VERSION 5.8 ;
BUSBITCHARS "[]" ;
DIVIDERCHAR "/" ;
UNITS
    DATABASE MICRONS 1000 ;
END UNITS

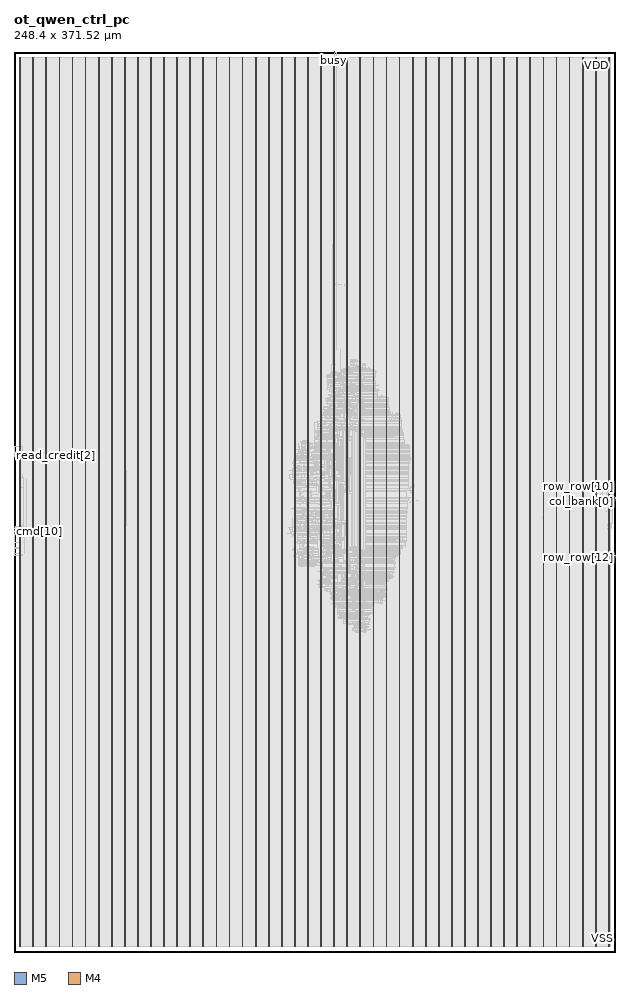
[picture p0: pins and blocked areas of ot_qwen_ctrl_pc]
MACRO ot_qwen_ctrl_pc
  FOREIGN ot_qwen_ctrl_pc 0 0 ;
  CLASS BLOCK ;
  SIZE 248.4 BY 371.52 ;
  PIN busy
    DIRECTION OUTPUT ;
    USE SIGNAL ;
    PORT
      LAYER M5 ;
        RECT  132.144 371.436 132.168 371.52 ;
    END
  END busy
  PIN clk
    DIRECTION INPUT ;
    USE SIGNAL ;
    PORT
      LAYER M5 ;
        RECT  132.24 371.436 132.264 371.52 ;
    END
  END clk
  PIN cmd[0]
    DIRECTION INPUT ;
    USE SIGNAL ;
    PORT
      LAYER M4 ;
        RECT  0 172.656 0.084 172.68 ;
    END
  END cmd[0]
  PIN cmd[10]
    DIRECTION INPUT ;
    USE SIGNAL ;
    PORT
      LAYER M4 ;
        RECT  0 173.616 0.084 173.64 ;
    END
  END cmd[10]
  PIN cmd[11]
    DIRECTION INPUT ;
    USE SIGNAL ;
    PORT
      LAYER M4 ;
        RECT  0 173.712 0.084 173.736 ;
    END
  END cmd[11]
  PIN cmd[12]
    DIRECTION INPUT ;
    USE SIGNAL ;
    PORT
      LAYER M4 ;
        RECT  0 173.808 0.084 173.832 ;
    END
  END cmd[12]
  PIN cmd[13]
    DIRECTION INPUT ;
    USE SIGNAL ;
    PORT
      LAYER M4 ;
        RECT  0 173.904 0.084 173.928 ;
    END
  END cmd[13]
  PIN cmd[14]
    DIRECTION INPUT ;
    USE SIGNAL ;
    PORT
      LAYER M4 ;
        RECT  0 174 0.084 174.024 ;
    END
  END cmd[14]
  PIN cmd[15]
    DIRECTION INPUT ;
    USE SIGNAL ;
    PORT
      LAYER M4 ;
        RECT  0 174.096 0.084 174.12 ;
    END
  END cmd[15]
  PIN cmd[16]
    DIRECTION INPUT ;
    USE SIGNAL ;
    PORT
      LAYER M4 ;
        RECT  0 174.192 0.084 174.216 ;
    END
  END cmd[16]
  PIN cmd[17]
    DIRECTION INPUT ;
    USE SIGNAL ;
    PORT
      LAYER M4 ;
        RECT  0 174.288 0.084 174.312 ;
    END
  END cmd[17]
  PIN cmd[18]
    DIRECTION INPUT ;
    USE SIGNAL ;
    PORT
      LAYER M4 ;
        RECT  0 174.384 0.084 174.408 ;
    END
  END cmd[18]
  PIN cmd[19]
    DIRECTION INPUT ;
    USE SIGNAL ;
    PORT
      LAYER M4 ;
        RECT  0 174.48 0.084 174.504 ;
    END
  END cmd[19]
  PIN cmd[1]
    DIRECTION INPUT ;
    USE SIGNAL ;
    PORT
      LAYER M4 ;
        RECT  0 172.752 0.084 172.776 ;
    END
  END cmd[1]
  PIN cmd[20]
    DIRECTION INPUT ;
    USE SIGNAL ;
    PORT
      LAYER M4 ;
        RECT  0 174.576 0.084 174.6 ;
    END
  END cmd[20]
  PIN cmd[21]
    DIRECTION INPUT ;
    USE SIGNAL ;
    PORT
      LAYER M4 ;
        RECT  0 174.672 0.084 174.696 ;
    END
  END cmd[21]
  PIN cmd[22]
    DIRECTION INPUT ;
    USE SIGNAL ;
    PORT
      LAYER M4 ;
        RECT  0 174.768 0.084 174.792 ;
    END
  END cmd[22]
  PIN cmd[23]
    DIRECTION INPUT ;
    USE SIGNAL ;
    PORT
      LAYER M4 ;
        RECT  0 174.864 0.084 174.888 ;
    END
  END cmd[23]
  PIN cmd[24]
    DIRECTION INPUT ;
    USE SIGNAL ;
    PORT
      LAYER M4 ;
        RECT  0 174.96 0.084 174.984 ;
    END
  END cmd[24]
  PIN cmd[25]
    DIRECTION INPUT ;
    USE SIGNAL ;
    PORT
      LAYER M4 ;
        RECT  0 175.056 0.084 175.08 ;
    END
  END cmd[25]
  PIN cmd[26]
    DIRECTION INPUT ;
    USE SIGNAL ;
    PORT
      LAYER M4 ;
        RECT  0 175.152 0.084 175.176 ;
    END
  END cmd[26]
  PIN cmd[27]
    DIRECTION INPUT ;
    USE SIGNAL ;
    PORT
      LAYER M4 ;
        RECT  0 175.248 0.084 175.272 ;
    END
  END cmd[27]
  PIN cmd[28]
    DIRECTION INPUT ;
    USE SIGNAL ;
    PORT
      LAYER M4 ;
        RECT  0 175.344 0.084 175.368 ;
    END
  END cmd[28]
  PIN cmd[29]
    DIRECTION INPUT ;
    USE SIGNAL ;
    PORT
      LAYER M4 ;
        RECT  0 175.44 0.084 175.464 ;
    END
  END cmd[29]
  PIN cmd[2]
    DIRECTION INPUT ;
    USE SIGNAL ;
    PORT
      LAYER M4 ;
        RECT  0 172.848 0.084 172.872 ;
    END
  END cmd[2]
  PIN cmd[30]
    DIRECTION INPUT ;
    USE SIGNAL ;
    PORT
      LAYER M4 ;
        RECT  0 175.536 0.084 175.56 ;
    END
  END cmd[30]
  PIN cmd[31]
    DIRECTION INPUT ;
    USE SIGNAL ;
    PORT
      LAYER M4 ;
        RECT  0 175.632 0.084 175.656 ;
    END
  END cmd[31]
  PIN cmd[3]
    DIRECTION INPUT ;
    USE SIGNAL ;
    PORT
      LAYER M4 ;
        RECT  0 172.944 0.084 172.968 ;
    END
  END cmd[3]
  PIN cmd[4]
    DIRECTION INPUT ;
    USE SIGNAL ;
    PORT
      LAYER M4 ;
        RECT  0 173.04 0.084 173.064 ;
    END
  END cmd[4]
  PIN cmd[5]
    DIRECTION INPUT ;
    USE SIGNAL ;
    PORT
      LAYER M4 ;
        RECT  0 173.136 0.084 173.16 ;
    END
  END cmd[5]
  PIN cmd[6]
    DIRECTION INPUT ;
    USE SIGNAL ;
    PORT
      LAYER M4 ;
        RECT  0 173.232 0.084 173.256 ;
    END
  END cmd[6]
  PIN cmd[7]
    DIRECTION INPUT ;
    USE SIGNAL ;
    PORT
      LAYER M4 ;
        RECT  0 173.328 0.084 173.352 ;
    END
  END cmd[7]
  PIN cmd[8]
    DIRECTION INPUT ;
    USE SIGNAL ;
    PORT
      LAYER M4 ;
        RECT  0 173.424 0.084 173.448 ;
    END
  END cmd[8]
  PIN cmd[9]
    DIRECTION INPUT ;
    USE SIGNAL ;
    PORT
      LAYER M4 ;
        RECT  0 173.52 0.084 173.544 ;
    END
  END cmd[9]
  PIN cmd_credit
    DIRECTION OUTPUT ;
    USE SIGNAL ;
    PORT
      LAYER M4 ;
        RECT  0 204.72 0.084 204.744 ;
    END
  END cmd_credit
  PIN cmd_v
    DIRECTION INPUT ;
    USE SIGNAL ;
    PORT
      LAYER M4 ;
        RECT  0 204.816 0.084 204.84 ;
    END
  END cmd_v
  PIN col_bank[0]
    DIRECTION OUTPUT ;
    USE SIGNAL ;
    PORT
      LAYER M4 ;
        RECT  248.316 185.808 248.4 185.832 ;
    END
  END col_bank[0]
  PIN col_bank[1]
    DIRECTION OUTPUT ;
    USE SIGNAL ;
    PORT
      LAYER M4 ;
        RECT  248.316 185.904 248.4 185.928 ;
    END
  END col_bank[1]
  PIN col_bank[2]
    DIRECTION OUTPUT ;
    USE SIGNAL ;
    PORT
      LAYER M4 ;
        RECT  248.316 186 248.4 186.024 ;
    END
  END col_bank[2]
  PIN col_bank[3]
    DIRECTION OUTPUT ;
    USE SIGNAL ;
    PORT
      LAYER M4 ;
        RECT  248.316 186.096 248.4 186.12 ;
    END
  END col_bank[3]
  PIN col_bank[4]
    DIRECTION OUTPUT ;
    USE SIGNAL ;
    PORT
      LAYER M4 ;
        RECT  248.316 186.192 248.4 186.216 ;
    END
  END col_bank[4]
  PIN col_col[0]
    DIRECTION OUTPUT ;
    USE SIGNAL ;
    PORT
      LAYER M4 ;
        RECT  248.316 186.288 248.4 186.312 ;
    END
  END col_col[0]
  PIN col_col[1]
    DIRECTION OUTPUT ;
    USE SIGNAL ;
    PORT
      LAYER M4 ;
        RECT  248.316 186.384 248.4 186.408 ;
    END
  END col_col[1]
  PIN col_col[2]
    DIRECTION OUTPUT ;
    USE SIGNAL ;
    PORT
      LAYER M4 ;
        RECT  248.316 186.48 248.4 186.504 ;
    END
  END col_col[2]
  PIN col_col[3]
    DIRECTION OUTPUT ;
    USE SIGNAL ;
    PORT
      LAYER M4 ;
        RECT  248.316 186.576 248.4 186.6 ;
    END
  END col_col[3]
  PIN col_col[4]
    DIRECTION OUTPUT ;
    USE SIGNAL ;
    PORT
      LAYER M4 ;
        RECT  248.316 186.672 248.4 186.696 ;
    END
  END col_col[4]
  PIN col_v
    DIRECTION OUTPUT ;
    USE SIGNAL ;
    PORT
      LAYER M4 ;
        RECT  248.316 186.768 248.4 186.792 ;
    END
  END col_v
  PIN col_we
    DIRECTION OUTPUT ;
    USE SIGNAL ;
    PORT
      LAYER M4 ;
        RECT  248.316 186.864 248.4 186.888 ;
    END
  END col_we
  PIN fault
    DIRECTION OUTPUT ;
    USE SIGNAL ;
    PORT
      LAYER M5 ;
        RECT  132.336 371.436 132.36 371.52 ;
    END
  END fault
  PIN read_credit[0]
    DIRECTION INPUT ;
    USE SIGNAL ;
    PORT
      LAYER M4 ;
        RECT  0 204.912 0.084 204.936 ;
    END
  END read_credit[0]
  PIN read_credit[1]
    DIRECTION INPUT ;
    USE SIGNAL ;
    PORT
      LAYER M4 ;
        RECT  0 205.008 0.084 205.032 ;
    END
  END read_credit[1]
  PIN read_credit[2]
    DIRECTION INPUT ;
    USE SIGNAL ;
    PORT
      LAYER M4 ;
        RECT  0 205.104 0.084 205.128 ;
    END
  END read_credit[2]
  PIN row_bank[0]
    DIRECTION OUTPUT ;
    USE SIGNAL ;
    PORT
      LAYER M4 ;
        RECT  248.316 186.96 248.4 186.984 ;
    END
  END row_bank[0]
  PIN row_bank[1]
    DIRECTION OUTPUT ;
    USE SIGNAL ;
    PORT
      LAYER M4 ;
        RECT  248.316 187.056 248.4 187.08 ;
    END
  END row_bank[1]
  PIN row_bank[2]
    DIRECTION OUTPUT ;
    USE SIGNAL ;
    PORT
      LAYER M4 ;
        RECT  248.316 187.152 248.4 187.176 ;
    END
  END row_bank[2]
  PIN row_bank[3]
    DIRECTION OUTPUT ;
    USE SIGNAL ;
    PORT
      LAYER M4 ;
        RECT  248.316 187.248 248.4 187.272 ;
    END
  END row_bank[3]
  PIN row_bank[4]
    DIRECTION OUTPUT ;
    USE SIGNAL ;
    PORT
      LAYER M4 ;
        RECT  248.316 187.344 248.4 187.368 ;
    END
  END row_bank[4]
  PIN row_op[0]
    DIRECTION OUTPUT ;
    USE SIGNAL ;
    PORT
      LAYER M4 ;
        RECT  248.316 187.44 248.4 187.464 ;
    END
  END row_op[0]
  PIN row_op[1]
    DIRECTION OUTPUT ;
    USE SIGNAL ;
    PORT
      LAYER M4 ;
        RECT  248.316 187.536 248.4 187.56 ;
    END
  END row_op[1]
  PIN row_op[2]
    DIRECTION OUTPUT ;
    USE SIGNAL ;
    PORT
      LAYER M4 ;
        RECT  248.316 187.632 248.4 187.656 ;
    END
  END row_op[2]
  PIN row_row[0]
    DIRECTION OUTPUT ;
    USE SIGNAL ;
    PORT
      LAYER M4 ;
        RECT  248.316 187.728 248.4 187.752 ;
    END
  END row_row[0]
  PIN row_row[10]
    DIRECTION OUTPUT ;
    USE SIGNAL ;
    PORT
      LAYER M4 ;
        RECT  248.316 188.688 248.4 188.712 ;
    END
  END row_row[10]
  PIN row_row[11]
    DIRECTION OUTPUT ;
    USE SIGNAL ;
    PORT
      LAYER M4 ;
        RECT  248.316 188.784 248.4 188.808 ;
    END
  END row_row[11]
  PIN row_row[12]
    DIRECTION OUTPUT ;
    USE SIGNAL ;
    PORT
      LAYER M4 ;
        RECT  248.316 162.768 248.4 162.792 ;
    END
  END row_row[12]
  PIN row_row[13]
    DIRECTION OUTPUT ;
    USE SIGNAL ;
    PORT
      LAYER M4 ;
        RECT  248.316 162.864 248.4 162.888 ;
    END
  END row_row[13]
  PIN row_row[14]
    DIRECTION OUTPUT ;
    USE SIGNAL ;
    PORT
      LAYER M4 ;
        RECT  248.316 162.96 248.4 162.984 ;
    END
  END row_row[14]
  PIN row_row[15]
    DIRECTION OUTPUT ;
    USE SIGNAL ;
    PORT
      LAYER M4 ;
        RECT  248.316 163.056 248.4 163.08 ;
    END
  END row_row[15]
  PIN row_row[16]
    DIRECTION OUTPUT ;
    USE SIGNAL ;
    PORT
      LAYER M4 ;
        RECT  248.316 163.152 248.4 163.176 ;
    END
  END row_row[16]
  PIN row_row[17]
    DIRECTION OUTPUT ;
    USE SIGNAL ;
    PORT
      LAYER M4 ;
        RECT  248.316 163.248 248.4 163.272 ;
    END
  END row_row[17]
  PIN row_row[18]
    DIRECTION OUTPUT ;
    USE SIGNAL ;
    PORT
      LAYER M4 ;
        RECT  248.316 163.344 248.4 163.368 ;
    END
  END row_row[18]
  PIN row_row[1]
    DIRECTION OUTPUT ;
    USE SIGNAL ;
    PORT
      LAYER M4 ;
        RECT  248.316 187.824 248.4 187.848 ;
    END
  END row_row[1]
  PIN row_row[2]
    DIRECTION OUTPUT ;
    USE SIGNAL ;
    PORT
      LAYER M4 ;
        RECT  248.316 187.92 248.4 187.944 ;
    END
  END row_row[2]
  PIN row_row[3]
    DIRECTION OUTPUT ;
    USE SIGNAL ;
    PORT
      LAYER M4 ;
        RECT  248.316 188.016 248.4 188.04 ;
    END
  END row_row[3]
  PIN row_row[4]
    DIRECTION OUTPUT ;
    USE SIGNAL ;
    PORT
      LAYER M4 ;
        RECT  248.316 188.112 248.4 188.136 ;
    END
  END row_row[4]
  PIN row_row[5]
    DIRECTION OUTPUT ;
    USE SIGNAL ;
    PORT
      LAYER M4 ;
        RECT  248.316 188.208 248.4 188.232 ;
    END
  END row_row[5]
  PIN row_row[6]
    DIRECTION OUTPUT ;
    USE SIGNAL ;
    PORT
      LAYER M4 ;
        RECT  248.316 188.304 248.4 188.328 ;
    END
  END row_row[6]
  PIN row_row[7]
    DIRECTION OUTPUT ;
    USE SIGNAL ;
    PORT
      LAYER M4 ;
        RECT  248.316 188.4 248.4 188.424 ;
    END
  END row_row[7]
  PIN row_row[8]
    DIRECTION OUTPUT ;
    USE SIGNAL ;
    PORT
      LAYER M4 ;
        RECT  248.316 188.496 248.4 188.52 ;
    END
  END row_row[8]
  PIN row_row[9]
    DIRECTION OUTPUT ;
    USE SIGNAL ;
    PORT
      LAYER M4 ;
        RECT  248.316 188.592 248.4 188.616 ;
    END
  END row_row[9]
  PIN row_v
    DIRECTION OUTPUT ;
    USE SIGNAL ;
    PORT
      LAYER M4 ;
        RECT  248.316 163.44 248.4 163.464 ;
    END
  END row_v
  PIN rst_n
    DIRECTION INPUT ;
    USE SIGNAL ;
    PORT
      LAYER M5 ;
        RECT  132.432 371.436 132.456 371.52 ;
    END
  END rst_n
  PIN VDD
    DIRECTION INOUT ;
    USE POWER ;
    PORT
      LAYER M5 ;
        RECT  245.592 2.151 245.712 369.369 ;
        RECT  240.192 2.151 240.312 369.369 ;
        RECT  234.792 2.151 234.912 369.369 ;
        RECT  229.392 2.151 229.512 369.369 ;
        RECT  223.992 2.151 224.112 369.369 ;
        RECT  218.592 2.151 218.712 369.369 ;
        RECT  213.192 2.151 213.312 369.369 ;
        RECT  207.792 2.151 207.912 369.369 ;
        RECT  202.392 2.151 202.512 369.369 ;
        RECT  196.992 2.151 197.112 369.369 ;
        RECT  191.592 2.151 191.712 369.369 ;
        RECT  186.192 2.151 186.312 369.369 ;
        RECT  180.792 2.151 180.912 369.369 ;
        RECT  175.392 2.151 175.512 369.369 ;
        RECT  169.992 2.151 170.112 369.369 ;
        RECT  164.592 2.151 164.712 369.369 ;
        RECT  159.192 2.151 159.312 369.369 ;
        RECT  153.792 2.151 153.912 369.369 ;
        RECT  148.392 2.151 148.512 369.369 ;
        RECT  142.992 2.151 143.112 369.369 ;
        RECT  137.592 2.151 137.712 369.369 ;
        RECT  132.192 2.151 132.312 369.369 ;
        RECT  126.792 2.151 126.912 369.369 ;
        RECT  121.392 2.151 121.512 369.369 ;
        RECT  115.992 2.151 116.112 369.369 ;
        RECT  110.592 2.151 110.712 369.369 ;
        RECT  105.192 2.151 105.312 369.369 ;
        RECT  99.792 2.151 99.912 369.369 ;
        RECT  94.392 2.151 94.512 369.369 ;
        RECT  88.992 2.151 89.112 369.369 ;
        RECT  83.592 2.151 83.712 369.369 ;
        RECT  78.192 2.151 78.312 369.369 ;
        RECT  72.792 2.151 72.912 369.369 ;
        RECT  67.392 2.151 67.512 369.369 ;
        RECT  61.992 2.151 62.112 369.369 ;
        RECT  56.592 2.151 56.712 369.369 ;
        RECT  51.192 2.151 51.312 369.369 ;
        RECT  45.792 2.151 45.912 369.369 ;
        RECT  40.392 2.151 40.512 369.369 ;
        RECT  34.992 2.151 35.112 369.369 ;
        RECT  29.592 2.151 29.712 369.369 ;
        RECT  24.192 2.151 24.312 369.369 ;
        RECT  18.792 2.151 18.912 369.369 ;
        RECT  13.392 2.151 13.512 369.369 ;
        RECT  7.992 2.151 8.112 369.369 ;
        RECT  2.592 2.151 2.712 369.369 ;
    END
  END VDD
  PIN VSS
    DIRECTION INOUT ;
    USE GROUND ;
    PORT
      LAYER M5 ;
        RECT  245.4 2.137 245.52 369.383 ;
        RECT  240 2.137 240.12 369.383 ;
        RECT  234.6 2.137 234.72 369.383 ;
        RECT  229.2 2.137 229.32 369.383 ;
        RECT  223.8 2.137 223.92 369.383 ;
        RECT  218.4 2.137 218.52 369.383 ;
        RECT  213 2.137 213.12 369.383 ;
        RECT  207.6 2.137 207.72 369.383 ;
        RECT  202.2 2.137 202.32 369.383 ;
        RECT  196.8 2.137 196.92 369.383 ;
        RECT  191.4 2.137 191.52 369.383 ;
        RECT  186 2.137 186.12 369.383 ;
        RECT  180.6 2.137 180.72 369.383 ;
        RECT  175.2 2.137 175.32 369.383 ;
        RECT  169.8 2.137 169.92 369.383 ;
        RECT  164.4 2.137 164.52 369.383 ;
        RECT  159 2.137 159.12 369.383 ;
        RECT  153.6 2.137 153.72 369.383 ;
        RECT  148.2 2.137 148.32 369.383 ;
        RECT  142.8 2.137 142.92 369.383 ;
        RECT  137.4 2.137 137.52 369.383 ;
        RECT  132 2.137 132.12 369.383 ;
        RECT  126.6 2.137 126.72 369.383 ;
        RECT  121.2 2.137 121.32 369.383 ;
        RECT  115.8 2.137 115.92 369.383 ;
        RECT  110.4 2.137 110.52 369.383 ;
        RECT  105 2.137 105.12 369.383 ;
        RECT  99.6 2.137 99.72 369.383 ;
        RECT  94.2 2.137 94.32 369.383 ;
        RECT  88.8 2.137 88.92 369.383 ;
        RECT  83.4 2.137 83.52 369.383 ;
        RECT  78 2.137 78.12 369.383 ;
        RECT  72.6 2.137 72.72 369.383 ;
        RECT  67.2 2.137 67.32 369.383 ;
        RECT  61.8 2.137 61.92 369.383 ;
        RECT  56.4 2.137 56.52 369.383 ;
        RECT  51 2.137 51.12 369.383 ;
        RECT  45.6 2.137 45.72 369.383 ;
        RECT  40.2 2.137 40.32 369.383 ;
        RECT  34.8 2.137 34.92 369.383 ;
        RECT  29.4 2.137 29.52 369.383 ;
        RECT  24 2.137 24.12 369.383 ;
        RECT  18.6 2.137 18.72 369.383 ;
        RECT  13.2 2.137 13.32 369.383 ;
        RECT  7.8 2.137 7.92 369.383 ;
        RECT  2.4 2.137 2.52 369.383 ;
    END
  END VSS
  OBS
    LAYER RVTN ;
     RECT  2.16 2.16 246.24 2.295 ;
     RECT  2.16 2.565 246.24 2.835 ;
     RECT  2.16 3.105 246.24 3.375 ;
     RECT  2.16 3.645 246.24 3.915 ;
     RECT  2.16 4.185 246.24 4.455 ;
     RECT  2.16 4.725 246.24 4.995 ;
     RECT  2.16 5.265 246.24 5.535 ;
     RECT  2.16 5.805 246.24 6.075 ;
     RECT  2.16 6.345 246.24 6.615 ;
     RECT  2.16 6.885 246.24 7.155 ;
     RECT  2.16 7.425 246.24 7.695 ;
     RECT  2.16 7.965 246.24 8.235 ;
     RECT  2.16 8.505 246.24 8.775 ;
     RECT  2.16 9.045 246.24 9.315 ;
     RECT  2.16 9.585 246.24 9.855 ;
     RECT  2.16 10.125 246.24 10.395 ;
     RECT  2.16 10.665 246.24 10.935 ;
     RECT  2.16 11.205 246.24 11.475 ;
     RECT  2.16 11.745 246.24 12.015 ;
     RECT  2.16 12.285 246.24 12.555 ;
     RECT  2.16 12.825 246.24 13.095 ;
     RECT  2.16 13.365 246.24 13.635 ;
     RECT  2.16 13.905 246.24 14.175 ;
     RECT  2.16 14.445 246.24 14.715 ;
     RECT  2.16 14.985 246.24 15.255 ;
     RECT  2.16 15.525 246.24 15.795 ;
     RECT  2.16 16.065 246.24 16.335 ;
     RECT  2.16 16.605 246.24 16.875 ;
     RECT  2.16 17.145 246.24 17.415 ;
     RECT  2.16 17.685 246.24 17.955 ;
     RECT  2.16 18.225 246.24 18.495 ;
     RECT  2.16 18.765 246.24 19.035 ;
     RECT  2.16 19.305 246.24 19.575 ;
     RECT  2.16 19.845 246.24 20.115 ;
     RECT  2.16 20.385 246.24 20.655 ;
     RECT  2.16 20.925 246.24 21.195 ;
     RECT  2.16 21.465 246.24 21.735 ;
     RECT  2.16 22.005 246.24 22.275 ;
     RECT  2.16 22.545 246.24 22.815 ;
     RECT  2.16 23.085 246.24 23.355 ;
     RECT  2.16 23.625 246.24 23.895 ;
     RECT  2.16 24.165 246.24 24.435 ;
     RECT  2.16 24.705 246.24 24.975 ;
     RECT  2.16 25.245 246.24 25.515 ;
     RECT  2.16 25.785 246.24 26.055 ;
     RECT  2.16 26.325 246.24 26.595 ;
     RECT  2.16 26.865 246.24 27.135 ;
     RECT  2.16 27.405 246.24 27.675 ;
     RECT  2.16 27.945 246.24 28.215 ;
     RECT  2.16 28.485 246.24 28.755 ;
     RECT  2.16 29.025 246.24 29.295 ;
     RECT  2.16 29.565 246.24 29.835 ;
     RECT  2.16 30.105 246.24 30.375 ;
     RECT  2.16 30.645 246.24 30.915 ;
     RECT  2.16 31.185 246.24 31.455 ;
     RECT  2.16 31.725 246.24 31.995 ;
     RECT  2.16 32.265 246.24 32.535 ;
     RECT  2.16 32.805 246.24 33.075 ;
     RECT  2.16 33.345 246.24 33.615 ;
     RECT  2.16 33.885 246.24 34.155 ;
     RECT  2.16 34.425 246.24 34.695 ;
     RECT  2.16 34.965 246.24 35.235 ;
     RECT  2.16 35.505 246.24 35.775 ;
     RECT  2.16 36.045 246.24 36.315 ;
     RECT  2.16 36.585 246.24 36.855 ;
     RECT  2.16 37.125 246.24 37.395 ;
     RECT  2.16 37.665 246.24 37.935 ;
     RECT  2.16 38.205 246.24 38.475 ;
     RECT  2.16 38.745 246.24 39.015 ;
     RECT  2.16 39.285 246.24 39.555 ;
     RECT  2.16 39.825 246.24 40.095 ;
     RECT  2.16 40.365 246.24 40.635 ;
     RECT  2.16 40.905 246.24 41.175 ;
     RECT  2.16 41.445 246.24 41.715 ;
     RECT  2.16 41.985 246.24 42.255 ;
     RECT  2.16 42.525 246.24 42.795 ;
     RECT  2.16 43.065 246.24 43.335 ;
     RECT  2.16 43.605 246.24 43.875 ;
     RECT  2.16 44.145 246.24 44.415 ;
     RECT  2.16 44.685 246.24 44.955 ;
     RECT  2.16 45.225 246.24 45.495 ;
     RECT  2.16 45.765 246.24 46.035 ;
     RECT  2.16 46.305 246.24 46.575 ;
     RECT  2.16 46.845 246.24 47.115 ;
     RECT  2.16 47.385 246.24 47.655 ;
     RECT  2.16 47.925 246.24 48.195 ;
     RECT  2.16 48.465 246.24 48.735 ;
     RECT  2.16 49.005 246.24 49.275 ;
     RECT  2.16 49.545 246.24 49.815 ;
     RECT  2.16 50.085 246.24 50.355 ;
     RECT  2.16 50.625 246.24 50.895 ;
     RECT  2.16 51.165 246.24 51.435 ;
     RECT  2.16 51.705 246.24 51.975 ;
     RECT  2.16 52.245 246.24 52.515 ;
     RECT  2.16 52.785 246.24 53.055 ;
     RECT  2.16 53.325 246.24 53.595 ;
     RECT  2.16 53.865 246.24 54.135 ;
     RECT  2.16 54.405 246.24 54.675 ;
     RECT  2.16 54.945 246.24 55.215 ;
     RECT  2.16 55.485 246.24 55.755 ;
     RECT  2.16 56.025 246.24 56.295 ;
     RECT  2.16 56.565 246.24 56.835 ;
     RECT  2.16 57.105 246.24 57.375 ;
     RECT  2.16 57.645 246.24 57.915 ;
     RECT  2.16 58.185 246.24 58.455 ;
     RECT  2.16 58.725 246.24 58.995 ;
     RECT  2.16 59.265 246.24 59.535 ;
     RECT  2.16 59.805 246.24 60.075 ;
     RECT  2.16 60.345 246.24 60.615 ;
     RECT  2.16 60.885 246.24 61.155 ;
     RECT  2.16 61.425 246.24 61.695 ;
     RECT  2.16 61.965 246.24 62.235 ;
     RECT  2.16 62.505 246.24 62.775 ;
     RECT  2.16 63.045 246.24 63.315 ;
     RECT  2.16 63.585 246.24 63.855 ;
     RECT  2.16 64.125 246.24 64.395 ;
     RECT  2.16 64.665 246.24 64.935 ;
     RECT  2.16 65.205 246.24 65.475 ;
     RECT  2.16 65.745 246.24 66.015 ;
     RECT  2.16 66.285 246.24 66.555 ;
     RECT  2.16 66.825 246.24 67.095 ;
     RECT  2.16 67.365 246.24 67.635 ;
     RECT  2.16 67.905 246.24 68.175 ;
     RECT  2.16 68.445 246.24 68.715 ;
     RECT  2.16 68.985 246.24 69.255 ;
     RECT  2.16 69.525 246.24 69.795 ;
     RECT  2.16 70.065 246.24 70.335 ;
     RECT  2.16 70.605 246.24 70.875 ;
     RECT  2.16 71.145 246.24 71.415 ;
     RECT  2.16 71.685 246.24 71.955 ;
     RECT  2.16 72.225 246.24 72.495 ;
     RECT  2.16 72.765 246.24 73.035 ;
     RECT  2.16 73.305 246.24 73.575 ;
     RECT  2.16 73.845 246.24 74.115 ;
     RECT  2.16 74.385 246.24 74.655 ;
     RECT  2.16 74.925 246.24 75.195 ;
     RECT  2.16 75.465 246.24 75.735 ;
     RECT  2.16 76.005 246.24 76.275 ;
     RECT  2.16 76.545 246.24 76.815 ;
     RECT  2.16 77.085 246.24 77.355 ;
     RECT  2.16 77.625 246.24 77.895 ;
     RECT  2.16 78.165 246.24 78.435 ;
     RECT  2.16 78.705 246.24 78.975 ;
     RECT  2.16 79.245 246.24 79.515 ;
     RECT  2.16 79.785 246.24 80.055 ;
     RECT  2.16 80.325 246.24 80.595 ;
     RECT  2.16 80.865 246.24 81.135 ;
     RECT  2.16 81.405 246.24 81.675 ;
     RECT  2.16 81.945 246.24 82.215 ;
     RECT  2.16 82.485 246.24 82.755 ;
     RECT  2.16 83.025 246.24 83.295 ;
     RECT  2.16 83.565 246.24 83.835 ;
     RECT  2.16 84.105 246.24 84.375 ;
     RECT  2.16 84.645 246.24 84.915 ;
     RECT  2.16 85.185 246.24 85.455 ;
     RECT  2.16 85.725 246.24 85.995 ;
     RECT  2.16 86.265 246.24 86.535 ;
     RECT  2.16 86.805 246.24 87.075 ;
     RECT  2.16 87.345 246.24 87.615 ;
     RECT  2.16 87.885 246.24 88.155 ;
     RECT  2.16 88.425 246.24 88.695 ;
     RECT  2.16 88.965 246.24 89.235 ;
     RECT  2.16 89.505 246.24 89.775 ;
     RECT  2.16 90.045 246.24 90.315 ;
     RECT  2.16 90.585 246.24 90.855 ;
     RECT  2.16 91.125 246.24 91.395 ;
     RECT  2.16 91.665 246.24 91.935 ;
     RECT  2.16 92.205 246.24 92.475 ;
     RECT  2.16 92.745 246.24 93.015 ;
     RECT  2.16 93.285 246.24 93.555 ;
     RECT  2.16 93.825 246.24 94.095 ;
     RECT  2.16 94.365 246.24 94.635 ;
     RECT  2.16 94.905 246.24 95.175 ;
     RECT  2.16 95.445 246.24 95.715 ;
     RECT  2.16 95.985 246.24 96.255 ;
     RECT  2.16 96.525 246.24 96.795 ;
     RECT  2.16 97.065 246.24 97.335 ;
     RECT  2.16 97.605 246.24 97.875 ;
     RECT  2.16 98.145 246.24 98.415 ;
     RECT  2.16 98.685 246.24 98.955 ;
     RECT  2.16 99.225 246.24 99.495 ;
     RECT  2.16 99.765 246.24 100.035 ;
     RECT  2.16 100.305 246.24 100.575 ;
     RECT  2.16 100.845 246.24 101.115 ;
     RECT  2.16 101.385 246.24 101.655 ;
     RECT  2.16 101.925 246.24 102.195 ;
     RECT  2.16 102.465 246.24 102.735 ;
     RECT  2.16 103.005 246.24 103.275 ;
     RECT  2.16 103.545 246.24 103.815 ;
     RECT  2.16 104.085 246.24 104.355 ;
     RECT  2.16 104.625 246.24 104.895 ;
     RECT  2.16 105.165 246.24 105.435 ;
     RECT  2.16 105.705 246.24 105.975 ;
     RECT  2.16 106.245 246.24 106.515 ;
     RECT  2.16 106.785 246.24 107.055 ;
     RECT  2.16 107.325 246.24 107.595 ;
     RECT  2.16 107.865 246.24 108.135 ;
     RECT  2.16 108.405 246.24 108.675 ;
     RECT  2.16 108.945 246.24 109.215 ;
     RECT  2.16 109.485 246.24 109.755 ;
     RECT  2.16 110.025 246.24 110.295 ;
     RECT  2.16 110.565 246.24 110.835 ;
     RECT  2.16 111.105 246.24 111.375 ;
     RECT  2.16 111.645 246.24 111.915 ;
     RECT  2.16 112.185 246.24 112.455 ;
     RECT  2.16 112.725 246.24 112.995 ;
     RECT  2.16 113.265 246.24 113.535 ;
     RECT  2.16 113.805 246.24 114.075 ;
     RECT  2.16 114.345 246.24 114.615 ;
     RECT  2.16 114.885 246.24 115.155 ;
     RECT  2.16 115.425 246.24 115.695 ;
     RECT  2.16 115.965 246.24 116.235 ;
     RECT  2.16 116.505 246.24 116.775 ;
     RECT  2.16 117.045 246.24 117.315 ;
     RECT  2.16 117.585 246.24 117.855 ;
     RECT  2.16 118.125 246.24 118.395 ;
     RECT  2.16 118.665 246.24 118.935 ;
     RECT  2.16 119.205 246.24 119.475 ;
     RECT  2.16 119.745 246.24 120.015 ;
     RECT  2.16 120.285 246.24 120.555 ;
     RECT  2.16 120.825 246.24 121.095 ;
     RECT  2.16 121.365 246.24 121.635 ;
     RECT  2.16 121.905 246.24 122.175 ;
     RECT  2.16 122.445 246.24 122.715 ;
     RECT  2.16 122.985 246.24 123.255 ;
     RECT  2.16 123.525 246.24 123.795 ;
     RECT  2.16 124.065 246.24 124.335 ;
     RECT  2.16 124.605 246.24 124.875 ;
     RECT  2.16 125.145 246.24 125.415 ;
     RECT  2.16 125.685 246.24 125.955 ;
     RECT  2.16 126.225 246.24 126.495 ;
     RECT  2.16 126.765 246.24 127.035 ;
     RECT  2.16 127.305 246.24 127.575 ;
     RECT  2.16 127.845 246.24 128.115 ;
     RECT  2.16 128.385 246.24 128.655 ;
     RECT  2.16 128.925 246.24 129.195 ;
     RECT  2.16 129.465 246.24 129.735 ;
     RECT  2.16 130.005 246.24 130.275 ;
     RECT  2.16 130.545 246.24 130.815 ;
     RECT  2.16 131.085 246.24 131.355 ;
     RECT  2.16 131.625 246.24 131.895 ;
     RECT  2.16 132.165 246.24 132.435 ;
     RECT  2.16 132.705 246.24 132.975 ;
     RECT  2.16 133.245 246.24 133.515 ;
     RECT  2.16 133.785 246.24 134.055 ;
     RECT  2.16 134.325 246.24 134.595 ;
     RECT  2.16 134.865 246.24 135.135 ;
     RECT  2.16 135.405 246.24 135.675 ;
     RECT  2.16 135.945 246.24 136.215 ;
     RECT  2.16 136.485 246.24 136.755 ;
     RECT  2.16 137.025 246.24 137.295 ;
     RECT  2.16 137.565 246.24 137.835 ;
     RECT  2.16 138.105 246.24 138.375 ;
     RECT  2.16 138.645 246.24 138.915 ;
     RECT  2.16 139.185 246.24 139.455 ;
     RECT  2.16 139.725 246.24 139.995 ;
     RECT  2.16 140.265 246.24 140.535 ;
     RECT  2.16 140.805 246.24 141.075 ;
     RECT  2.16 141.345 246.24 141.615 ;
     RECT  2.16 141.885 246.24 142.155 ;
     RECT  2.16 142.425 246.24 142.695 ;
     RECT  2.16 142.965 246.24 143.235 ;
     RECT  2.16 143.505 246.24 143.775 ;
     RECT  2.16 144.045 246.24 144.315 ;
     RECT  2.16 144.585 246.24 144.855 ;
     RECT  2.16 145.125 246.24 145.395 ;
     RECT  2.16 145.665 246.24 145.935 ;
     RECT  2.16 146.205 246.24 146.475 ;
     RECT  2.16 146.745 246.24 147.015 ;
     RECT  2.16 147.285 246.24 147.555 ;
     RECT  2.16 147.825 246.24 148.095 ;
     RECT  2.16 148.365 246.24 148.635 ;
     RECT  2.16 148.905 246.24 149.175 ;
     RECT  2.16 149.445 246.24 149.715 ;
     RECT  2.16 149.985 246.24 150.255 ;
     RECT  2.16 150.525 246.24 150.795 ;
     RECT  2.16 151.065 246.24 151.335 ;
     RECT  2.16 151.605 246.24 151.875 ;
     RECT  2.16 152.145 246.24 152.415 ;
     RECT  2.16 152.685 246.24 152.955 ;
     RECT  2.16 153.225 246.24 153.495 ;
     RECT  2.16 153.765 246.24 154.035 ;
     RECT  2.16 154.305 246.24 154.575 ;
     RECT  2.16 154.845 246.24 155.115 ;
     RECT  2.16 155.385 246.24 155.655 ;
     RECT  2.16 155.925 246.24 156.195 ;
     RECT  2.16 156.465 246.24 156.735 ;
     RECT  2.16 157.005 246.24 157.275 ;
     RECT  2.16 157.545 246.24 157.815 ;
     RECT  2.16 158.085 246.24 158.355 ;
     RECT  2.16 158.625 246.24 158.895 ;
     RECT  2.16 159.165 246.24 159.435 ;
     RECT  2.16 159.705 246.24 159.975 ;
     RECT  2.16 160.245 246.24 160.515 ;
     RECT  2.16 160.785 246.24 161.055 ;
     RECT  2.16 161.325 246.24 161.595 ;
     RECT  2.16 161.865 246.24 162.135 ;
     RECT  2.16 162.405 246.24 162.675 ;
     RECT  2.16 162.945 246.24 163.215 ;
     RECT  2.16 163.485 246.24 163.755 ;
     RECT  2.16 164.025 246.24 164.295 ;
     RECT  2.16 164.565 246.24 164.835 ;
     RECT  2.16 165.105 246.24 165.375 ;
     RECT  2.16 165.645 246.24 165.915 ;
     RECT  2.16 166.185 246.24 166.455 ;
     RECT  2.16 166.725 246.24 166.995 ;
     RECT  2.16 167.265 246.24 167.535 ;
     RECT  2.16 167.805 246.24 168.075 ;
     RECT  2.16 168.345 246.24 168.615 ;
     RECT  2.16 168.885 246.24 169.155 ;
     RECT  2.16 169.425 246.24 169.695 ;
     RECT  2.16 169.965 246.24 170.235 ;
     RECT  2.16 170.505 246.24 170.775 ;
     RECT  2.16 171.045 246.24 171.315 ;
     RECT  2.16 171.585 246.24 171.855 ;
     RECT  2.16 172.125 246.24 172.395 ;
     RECT  2.16 172.665 246.24 172.935 ;
     RECT  2.16 173.205 246.24 173.475 ;
     RECT  2.16 173.745 246.24 174.015 ;
     RECT  2.16 174.285 246.24 174.555 ;
     RECT  2.16 174.825 246.24 175.095 ;
     RECT  2.16 175.365 246.24 175.635 ;
     RECT  2.16 175.905 246.24 176.175 ;
     RECT  2.16 176.445 246.24 176.715 ;
     RECT  2.16 176.985 246.24 177.255 ;
     RECT  2.16 177.525 246.24 177.795 ;
     RECT  2.16 178.065 246.24 178.335 ;
     RECT  2.16 178.605 246.24 178.875 ;
     RECT  2.16 179.145 246.24 179.415 ;
     RECT  2.16 179.685 246.24 179.955 ;
     RECT  2.16 180.225 246.24 180.495 ;
     RECT  2.16 180.765 246.24 181.035 ;
     RECT  2.16 181.305 246.24 181.575 ;
     RECT  2.16 181.845 246.24 182.115 ;
     RECT  2.16 182.385 246.24 182.655 ;
     RECT  2.16 182.925 246.24 183.195 ;
     RECT  2.16 183.465 246.24 183.735 ;
     RECT  2.16 184.005 246.24 184.275 ;
     RECT  2.16 184.545 246.24 184.815 ;
     RECT  2.16 185.085 246.24 185.355 ;
     RECT  2.16 185.625 246.24 185.895 ;
     RECT  2.16 186.165 246.24 186.435 ;
     RECT  2.16 186.705 246.24 186.975 ;
     RECT  2.16 187.245 246.24 187.515 ;
     RECT  2.16 187.785 246.24 188.055 ;
     RECT  2.16 188.325 246.24 188.595 ;
     RECT  2.16 188.865 246.24 189.135 ;
     RECT  2.16 189.405 246.24 189.675 ;
     RECT  2.16 189.945 246.24 190.215 ;
     RECT  2.16 190.485 246.24 190.755 ;
     RECT  2.16 191.025 246.24 191.295 ;
     RECT  2.16 191.565 246.24 191.835 ;
     RECT  2.16 192.105 246.24 192.375 ;
     RECT  2.16 192.645 246.24 192.915 ;
     RECT  2.16 193.185 246.24 193.455 ;
     RECT  2.16 193.725 246.24 193.995 ;
     RECT  2.16 194.265 246.24 194.535 ;
     RECT  2.16 194.805 246.24 195.075 ;
     RECT  2.16 195.345 246.24 195.615 ;
     RECT  2.16 195.885 246.24 196.155 ;
     RECT  2.16 196.425 246.24 196.695 ;
     RECT  2.16 196.965 246.24 197.235 ;
     RECT  2.16 197.505 246.24 197.775 ;
     RECT  2.16 198.045 246.24 198.315 ;
     RECT  2.16 198.585 246.24 198.855 ;
     RECT  2.16 199.125 246.24 199.395 ;
     RECT  2.16 199.665 246.24 199.935 ;
     RECT  2.16 200.205 246.24 200.475 ;
     RECT  2.16 200.745 246.24 201.015 ;
     RECT  2.16 201.285 246.24 201.555 ;
     RECT  2.16 201.825 246.24 202.095 ;
     RECT  2.16 202.365 246.24 202.635 ;
     RECT  2.16 202.905 246.24 203.175 ;
     RECT  2.16 203.445 246.24 203.715 ;
     RECT  2.16 203.985 246.24 204.255 ;
     RECT  2.16 204.525 246.24 204.795 ;
     RECT  2.16 205.065 246.24 205.335 ;
     RECT  2.16 205.605 246.24 205.875 ;
     RECT  2.16 206.145 246.24 206.415 ;
     RECT  2.16 206.685 246.24 206.955 ;
     RECT  2.16 207.225 246.24 207.495 ;
     RECT  2.16 207.765 246.24 208.035 ;
     RECT  2.16 208.305 246.24 208.575 ;
     RECT  2.16 208.845 246.24 209.115 ;
     RECT  2.16 209.385 246.24 209.655 ;
     RECT  2.16 209.925 246.24 210.195 ;
     RECT  2.16 210.465 246.24 210.735 ;
     RECT  2.16 211.005 246.24 211.275 ;
     RECT  2.16 211.545 246.24 211.815 ;
     RECT  2.16 212.085 246.24 212.355 ;
     RECT  2.16 212.625 246.24 212.895 ;
     RECT  2.16 213.165 246.24 213.435 ;
     RECT  2.16 213.705 246.24 213.975 ;
     RECT  2.16 214.245 246.24 214.515 ;
     RECT  2.16 214.785 246.24 215.055 ;
     RECT  2.16 215.325 246.24 215.595 ;
     RECT  2.16 215.865 246.24 216.135 ;
     RECT  2.16 216.405 246.24 216.675 ;
     RECT  2.16 216.945 246.24 217.215 ;
     RECT  2.16 217.485 246.24 217.755 ;
     RECT  2.16 218.025 246.24 218.295 ;
     RECT  2.16 218.565 246.24 218.835 ;
     RECT  2.16 219.105 246.24 219.375 ;
     RECT  2.16 219.645 246.24 219.915 ;
     RECT  2.16 220.185 246.24 220.455 ;
     RECT  2.16 220.725 246.24 220.995 ;
     RECT  2.16 221.265 246.24 221.535 ;
     RECT  2.16 221.805 246.24 222.075 ;
     RECT  2.16 222.345 246.24 222.615 ;
     RECT  2.16 222.885 246.24 223.155 ;
     RECT  2.16 223.425 246.24 223.695 ;
     RECT  2.16 223.965 246.24 224.235 ;
     RECT  2.16 224.505 246.24 224.775 ;
     RECT  2.16 225.045 246.24 225.315 ;
     RECT  2.16 225.585 246.24 225.855 ;
     RECT  2.16 226.125 246.24 226.395 ;
     RECT  2.16 226.665 246.24 226.935 ;
     RECT  2.16 227.205 246.24 227.475 ;
     RECT  2.16 227.745 246.24 228.015 ;
     RECT  2.16 228.285 246.24 228.555 ;
     RECT  2.16 228.825 246.24 229.095 ;
     RECT  2.16 229.365 246.24 229.635 ;
     RECT  2.16 229.905 246.24 230.175 ;
     RECT  2.16 230.445 246.24 230.715 ;
     RECT  2.16 230.985 246.24 231.255 ;
     RECT  2.16 231.525 246.24 231.795 ;
     RECT  2.16 232.065 246.24 232.335 ;
     RECT  2.16 232.605 246.24 232.875 ;
     RECT  2.16 233.145 246.24 233.415 ;
     RECT  2.16 233.685 246.24 233.955 ;
     RECT  2.16 234.225 246.24 234.495 ;
     RECT  2.16 234.765 246.24 235.035 ;
     RECT  2.16 235.305 246.24 235.575 ;
     RECT  2.16 235.845 246.24 236.115 ;
     RECT  2.16 236.385 246.24 236.655 ;
     RECT  2.16 236.925 246.24 237.195 ;
     RECT  2.16 237.465 246.24 237.735 ;
     RECT  2.16 238.005 246.24 238.275 ;
     RECT  2.16 238.545 246.24 238.815 ;
     RECT  2.16 239.085 246.24 239.355 ;
     RECT  2.16 239.625 246.24 239.895 ;
     RECT  2.16 240.165 246.24 240.435 ;
     RECT  2.16 240.705 246.24 240.975 ;
     RECT  2.16 241.245 246.24 241.515 ;
     RECT  2.16 241.785 246.24 242.055 ;
     RECT  2.16 242.325 246.24 242.595 ;
     RECT  2.16 242.865 246.24 243.135 ;
     RECT  2.16 243.405 246.24 243.675 ;
     RECT  2.16 243.945 246.24 244.215 ;
     RECT  2.16 244.485 246.24 244.755 ;
     RECT  2.16 245.025 246.24 245.295 ;
     RECT  2.16 245.565 246.24 245.835 ;
     RECT  2.16 246.105 246.24 246.375 ;
     RECT  2.16 246.645 246.24 246.915 ;
     RECT  2.16 247.185 246.24 247.455 ;
     RECT  2.16 247.725 246.24 247.995 ;
     RECT  2.16 248.265 246.24 248.535 ;
     RECT  2.16 248.805 246.24 249.075 ;
     RECT  2.16 249.345 246.24 249.615 ;
     RECT  2.16 249.885 246.24 250.155 ;
     RECT  2.16 250.425 246.24 250.695 ;
     RECT  2.16 250.965 246.24 251.235 ;
     RECT  2.16 251.505 246.24 251.775 ;
     RECT  2.16 252.045 246.24 252.315 ;
     RECT  2.16 252.585 246.24 252.855 ;
     RECT  2.16 253.125 246.24 253.395 ;
     RECT  2.16 253.665 246.24 253.935 ;
     RECT  2.16 254.205 246.24 254.475 ;
     RECT  2.16 254.745 246.24 255.015 ;
     RECT  2.16 255.285 246.24 255.555 ;
     RECT  2.16 255.825 246.24 256.095 ;
     RECT  2.16 256.365 246.24 256.635 ;
     RECT  2.16 256.905 246.24 257.175 ;
     RECT  2.16 257.445 246.24 257.715 ;
     RECT  2.16 257.985 246.24 258.255 ;
     RECT  2.16 258.525 246.24 258.795 ;
     RECT  2.16 259.065 246.24 259.335 ;
     RECT  2.16 259.605 246.24 259.875 ;
     RECT  2.16 260.145 246.24 260.415 ;
     RECT  2.16 260.685 246.24 260.955 ;
     RECT  2.16 261.225 246.24 261.495 ;
     RECT  2.16 261.765 246.24 262.035 ;
     RECT  2.16 262.305 246.24 262.575 ;
     RECT  2.16 262.845 246.24 263.115 ;
     RECT  2.16 263.385 246.24 263.655 ;
     RECT  2.16 263.925 246.24 264.195 ;
     RECT  2.16 264.465 246.24 264.735 ;
     RECT  2.16 265.005 246.24 265.275 ;
     RECT  2.16 265.545 246.24 265.815 ;
     RECT  2.16 266.085 246.24 266.355 ;
     RECT  2.16 266.625 246.24 266.895 ;
     RECT  2.16 267.165 246.24 267.435 ;
     RECT  2.16 267.705 246.24 267.975 ;
     RECT  2.16 268.245 246.24 268.515 ;
     RECT  2.16 268.785 246.24 269.055 ;
     RECT  2.16 269.325 246.24 269.595 ;
     RECT  2.16 269.865 246.24 270.135 ;
     RECT  2.16 270.405 246.24 270.675 ;
     RECT  2.16 270.945 246.24 271.215 ;
     RECT  2.16 271.485 246.24 271.755 ;
     RECT  2.16 272.025 246.24 272.295 ;
     RECT  2.16 272.565 246.24 272.835 ;
     RECT  2.16 273.105 246.24 273.375 ;
     RECT  2.16 273.645 246.24 273.915 ;
     RECT  2.16 274.185 246.24 274.455 ;
     RECT  2.16 274.725 246.24 274.995 ;
     RECT  2.16 275.265 246.24 275.535 ;
     RECT  2.16 275.805 246.24 276.075 ;
     RECT  2.16 276.345 246.24 276.615 ;
     RECT  2.16 276.885 246.24 277.155 ;
     RECT  2.16 277.425 246.24 277.695 ;
     RECT  2.16 277.965 246.24 278.235 ;
     RECT  2.16 278.505 246.24 278.775 ;
     RECT  2.16 279.045 246.24 279.315 ;
     RECT  2.16 279.585 246.24 279.855 ;
     RECT  2.16 280.125 246.24 280.395 ;
     RECT  2.16 280.665 246.24 280.935 ;
     RECT  2.16 281.205 246.24 281.475 ;
     RECT  2.16 281.745 246.24 282.015 ;
     RECT  2.16 282.285 246.24 282.555 ;
     RECT  2.16 282.825 246.24 283.095 ;
     RECT  2.16 283.365 246.24 283.635 ;
     RECT  2.16 283.905 246.24 284.175 ;
     RECT  2.16 284.445 246.24 284.715 ;
     RECT  2.16 284.985 246.24 285.255 ;
     RECT  2.16 285.525 246.24 285.795 ;
     RECT  2.16 286.065 246.24 286.335 ;
     RECT  2.16 286.605 246.24 286.875 ;
     RECT  2.16 287.145 246.24 287.415 ;
     RECT  2.16 287.685 246.24 287.955 ;
     RECT  2.16 288.225 246.24 288.495 ;
     RECT  2.16 288.765 246.24 289.035 ;
     RECT  2.16 289.305 246.24 289.575 ;
     RECT  2.16 289.845 246.24 290.115 ;
     RECT  2.16 290.385 246.24 290.655 ;
     RECT  2.16 290.925 246.24 291.195 ;
     RECT  2.16 291.465 246.24 291.735 ;
     RECT  2.16 292.005 246.24 292.275 ;
     RECT  2.16 292.545 246.24 292.815 ;
     RECT  2.16 293.085 246.24 293.355 ;
     RECT  2.16 293.625 246.24 293.895 ;
     RECT  2.16 294.165 246.24 294.435 ;
     RECT  2.16 294.705 246.24 294.975 ;
     RECT  2.16 295.245 246.24 295.515 ;
     RECT  2.16 295.785 246.24 296.055 ;
     RECT  2.16 296.325 246.24 296.595 ;
     RECT  2.16 296.865 246.24 297.135 ;
     RECT  2.16 297.405 246.24 297.675 ;
     RECT  2.16 297.945 246.24 298.215 ;
     RECT  2.16 298.485 246.24 298.755 ;
     RECT  2.16 299.025 246.24 299.295 ;
     RECT  2.16 299.565 246.24 299.835 ;
     RECT  2.16 300.105 246.24 300.375 ;
     RECT  2.16 300.645 246.24 300.915 ;
     RECT  2.16 301.185 246.24 301.455 ;
     RECT  2.16 301.725 246.24 301.995 ;
     RECT  2.16 302.265 246.24 302.535 ;
     RECT  2.16 302.805 246.24 303.075 ;
     RECT  2.16 303.345 246.24 303.615 ;
     RECT  2.16 303.885 246.24 304.155 ;
     RECT  2.16 304.425 246.24 304.695 ;
     RECT  2.16 304.965 246.24 305.235 ;
     RECT  2.16 305.505 246.24 305.775 ;
     RECT  2.16 306.045 246.24 306.315 ;
     RECT  2.16 306.585 246.24 306.855 ;
     RECT  2.16 307.125 246.24 307.395 ;
     RECT  2.16 307.665 246.24 307.935 ;
     RECT  2.16 308.205 246.24 308.475 ;
     RECT  2.16 308.745 246.24 309.015 ;
     RECT  2.16 309.285 246.24 309.555 ;
     RECT  2.16 309.825 246.24 310.095 ;
     RECT  2.16 310.365 246.24 310.635 ;
     RECT  2.16 310.905 246.24 311.175 ;
     RECT  2.16 311.445 246.24 311.715 ;
     RECT  2.16 311.985 246.24 312.255 ;
     RECT  2.16 312.525 246.24 312.795 ;
     RECT  2.16 313.065 246.24 313.335 ;
     RECT  2.16 313.605 246.24 313.875 ;
     RECT  2.16 314.145 246.24 314.415 ;
     RECT  2.16 314.685 246.24 314.955 ;
     RECT  2.16 315.225 246.24 315.495 ;
     RECT  2.16 315.765 246.24 316.035 ;
     RECT  2.16 316.305 246.24 316.575 ;
     RECT  2.16 316.845 246.24 317.115 ;
     RECT  2.16 317.385 246.24 317.655 ;
     RECT  2.16 317.925 246.24 318.195 ;
     RECT  2.16 318.465 246.24 318.735 ;
     RECT  2.16 319.005 246.24 319.275 ;
     RECT  2.16 319.545 246.24 319.815 ;
     RECT  2.16 320.085 246.24 320.355 ;
     RECT  2.16 320.625 246.24 320.895 ;
     RECT  2.16 321.165 246.24 321.435 ;
     RECT  2.16 321.705 246.24 321.975 ;
     RECT  2.16 322.245 246.24 322.515 ;
     RECT  2.16 322.785 246.24 323.055 ;
     RECT  2.16 323.325 246.24 323.595 ;
     RECT  2.16 323.865 246.24 324.135 ;
     RECT  2.16 324.405 246.24 324.675 ;
     RECT  2.16 324.945 246.24 325.215 ;
     RECT  2.16 325.485 246.24 325.755 ;
     RECT  2.16 326.025 246.24 326.295 ;
     RECT  2.16 326.565 246.24 326.835 ;
     RECT  2.16 327.105 246.24 327.375 ;
     RECT  2.16 327.645 246.24 327.915 ;
     RECT  2.16 328.185 246.24 328.455 ;
     RECT  2.16 328.725 246.24 328.995 ;
     RECT  2.16 329.265 246.24 329.535 ;
     RECT  2.16 329.805 246.24 330.075 ;
     RECT  2.16 330.345 246.24 330.615 ;
     RECT  2.16 330.885 246.24 331.155 ;
     RECT  2.16 331.425 246.24 331.695 ;
     RECT  2.16 331.965 246.24 332.235 ;
     RECT  2.16 332.505 246.24 332.775 ;
     RECT  2.16 333.045 246.24 333.315 ;
     RECT  2.16 333.585 246.24 333.855 ;
     RECT  2.16 334.125 246.24 334.395 ;
     RECT  2.16 334.665 246.24 334.935 ;
     RECT  2.16 335.205 246.24 335.475 ;
     RECT  2.16 335.745 246.24 336.015 ;
     RECT  2.16 336.285 246.24 336.555 ;
     RECT  2.16 336.825 246.24 337.095 ;
     RECT  2.16 337.365 246.24 337.635 ;
     RECT  2.16 337.905 246.24 338.175 ;
     RECT  2.16 338.445 246.24 338.715 ;
     RECT  2.16 338.985 246.24 339.255 ;
     RECT  2.16 339.525 246.24 339.795 ;
     RECT  2.16 340.065 246.24 340.335 ;
     RECT  2.16 340.605 246.24 340.875 ;
     RECT  2.16 341.145 246.24 341.415 ;
     RECT  2.16 341.685 246.24 341.955 ;
     RECT  2.16 342.225 246.24 342.495 ;
     RECT  2.16 342.765 246.24 343.035 ;
     RECT  2.16 343.305 246.24 343.575 ;
     RECT  2.16 343.845 246.24 344.115 ;
     RECT  2.16 344.385 246.24 344.655 ;
     RECT  2.16 344.925 246.24 345.195 ;
     RECT  2.16 345.465 246.24 345.735 ;
     RECT  2.16 346.005 246.24 346.275 ;
     RECT  2.16 346.545 246.24 346.815 ;
     RECT  2.16 347.085 246.24 347.355 ;
     RECT  2.16 347.625 246.24 347.895 ;
     RECT  2.16 348.165 246.24 348.435 ;
     RECT  2.16 348.705 246.24 348.975 ;
     RECT  2.16 349.245 246.24 349.515 ;
     RECT  2.16 349.785 246.24 350.055 ;
     RECT  2.16 350.325 246.24 350.595 ;
     RECT  2.16 350.865 246.24 351.135 ;
     RECT  2.16 351.405 246.24 351.675 ;
     RECT  2.16 351.945 246.24 352.215 ;
     RECT  2.16 352.485 246.24 352.755 ;
     RECT  2.16 353.025 246.24 353.295 ;
     RECT  2.16 353.565 246.24 353.835 ;
     RECT  2.16 354.105 246.24 354.375 ;
     RECT  2.16 354.645 246.24 354.915 ;
     RECT  2.16 355.185 246.24 355.455 ;
     RECT  2.16 355.725 246.24 355.995 ;
     RECT  2.16 356.265 246.24 356.535 ;
     RECT  2.16 356.805 246.24 357.075 ;
     RECT  2.16 357.345 246.24 357.615 ;
     RECT  2.16 357.885 246.24 358.155 ;
     RECT  2.16 358.425 246.24 358.695 ;
     RECT  2.16 358.965 246.24 359.235 ;
     RECT  2.16 359.505 246.24 359.775 ;
     RECT  2.16 360.045 246.24 360.315 ;
     RECT  2.16 360.585 246.24 360.855 ;
     RECT  2.16 361.125 246.24 361.395 ;
     RECT  2.16 361.665 246.24 361.935 ;
     RECT  2.16 362.205 246.24 362.475 ;
     RECT  2.16 362.745 246.24 363.015 ;
     RECT  2.16 363.285 246.24 363.555 ;
     RECT  2.16 363.825 246.24 364.095 ;
     RECT  2.16 364.365 246.24 364.635 ;
     RECT  2.16 364.905 246.24 365.175 ;
     RECT  2.16 365.445 246.24 365.715 ;
     RECT  2.16 365.985 246.24 366.255 ;
     RECT  2.16 366.525 246.24 366.795 ;
     RECT  2.16 367.065 246.24 367.335 ;
     RECT  2.16 367.605 246.24 367.875 ;
     RECT  2.16 368.145 246.24 368.415 ;
     RECT  2.16 368.685 246.24 368.955 ;
     RECT  2.16 369.225 246.24 369.36 ;
    LAYER RVTP ;
     RECT  2.16 2.295 246.24 2.565 ;
     RECT  2.16 2.835 246.24 3.105 ;
     RECT  2.16 3.375 246.24 3.645 ;
     RECT  2.16 3.915 246.24 4.185 ;
     RECT  2.16 4.455 246.24 4.725 ;
     RECT  2.16 4.995 246.24 5.265 ;
     RECT  2.16 5.535 246.24 5.805 ;
     RECT  2.16 6.075 246.24 6.345 ;
     RECT  2.16 6.615 246.24 6.885 ;
     RECT  2.16 7.155 246.24 7.425 ;
     RECT  2.16 7.695 246.24 7.965 ;
     RECT  2.16 8.235 246.24 8.505 ;
     RECT  2.16 8.775 246.24 9.045 ;
     RECT  2.16 9.315 246.24 9.585 ;
     RECT  2.16 9.855 246.24 10.125 ;
     RECT  2.16 10.395 246.24 10.665 ;
     RECT  2.16 10.935 246.24 11.205 ;
     RECT  2.16 11.475 246.24 11.745 ;
     RECT  2.16 12.015 246.24 12.285 ;
     RECT  2.16 12.555 246.24 12.825 ;
     RECT  2.16 13.095 246.24 13.365 ;
     RECT  2.16 13.635 246.24 13.905 ;
     RECT  2.16 14.175 246.24 14.445 ;
     RECT  2.16 14.715 246.24 14.985 ;
     RECT  2.16 15.255 246.24 15.525 ;
     RECT  2.16 15.795 246.24 16.065 ;
     RECT  2.16 16.335 246.24 16.605 ;
     RECT  2.16 16.875 246.24 17.145 ;
     RECT  2.16 17.415 246.24 17.685 ;
     RECT  2.16 17.955 246.24 18.225 ;
     RECT  2.16 18.495 246.24 18.765 ;
     RECT  2.16 19.035 246.24 19.305 ;
     RECT  2.16 19.575 246.24 19.845 ;
     RECT  2.16 20.115 246.24 20.385 ;
     RECT  2.16 20.655 246.24 20.925 ;
     RECT  2.16 21.195 246.24 21.465 ;
     RECT  2.16 21.735 246.24 22.005 ;
     RECT  2.16 22.275 246.24 22.545 ;
     RECT  2.16 22.815 246.24 23.085 ;
     RECT  2.16 23.355 246.24 23.625 ;
     RECT  2.16 23.895 246.24 24.165 ;
     RECT  2.16 24.435 246.24 24.705 ;
     RECT  2.16 24.975 246.24 25.245 ;
     RECT  2.16 25.515 246.24 25.785 ;
     RECT  2.16 26.055 246.24 26.325 ;
     RECT  2.16 26.595 246.24 26.865 ;
     RECT  2.16 27.135 246.24 27.405 ;
     RECT  2.16 27.675 246.24 27.945 ;
     RECT  2.16 28.215 246.24 28.485 ;
     RECT  2.16 28.755 246.24 29.025 ;
     RECT  2.16 29.295 246.24 29.565 ;
     RECT  2.16 29.835 246.24 30.105 ;
     RECT  2.16 30.375 246.24 30.645 ;
     RECT  2.16 30.915 246.24 31.185 ;
     RECT  2.16 31.455 246.24 31.725 ;
     RECT  2.16 31.995 246.24 32.265 ;
     RECT  2.16 32.535 246.24 32.805 ;
     RECT  2.16 33.075 246.24 33.345 ;
     RECT  2.16 33.615 246.24 33.885 ;
     RECT  2.16 34.155 246.24 34.425 ;
     RECT  2.16 34.695 246.24 34.965 ;
     RECT  2.16 35.235 246.24 35.505 ;
     RECT  2.16 35.775 246.24 36.045 ;
     RECT  2.16 36.315 246.24 36.585 ;
     RECT  2.16 36.855 246.24 37.125 ;
     RECT  2.16 37.395 246.24 37.665 ;
     RECT  2.16 37.935 246.24 38.205 ;
     RECT  2.16 38.475 246.24 38.745 ;
     RECT  2.16 39.015 246.24 39.285 ;
     RECT  2.16 39.555 246.24 39.825 ;
     RECT  2.16 40.095 246.24 40.365 ;
     RECT  2.16 40.635 246.24 40.905 ;
     RECT  2.16 41.175 246.24 41.445 ;
     RECT  2.16 41.715 246.24 41.985 ;
     RECT  2.16 42.255 246.24 42.525 ;
     RECT  2.16 42.795 246.24 43.065 ;
     RECT  2.16 43.335 246.24 43.605 ;
     RECT  2.16 43.875 246.24 44.145 ;
     RECT  2.16 44.415 246.24 44.685 ;
     RECT  2.16 44.955 246.24 45.225 ;
     RECT  2.16 45.495 246.24 45.765 ;
     RECT  2.16 46.035 246.24 46.305 ;
     RECT  2.16 46.575 246.24 46.845 ;
     RECT  2.16 47.115 246.24 47.385 ;
     RECT  2.16 47.655 246.24 47.925 ;
     RECT  2.16 48.195 246.24 48.465 ;
     RECT  2.16 48.735 246.24 49.005 ;
     RECT  2.16 49.275 246.24 49.545 ;
     RECT  2.16 49.815 246.24 50.085 ;
     RECT  2.16 50.355 246.24 50.625 ;
     RECT  2.16 50.895 246.24 51.165 ;
     RECT  2.16 51.435 246.24 51.705 ;
     RECT  2.16 51.975 246.24 52.245 ;
     RECT  2.16 52.515 246.24 52.785 ;
     RECT  2.16 53.055 246.24 53.325 ;
     RECT  2.16 53.595 246.24 53.865 ;
     RECT  2.16 54.135 246.24 54.405 ;
     RECT  2.16 54.675 246.24 54.945 ;
     RECT  2.16 55.215 246.24 55.485 ;
     RECT  2.16 55.755 246.24 56.025 ;
     RECT  2.16 56.295 246.24 56.565 ;
     RECT  2.16 56.835 246.24 57.105 ;
     RECT  2.16 57.375 246.24 57.645 ;
     RECT  2.16 57.915 246.24 58.185 ;
     RECT  2.16 58.455 246.24 58.725 ;
     RECT  2.16 58.995 246.24 59.265 ;
     RECT  2.16 59.535 246.24 59.805 ;
     RECT  2.16 60.075 246.24 60.345 ;
     RECT  2.16 60.615 246.24 60.885 ;
     RECT  2.16 61.155 246.24 61.425 ;
     RECT  2.16 61.695 246.24 61.965 ;
     RECT  2.16 62.235 246.24 62.505 ;
     RECT  2.16 62.775 246.24 63.045 ;
     RECT  2.16 63.315 246.24 63.585 ;
     RECT  2.16 63.855 246.24 64.125 ;
     RECT  2.16 64.395 246.24 64.665 ;
     RECT  2.16 64.935 246.24 65.205 ;
     RECT  2.16 65.475 246.24 65.745 ;
     RECT  2.16 66.015 246.24 66.285 ;
     RECT  2.16 66.555 246.24 66.825 ;
     RECT  2.16 67.095 246.24 67.365 ;
     RECT  2.16 67.635 246.24 67.905 ;
     RECT  2.16 68.175 246.24 68.445 ;
     RECT  2.16 68.715 246.24 68.985 ;
     RECT  2.16 69.255 246.24 69.525 ;
     RECT  2.16 69.795 246.24 70.065 ;
     RECT  2.16 70.335 246.24 70.605 ;
     RECT  2.16 70.875 246.24 71.145 ;
     RECT  2.16 71.415 246.24 71.685 ;
     RECT  2.16 71.955 246.24 72.225 ;
     RECT  2.16 72.495 246.24 72.765 ;
     RECT  2.16 73.035 246.24 73.305 ;
     RECT  2.16 73.575 246.24 73.845 ;
     RECT  2.16 74.115 246.24 74.385 ;
     RECT  2.16 74.655 246.24 74.925 ;
     RECT  2.16 75.195 246.24 75.465 ;
     RECT  2.16 75.735 246.24 76.005 ;
     RECT  2.16 76.275 246.24 76.545 ;
     RECT  2.16 76.815 246.24 77.085 ;
     RECT  2.16 77.355 246.24 77.625 ;
     RECT  2.16 77.895 246.24 78.165 ;
     RECT  2.16 78.435 246.24 78.705 ;
     RECT  2.16 78.975 246.24 79.245 ;
     RECT  2.16 79.515 246.24 79.785 ;
     RECT  2.16 80.055 246.24 80.325 ;
     RECT  2.16 80.595 246.24 80.865 ;
     RECT  2.16 81.135 246.24 81.405 ;
     RECT  2.16 81.675 246.24 81.945 ;
     RECT  2.16 82.215 246.24 82.485 ;
     RECT  2.16 82.755 246.24 83.025 ;
     RECT  2.16 83.295 246.24 83.565 ;
     RECT  2.16 83.835 246.24 84.105 ;
     RECT  2.16 84.375 246.24 84.645 ;
     RECT  2.16 84.915 246.24 85.185 ;
     RECT  2.16 85.455 246.24 85.725 ;
     RECT  2.16 85.995 246.24 86.265 ;
     RECT  2.16 86.535 246.24 86.805 ;
     RECT  2.16 87.075 246.24 87.345 ;
     RECT  2.16 87.615 246.24 87.885 ;
     RECT  2.16 88.155 246.24 88.425 ;
     RECT  2.16 88.695 246.24 88.965 ;
     RECT  2.16 89.235 246.24 89.505 ;
     RECT  2.16 89.775 246.24 90.045 ;
     RECT  2.16 90.315 246.24 90.585 ;
     RECT  2.16 90.855 246.24 91.125 ;
     RECT  2.16 91.395 246.24 91.665 ;
     RECT  2.16 91.935 246.24 92.205 ;
     RECT  2.16 92.475 246.24 92.745 ;
     RECT  2.16 93.015 246.24 93.285 ;
     RECT  2.16 93.555 246.24 93.825 ;
     RECT  2.16 94.095 246.24 94.365 ;
     RECT  2.16 94.635 246.24 94.905 ;
     RECT  2.16 95.175 246.24 95.445 ;
     RECT  2.16 95.715 246.24 95.985 ;
     RECT  2.16 96.255 246.24 96.525 ;
     RECT  2.16 96.795 246.24 97.065 ;
     RECT  2.16 97.335 246.24 97.605 ;
     RECT  2.16 97.875 246.24 98.145 ;
     RECT  2.16 98.415 246.24 98.685 ;
     RECT  2.16 98.955 246.24 99.225 ;
     RECT  2.16 99.495 246.24 99.765 ;
     RECT  2.16 100.035 246.24 100.305 ;
     RECT  2.16 100.575 246.24 100.845 ;
     RECT  2.16 101.115 246.24 101.385 ;
     RECT  2.16 101.655 246.24 101.925 ;
     RECT  2.16 102.195 246.24 102.465 ;
     RECT  2.16 102.735 246.24 103.005 ;
     RECT  2.16 103.275 246.24 103.545 ;
     RECT  2.16 103.815 246.24 104.085 ;
     RECT  2.16 104.355 246.24 104.625 ;
     RECT  2.16 104.895 246.24 105.165 ;
     RECT  2.16 105.435 246.24 105.705 ;
     RECT  2.16 105.975 246.24 106.245 ;
     RECT  2.16 106.515 246.24 106.785 ;
     RECT  2.16 107.055 246.24 107.325 ;
     RECT  2.16 107.595 246.24 107.865 ;
     RECT  2.16 108.135 246.24 108.405 ;
     RECT  2.16 108.675 246.24 108.945 ;
     RECT  2.16 109.215 246.24 109.485 ;
     RECT  2.16 109.755 246.24 110.025 ;
     RECT  2.16 110.295 246.24 110.565 ;
     RECT  2.16 110.835 246.24 111.105 ;
     RECT  2.16 111.375 246.24 111.645 ;
     RECT  2.16 111.915 246.24 112.185 ;
     RECT  2.16 112.455 246.24 112.725 ;
     RECT  2.16 112.995 246.24 113.265 ;
     RECT  2.16 113.535 246.24 113.805 ;
     RECT  2.16 114.075 246.24 114.345 ;
     RECT  2.16 114.615 246.24 114.885 ;
     RECT  2.16 115.155 246.24 115.425 ;
     RECT  2.16 115.695 246.24 115.965 ;
     RECT  2.16 116.235 246.24 116.505 ;
     RECT  2.16 116.775 246.24 117.045 ;
     RECT  2.16 117.315 246.24 117.585 ;
     RECT  2.16 117.855 246.24 118.125 ;
     RECT  2.16 118.395 246.24 118.665 ;
     RECT  2.16 118.935 246.24 119.205 ;
     RECT  2.16 119.475 246.24 119.745 ;
     RECT  2.16 120.015 246.24 120.285 ;
     RECT  2.16 120.555 246.24 120.825 ;
     RECT  2.16 121.095 246.24 121.365 ;
     RECT  2.16 121.635 246.24 121.905 ;
     RECT  2.16 122.175 246.24 122.445 ;
     RECT  2.16 122.715 246.24 122.985 ;
     RECT  2.16 123.255 246.24 123.525 ;
     RECT  2.16 123.795 246.24 124.065 ;
     RECT  2.16 124.335 246.24 124.605 ;
     RECT  2.16 124.875 246.24 125.145 ;
     RECT  2.16 125.415 246.24 125.685 ;
     RECT  2.16 125.955 246.24 126.225 ;
     RECT  2.16 126.495 246.24 126.765 ;
     RECT  2.16 127.035 246.24 127.305 ;
     RECT  2.16 127.575 246.24 127.845 ;
     RECT  2.16 128.115 246.24 128.385 ;
     RECT  2.16 128.655 246.24 128.925 ;
     RECT  2.16 129.195 246.24 129.465 ;
     RECT  2.16 129.735 246.24 130.005 ;
     RECT  2.16 130.275 246.24 130.545 ;
     RECT  2.16 130.815 246.24 131.085 ;
     RECT  2.16 131.355 246.24 131.625 ;
     RECT  2.16 131.895 246.24 132.165 ;
     RECT  2.16 132.435 246.24 132.705 ;
     RECT  2.16 132.975 246.24 133.245 ;
     RECT  2.16 133.515 246.24 133.785 ;
     RECT  2.16 134.055 246.24 134.325 ;
     RECT  2.16 134.595 246.24 134.865 ;
     RECT  2.16 135.135 246.24 135.405 ;
     RECT  2.16 135.675 246.24 135.945 ;
     RECT  2.16 136.215 246.24 136.485 ;
     RECT  2.16 136.755 246.24 137.025 ;
     RECT  2.16 137.295 246.24 137.565 ;
     RECT  2.16 137.835 246.24 138.105 ;
     RECT  2.16 138.375 246.24 138.645 ;
     RECT  2.16 138.915 246.24 139.185 ;
     RECT  2.16 139.455 246.24 139.725 ;
     RECT  2.16 139.995 246.24 140.265 ;
     RECT  2.16 140.535 246.24 140.805 ;
     RECT  2.16 141.075 246.24 141.345 ;
     RECT  2.16 141.615 246.24 141.885 ;
     RECT  2.16 142.155 246.24 142.425 ;
     RECT  2.16 142.695 246.24 142.965 ;
     RECT  2.16 143.235 246.24 143.505 ;
     RECT  2.16 143.775 246.24 144.045 ;
     RECT  2.16 144.315 246.24 144.585 ;
     RECT  2.16 144.855 246.24 145.125 ;
     RECT  2.16 145.395 246.24 145.665 ;
     RECT  2.16 145.935 246.24 146.205 ;
     RECT  2.16 146.475 246.24 146.745 ;
     RECT  2.16 147.015 246.24 147.285 ;
     RECT  2.16 147.555 246.24 147.825 ;
     RECT  2.16 148.095 246.24 148.365 ;
     RECT  2.16 148.635 246.24 148.905 ;
     RECT  2.16 149.175 246.24 149.445 ;
     RECT  2.16 149.715 246.24 149.985 ;
     RECT  2.16 150.255 246.24 150.525 ;
     RECT  2.16 150.795 246.24 151.065 ;
     RECT  2.16 151.335 246.24 151.605 ;
     RECT  2.16 151.875 246.24 152.145 ;
     RECT  2.16 152.415 246.24 152.685 ;
     RECT  2.16 152.955 246.24 153.225 ;
     RECT  2.16 153.495 246.24 153.765 ;
     RECT  2.16 154.035 246.24 154.305 ;
     RECT  2.16 154.575 246.24 154.845 ;
     RECT  2.16 155.115 246.24 155.385 ;
     RECT  2.16 155.655 246.24 155.925 ;
     RECT  2.16 156.195 246.24 156.465 ;
     RECT  2.16 156.735 246.24 157.005 ;
     RECT  2.16 157.275 246.24 157.545 ;
     RECT  2.16 157.815 246.24 158.085 ;
     RECT  2.16 158.355 246.24 158.625 ;
     RECT  2.16 158.895 246.24 159.165 ;
     RECT  2.16 159.435 246.24 159.705 ;
     RECT  2.16 159.975 246.24 160.245 ;
     RECT  2.16 160.515 246.24 160.785 ;
     RECT  2.16 161.055 246.24 161.325 ;
     RECT  2.16 161.595 246.24 161.865 ;
     RECT  2.16 162.135 246.24 162.405 ;
     RECT  2.16 162.675 246.24 162.945 ;
     RECT  2.16 163.215 246.24 163.485 ;
     RECT  2.16 163.755 246.24 164.025 ;
     RECT  2.16 164.295 246.24 164.565 ;
     RECT  2.16 164.835 246.24 165.105 ;
     RECT  2.16 165.375 246.24 165.645 ;
     RECT  2.16 165.915 246.24 166.185 ;
     RECT  2.16 166.455 246.24 166.725 ;
     RECT  2.16 166.995 246.24 167.265 ;
     RECT  2.16 167.535 246.24 167.805 ;
     RECT  2.16 168.075 246.24 168.345 ;
     RECT  2.16 168.615 246.24 168.885 ;
     RECT  2.16 169.155 246.24 169.425 ;
     RECT  2.16 169.695 246.24 169.965 ;
     RECT  2.16 170.235 246.24 170.505 ;
     RECT  2.16 170.775 246.24 171.045 ;
     RECT  2.16 171.315 246.24 171.585 ;
     RECT  2.16 171.855 246.24 172.125 ;
     RECT  2.16 172.395 246.24 172.665 ;
     RECT  2.16 172.935 246.24 173.205 ;
     RECT  2.16 173.475 246.24 173.745 ;
     RECT  2.16 174.015 246.24 174.285 ;
     RECT  2.16 174.555 246.24 174.825 ;
     RECT  2.16 175.095 246.24 175.365 ;
     RECT  2.16 175.635 246.24 175.905 ;
     RECT  2.16 176.175 246.24 176.445 ;
     RECT  2.16 176.715 246.24 176.985 ;
     RECT  2.16 177.255 246.24 177.525 ;
     RECT  2.16 177.795 246.24 178.065 ;
     RECT  2.16 178.335 246.24 178.605 ;
     RECT  2.16 178.875 246.24 179.145 ;
     RECT  2.16 179.415 246.24 179.685 ;
     RECT  2.16 179.955 246.24 180.225 ;
     RECT  2.16 180.495 246.24 180.765 ;
     RECT  2.16 181.035 246.24 181.305 ;
     RECT  2.16 181.575 246.24 181.845 ;
     RECT  2.16 182.115 246.24 182.385 ;
     RECT  2.16 182.655 246.24 182.925 ;
     RECT  2.16 183.195 246.24 183.465 ;
     RECT  2.16 183.735 246.24 184.005 ;
     RECT  2.16 184.275 246.24 184.545 ;
     RECT  2.16 184.815 246.24 185.085 ;
     RECT  2.16 185.355 246.24 185.625 ;
     RECT  2.16 185.895 246.24 186.165 ;
     RECT  2.16 186.435 246.24 186.705 ;
     RECT  2.16 186.975 246.24 187.245 ;
     RECT  2.16 187.515 246.24 187.785 ;
     RECT  2.16 188.055 246.24 188.325 ;
     RECT  2.16 188.595 246.24 188.865 ;
     RECT  2.16 189.135 246.24 189.405 ;
     RECT  2.16 189.675 246.24 189.945 ;
     RECT  2.16 190.215 246.24 190.485 ;
     RECT  2.16 190.755 246.24 191.025 ;
     RECT  2.16 191.295 246.24 191.565 ;
     RECT  2.16 191.835 246.24 192.105 ;
     RECT  2.16 192.375 246.24 192.645 ;
     RECT  2.16 192.915 246.24 193.185 ;
     RECT  2.16 193.455 246.24 193.725 ;
     RECT  2.16 193.995 246.24 194.265 ;
     RECT  2.16 194.535 246.24 194.805 ;
     RECT  2.16 195.075 246.24 195.345 ;
     RECT  2.16 195.615 246.24 195.885 ;
     RECT  2.16 196.155 246.24 196.425 ;
     RECT  2.16 196.695 246.24 196.965 ;
     RECT  2.16 197.235 246.24 197.505 ;
     RECT  2.16 197.775 246.24 198.045 ;
     RECT  2.16 198.315 246.24 198.585 ;
     RECT  2.16 198.855 246.24 199.125 ;
     RECT  2.16 199.395 246.24 199.665 ;
     RECT  2.16 199.935 246.24 200.205 ;
     RECT  2.16 200.475 246.24 200.745 ;
     RECT  2.16 201.015 246.24 201.285 ;
     RECT  2.16 201.555 246.24 201.825 ;
     RECT  2.16 202.095 246.24 202.365 ;
     RECT  2.16 202.635 246.24 202.905 ;
     RECT  2.16 203.175 246.24 203.445 ;
     RECT  2.16 203.715 246.24 203.985 ;
     RECT  2.16 204.255 246.24 204.525 ;
     RECT  2.16 204.795 246.24 205.065 ;
     RECT  2.16 205.335 246.24 205.605 ;
     RECT  2.16 205.875 246.24 206.145 ;
     RECT  2.16 206.415 246.24 206.685 ;
     RECT  2.16 206.955 246.24 207.225 ;
     RECT  2.16 207.495 246.24 207.765 ;
     RECT  2.16 208.035 246.24 208.305 ;
     RECT  2.16 208.575 246.24 208.845 ;
     RECT  2.16 209.115 246.24 209.385 ;
     RECT  2.16 209.655 246.24 209.925 ;
     RECT  2.16 210.195 246.24 210.465 ;
     RECT  2.16 210.735 246.24 211.005 ;
     RECT  2.16 211.275 246.24 211.545 ;
     RECT  2.16 211.815 246.24 212.085 ;
     RECT  2.16 212.355 246.24 212.625 ;
     RECT  2.16 212.895 246.24 213.165 ;
     RECT  2.16 213.435 246.24 213.705 ;
     RECT  2.16 213.975 246.24 214.245 ;
     RECT  2.16 214.515 246.24 214.785 ;
     RECT  2.16 215.055 246.24 215.325 ;
     RECT  2.16 215.595 246.24 215.865 ;
     RECT  2.16 216.135 246.24 216.405 ;
     RECT  2.16 216.675 246.24 216.945 ;
     RECT  2.16 217.215 246.24 217.485 ;
     RECT  2.16 217.755 246.24 218.025 ;
     RECT  2.16 218.295 246.24 218.565 ;
     RECT  2.16 218.835 246.24 219.105 ;
     RECT  2.16 219.375 246.24 219.645 ;
     RECT  2.16 219.915 246.24 220.185 ;
     RECT  2.16 220.455 246.24 220.725 ;
     RECT  2.16 220.995 246.24 221.265 ;
     RECT  2.16 221.535 246.24 221.805 ;
     RECT  2.16 222.075 246.24 222.345 ;
     RECT  2.16 222.615 246.24 222.885 ;
     RECT  2.16 223.155 246.24 223.425 ;
     RECT  2.16 223.695 246.24 223.965 ;
     RECT  2.16 224.235 246.24 224.505 ;
     RECT  2.16 224.775 246.24 225.045 ;
     RECT  2.16 225.315 246.24 225.585 ;
     RECT  2.16 225.855 246.24 226.125 ;
     RECT  2.16 226.395 246.24 226.665 ;
     RECT  2.16 226.935 246.24 227.205 ;
     RECT  2.16 227.475 246.24 227.745 ;
     RECT  2.16 228.015 246.24 228.285 ;
     RECT  2.16 228.555 246.24 228.825 ;
     RECT  2.16 229.095 246.24 229.365 ;
     RECT  2.16 229.635 246.24 229.905 ;
     RECT  2.16 230.175 246.24 230.445 ;
     RECT  2.16 230.715 246.24 230.985 ;
     RECT  2.16 231.255 246.24 231.525 ;
     RECT  2.16 231.795 246.24 232.065 ;
     RECT  2.16 232.335 246.24 232.605 ;
     RECT  2.16 232.875 246.24 233.145 ;
     RECT  2.16 233.415 246.24 233.685 ;
     RECT  2.16 233.955 246.24 234.225 ;
     RECT  2.16 234.495 246.24 234.765 ;
     RECT  2.16 235.035 246.24 235.305 ;
     RECT  2.16 235.575 246.24 235.845 ;
     RECT  2.16 236.115 246.24 236.385 ;
     RECT  2.16 236.655 246.24 236.925 ;
     RECT  2.16 237.195 246.24 237.465 ;
     RECT  2.16 237.735 246.24 238.005 ;
     RECT  2.16 238.275 246.24 238.545 ;
     RECT  2.16 238.815 246.24 239.085 ;
     RECT  2.16 239.355 246.24 239.625 ;
     RECT  2.16 239.895 246.24 240.165 ;
     RECT  2.16 240.435 246.24 240.705 ;
     RECT  2.16 240.975 246.24 241.245 ;
     RECT  2.16 241.515 246.24 241.785 ;
     RECT  2.16 242.055 246.24 242.325 ;
     RECT  2.16 242.595 246.24 242.865 ;
     RECT  2.16 243.135 246.24 243.405 ;
     RECT  2.16 243.675 246.24 243.945 ;
     RECT  2.16 244.215 246.24 244.485 ;
     RECT  2.16 244.755 246.24 245.025 ;
     RECT  2.16 245.295 246.24 245.565 ;
     RECT  2.16 245.835 246.24 246.105 ;
     RECT  2.16 246.375 246.24 246.645 ;
     RECT  2.16 246.915 246.24 247.185 ;
     RECT  2.16 247.455 246.24 247.725 ;
     RECT  2.16 247.995 246.24 248.265 ;
     RECT  2.16 248.535 246.24 248.805 ;
     RECT  2.16 249.075 246.24 249.345 ;
     RECT  2.16 249.615 246.24 249.885 ;
     RECT  2.16 250.155 246.24 250.425 ;
     RECT  2.16 250.695 246.24 250.965 ;
     RECT  2.16 251.235 246.24 251.505 ;
     RECT  2.16 251.775 246.24 252.045 ;
     RECT  2.16 252.315 246.24 252.585 ;
     RECT  2.16 252.855 246.24 253.125 ;
     RECT  2.16 253.395 246.24 253.665 ;
     RECT  2.16 253.935 246.24 254.205 ;
     RECT  2.16 254.475 246.24 254.745 ;
     RECT  2.16 255.015 246.24 255.285 ;
     RECT  2.16 255.555 246.24 255.825 ;
     RECT  2.16 256.095 246.24 256.365 ;
     RECT  2.16 256.635 246.24 256.905 ;
     RECT  2.16 257.175 246.24 257.445 ;
     RECT  2.16 257.715 246.24 257.985 ;
     RECT  2.16 258.255 246.24 258.525 ;
     RECT  2.16 258.795 246.24 259.065 ;
     RECT  2.16 259.335 246.24 259.605 ;
     RECT  2.16 259.875 246.24 260.145 ;
     RECT  2.16 260.415 246.24 260.685 ;
     RECT  2.16 260.955 246.24 261.225 ;
     RECT  2.16 261.495 246.24 261.765 ;
     RECT  2.16 262.035 246.24 262.305 ;
     RECT  2.16 262.575 246.24 262.845 ;
     RECT  2.16 263.115 246.24 263.385 ;
     RECT  2.16 263.655 246.24 263.925 ;
     RECT  2.16 264.195 246.24 264.465 ;
     RECT  2.16 264.735 246.24 265.005 ;
     RECT  2.16 265.275 246.24 265.545 ;
     RECT  2.16 265.815 246.24 266.085 ;
     RECT  2.16 266.355 246.24 266.625 ;
     RECT  2.16 266.895 246.24 267.165 ;
     RECT  2.16 267.435 246.24 267.705 ;
     RECT  2.16 267.975 246.24 268.245 ;
     RECT  2.16 268.515 246.24 268.785 ;
     RECT  2.16 269.055 246.24 269.325 ;
     RECT  2.16 269.595 246.24 269.865 ;
     RECT  2.16 270.135 246.24 270.405 ;
     RECT  2.16 270.675 246.24 270.945 ;
     RECT  2.16 271.215 246.24 271.485 ;
     RECT  2.16 271.755 246.24 272.025 ;
     RECT  2.16 272.295 246.24 272.565 ;
     RECT  2.16 272.835 246.24 273.105 ;
     RECT  2.16 273.375 246.24 273.645 ;
     RECT  2.16 273.915 246.24 274.185 ;
     RECT  2.16 274.455 246.24 274.725 ;
     RECT  2.16 274.995 246.24 275.265 ;
     RECT  2.16 275.535 246.24 275.805 ;
     RECT  2.16 276.075 246.24 276.345 ;
     RECT  2.16 276.615 246.24 276.885 ;
     RECT  2.16 277.155 246.24 277.425 ;
     RECT  2.16 277.695 246.24 277.965 ;
     RECT  2.16 278.235 246.24 278.505 ;
     RECT  2.16 278.775 246.24 279.045 ;
     RECT  2.16 279.315 246.24 279.585 ;
     RECT  2.16 279.855 246.24 280.125 ;
     RECT  2.16 280.395 246.24 280.665 ;
     RECT  2.16 280.935 246.24 281.205 ;
     RECT  2.16 281.475 246.24 281.745 ;
     RECT  2.16 282.015 246.24 282.285 ;
     RECT  2.16 282.555 246.24 282.825 ;
     RECT  2.16 283.095 246.24 283.365 ;
     RECT  2.16 283.635 246.24 283.905 ;
     RECT  2.16 284.175 246.24 284.445 ;
     RECT  2.16 284.715 246.24 284.985 ;
     RECT  2.16 285.255 246.24 285.525 ;
     RECT  2.16 285.795 246.24 286.065 ;
     RECT  2.16 286.335 246.24 286.605 ;
     RECT  2.16 286.875 246.24 287.145 ;
     RECT  2.16 287.415 246.24 287.685 ;
     RECT  2.16 287.955 246.24 288.225 ;
     RECT  2.16 288.495 246.24 288.765 ;
     RECT  2.16 289.035 246.24 289.305 ;
     RECT  2.16 289.575 246.24 289.845 ;
     RECT  2.16 290.115 246.24 290.385 ;
     RECT  2.16 290.655 246.24 290.925 ;
     RECT  2.16 291.195 246.24 291.465 ;
     RECT  2.16 291.735 246.24 292.005 ;
     RECT  2.16 292.275 246.24 292.545 ;
     RECT  2.16 292.815 246.24 293.085 ;
     RECT  2.16 293.355 246.24 293.625 ;
     RECT  2.16 293.895 246.24 294.165 ;
     RECT  2.16 294.435 246.24 294.705 ;
     RECT  2.16 294.975 246.24 295.245 ;
     RECT  2.16 295.515 246.24 295.785 ;
     RECT  2.16 296.055 246.24 296.325 ;
     RECT  2.16 296.595 246.24 296.865 ;
     RECT  2.16 297.135 246.24 297.405 ;
     RECT  2.16 297.675 246.24 297.945 ;
     RECT  2.16 298.215 246.24 298.485 ;
     RECT  2.16 298.755 246.24 299.025 ;
     RECT  2.16 299.295 246.24 299.565 ;
     RECT  2.16 299.835 246.24 300.105 ;
     RECT  2.16 300.375 246.24 300.645 ;
     RECT  2.16 300.915 246.24 301.185 ;
     RECT  2.16 301.455 246.24 301.725 ;
     RECT  2.16 301.995 246.24 302.265 ;
     RECT  2.16 302.535 246.24 302.805 ;
     RECT  2.16 303.075 246.24 303.345 ;
     RECT  2.16 303.615 246.24 303.885 ;
     RECT  2.16 304.155 246.24 304.425 ;
     RECT  2.16 304.695 246.24 304.965 ;
     RECT  2.16 305.235 246.24 305.505 ;
     RECT  2.16 305.775 246.24 306.045 ;
     RECT  2.16 306.315 246.24 306.585 ;
     RECT  2.16 306.855 246.24 307.125 ;
     RECT  2.16 307.395 246.24 307.665 ;
     RECT  2.16 307.935 246.24 308.205 ;
     RECT  2.16 308.475 246.24 308.745 ;
     RECT  2.16 309.015 246.24 309.285 ;
     RECT  2.16 309.555 246.24 309.825 ;
     RECT  2.16 310.095 246.24 310.365 ;
     RECT  2.16 310.635 246.24 310.905 ;
     RECT  2.16 311.175 246.24 311.445 ;
     RECT  2.16 311.715 246.24 311.985 ;
     RECT  2.16 312.255 246.24 312.525 ;
     RECT  2.16 312.795 246.24 313.065 ;
     RECT  2.16 313.335 246.24 313.605 ;
     RECT  2.16 313.875 246.24 314.145 ;
     RECT  2.16 314.415 246.24 314.685 ;
     RECT  2.16 314.955 246.24 315.225 ;
     RECT  2.16 315.495 246.24 315.765 ;
     RECT  2.16 316.035 246.24 316.305 ;
     RECT  2.16 316.575 246.24 316.845 ;
     RECT  2.16 317.115 246.24 317.385 ;
     RECT  2.16 317.655 246.24 317.925 ;
     RECT  2.16 318.195 246.24 318.465 ;
     RECT  2.16 318.735 246.24 319.005 ;
     RECT  2.16 319.275 246.24 319.545 ;
     RECT  2.16 319.815 246.24 320.085 ;
     RECT  2.16 320.355 246.24 320.625 ;
     RECT  2.16 320.895 246.24 321.165 ;
     RECT  2.16 321.435 246.24 321.705 ;
     RECT  2.16 321.975 246.24 322.245 ;
     RECT  2.16 322.515 246.24 322.785 ;
     RECT  2.16 323.055 246.24 323.325 ;
     RECT  2.16 323.595 246.24 323.865 ;
     RECT  2.16 324.135 246.24 324.405 ;
     RECT  2.16 324.675 246.24 324.945 ;
     RECT  2.16 325.215 246.24 325.485 ;
     RECT  2.16 325.755 246.24 326.025 ;
     RECT  2.16 326.295 246.24 326.565 ;
     RECT  2.16 326.835 246.24 327.105 ;
     RECT  2.16 327.375 246.24 327.645 ;
     RECT  2.16 327.915 246.24 328.185 ;
     RECT  2.16 328.455 246.24 328.725 ;
     RECT  2.16 328.995 246.24 329.265 ;
     RECT  2.16 329.535 246.24 329.805 ;
     RECT  2.16 330.075 246.24 330.345 ;
     RECT  2.16 330.615 246.24 330.885 ;
     RECT  2.16 331.155 246.24 331.425 ;
     RECT  2.16 331.695 246.24 331.965 ;
     RECT  2.16 332.235 246.24 332.505 ;
     RECT  2.16 332.775 246.24 333.045 ;
     RECT  2.16 333.315 246.24 333.585 ;
     RECT  2.16 333.855 246.24 334.125 ;
     RECT  2.16 334.395 246.24 334.665 ;
     RECT  2.16 334.935 246.24 335.205 ;
     RECT  2.16 335.475 246.24 335.745 ;
     RECT  2.16 336.015 246.24 336.285 ;
     RECT  2.16 336.555 246.24 336.825 ;
     RECT  2.16 337.095 246.24 337.365 ;
     RECT  2.16 337.635 246.24 337.905 ;
     RECT  2.16 338.175 246.24 338.445 ;
     RECT  2.16 338.715 246.24 338.985 ;
     RECT  2.16 339.255 246.24 339.525 ;
     RECT  2.16 339.795 246.24 340.065 ;
     RECT  2.16 340.335 246.24 340.605 ;
     RECT  2.16 340.875 246.24 341.145 ;
     RECT  2.16 341.415 246.24 341.685 ;
     RECT  2.16 341.955 246.24 342.225 ;
     RECT  2.16 342.495 246.24 342.765 ;
     RECT  2.16 343.035 246.24 343.305 ;
     RECT  2.16 343.575 246.24 343.845 ;
     RECT  2.16 344.115 246.24 344.385 ;
     RECT  2.16 344.655 246.24 344.925 ;
     RECT  2.16 345.195 246.24 345.465 ;
     RECT  2.16 345.735 246.24 346.005 ;
     RECT  2.16 346.275 246.24 346.545 ;
     RECT  2.16 346.815 246.24 347.085 ;
     RECT  2.16 347.355 246.24 347.625 ;
     RECT  2.16 347.895 246.24 348.165 ;
     RECT  2.16 348.435 246.24 348.705 ;
     RECT  2.16 348.975 246.24 349.245 ;
     RECT  2.16 349.515 246.24 349.785 ;
     RECT  2.16 350.055 246.24 350.325 ;
     RECT  2.16 350.595 246.24 350.865 ;
     RECT  2.16 351.135 246.24 351.405 ;
     RECT  2.16 351.675 246.24 351.945 ;
     RECT  2.16 352.215 246.24 352.485 ;
     RECT  2.16 352.755 246.24 353.025 ;
     RECT  2.16 353.295 246.24 353.565 ;
     RECT  2.16 353.835 246.24 354.105 ;
     RECT  2.16 354.375 246.24 354.645 ;
     RECT  2.16 354.915 246.24 355.185 ;
     RECT  2.16 355.455 246.24 355.725 ;
     RECT  2.16 355.995 246.24 356.265 ;
     RECT  2.16 356.535 246.24 356.805 ;
     RECT  2.16 357.075 246.24 357.345 ;
     RECT  2.16 357.615 246.24 357.885 ;
     RECT  2.16 358.155 246.24 358.425 ;
     RECT  2.16 358.695 246.24 358.965 ;
     RECT  2.16 359.235 246.24 359.505 ;
     RECT  2.16 359.775 246.24 360.045 ;
     RECT  2.16 360.315 246.24 360.585 ;
     RECT  2.16 360.855 246.24 361.125 ;
     RECT  2.16 361.395 246.24 361.665 ;
     RECT  2.16 361.935 246.24 362.205 ;
     RECT  2.16 362.475 246.24 362.745 ;
     RECT  2.16 363.015 246.24 363.285 ;
     RECT  2.16 363.555 246.24 363.825 ;
     RECT  2.16 364.095 246.24 364.365 ;
     RECT  2.16 364.635 246.24 364.905 ;
     RECT  2.16 365.175 246.24 365.445 ;
     RECT  2.16 365.715 246.24 365.985 ;
     RECT  2.16 366.255 246.24 366.525 ;
     RECT  2.16 366.795 246.24 367.065 ;
     RECT  2.16 367.335 246.24 367.605 ;
     RECT  2.16 367.875 246.24 368.145 ;
     RECT  2.16 368.415 246.24 368.685 ;
     RECT  2.16 368.955 246.24 369.225 ;
    LAYER M1 ;
     RECT  2.16 2.151 246.24 369.369 ;
    LAYER M2 ;
     RECT  0.031 173.988 0.067 174.006 ;
     RECT  0.067 173.79 0.103 174.006 ;
     RECT  0.103 173.601 0.131 174.006 ;
     RECT  0.131 173.601 0.167 173.808 ;
     RECT  0.167 173.601 0.175 173.7 ;
     RECT  0.139 172.602 0.535 172.62 ;
     RECT  0.175 173.52 0.535 173.7 ;
     RECT  0.031 163.53 2.16 163.548 ;
     RECT  0.103 164.34 2.16 164.358 ;
     RECT  0.175 166.77 2.16 166.788 ;
     RECT  0.067 168.93 2.16 168.948 ;
     RECT  0.535 172.602 2.16 173.7 ;
     RECT  0.103 208.782 2.16 208.8 ;
     RECT  2.16 2.151 246.24 369.369 ;
     RECT  246.24 174.906 246.515 174.924 ;
     RECT  246.24 192.276 246.551 192.294 ;
     RECT  246.24 180.666 246.587 180.684 ;
     RECT  246.24 190.926 246.623 191.484 ;
     RECT  246.24 162.036 246.839 163.674 ;
     RECT  246.24 185.796 246.875 188.784 ;
     RECT  246.839 162.45 246.911 163.674 ;
     RECT  246.24 176.688 247.091 176.706 ;
     RECT  246.623 191.466 247.127 191.484 ;
     RECT  246.24 182.196 247.163 182.214 ;
     RECT  246.911 162.648 247.379 163.674 ;
     RECT  246.875 185.796 247.379 187.974 ;
     RECT  246.875 188.766 247.379 188.784 ;
     RECT  247.379 162.648 247.415 162.666 ;
     RECT  247.379 185.796 247.415 185.814 ;
     RECT  247.379 186.714 247.415 187.974 ;
     RECT  247.379 163.656 248.315 163.674 ;
    LAYER M3 ;
     RECT  2.415 2.143 2.505 2.413 ;
     RECT  7.815 2.143 7.905 2.413 ;
     RECT  13.215 2.143 13.305 2.413 ;
     RECT  18.615 2.143 18.705 2.413 ;
     RECT  24.015 2.143 24.105 2.413 ;
     RECT  29.415 2.143 29.505 2.413 ;
     RECT  34.815 2.143 34.905 2.413 ;
     RECT  40.215 2.143 40.305 2.413 ;
     RECT  45.615 2.143 45.705 2.413 ;
     RECT  51.015 2.143 51.105 2.413 ;
     RECT  56.415 2.143 56.505 2.413 ;
     RECT  61.815 2.143 61.905 2.413 ;
     RECT  67.215 2.143 67.305 2.413 ;
     RECT  72.615 2.143 72.705 2.413 ;
     RECT  78.015 2.143 78.105 2.413 ;
     RECT  83.415 2.143 83.505 2.413 ;
     RECT  88.815 2.143 88.905 2.413 ;
     RECT  94.215 2.143 94.305 2.413 ;
     RECT  99.615 2.143 99.705 2.413 ;
     RECT  105.015 2.143 105.105 2.413 ;
     RECT  110.415 2.143 110.505 2.413 ;
     RECT  115.815 2.143 115.905 2.413 ;
     RECT  121.215 2.143 121.305 2.413 ;
     RECT  126.615 2.143 126.705 2.413 ;
     RECT  132.015 2.143 132.105 2.413 ;
     RECT  137.415 2.143 137.505 2.413 ;
     RECT  142.815 2.143 142.905 2.413 ;
     RECT  148.215 2.143 148.305 2.413 ;
     RECT  153.615 2.143 153.705 2.413 ;
     RECT  159.015 2.143 159.105 2.413 ;
     RECT  164.415 2.143 164.505 2.413 ;
     RECT  169.815 2.143 169.905 2.413 ;
     RECT  175.215 2.143 175.305 2.413 ;
     RECT  180.615 2.143 180.705 2.413 ;
     RECT  186.015 2.143 186.105 2.413 ;
     RECT  191.415 2.143 191.505 2.413 ;
     RECT  196.815 2.143 196.905 2.413 ;
     RECT  202.215 2.143 202.305 2.413 ;
     RECT  207.615 2.143 207.705 2.413 ;
     RECT  213.015 2.143 213.105 2.413 ;
     RECT  218.415 2.143 218.505 2.413 ;
     RECT  223.815 2.143 223.905 2.413 ;
     RECT  229.215 2.143 229.305 2.413 ;
     RECT  234.615 2.143 234.705 2.413 ;
     RECT  240.015 2.143 240.105 2.413 ;
     RECT  245.415 2.143 245.505 2.413 ;
     RECT  142.815 2.413 143.097 131.791 ;
     RECT  142.596 131.791 143.097 131.863 ;
     RECT  142.488 131.863 143.097 131.899 ;
     RECT  141.768 131.899 143.097 131.935 ;
     RECT  144.936 131.935 144.954 131.971 ;
     RECT  141.192 131.935 143.097 132.061 ;
     RECT  144.216 131.971 145.062 132.187 ;
     RECT  141.156 132.061 143.097 132.205 ;
     RECT  143.928 132.187 145.062 132.205 ;
     RECT  141.156 132.205 145.602 132.235 ;
     RECT  140.76 132.235 145.602 132.629 ;
     RECT  140.76 132.629 143.097 132.637 ;
     RECT  143.928 132.629 145.602 132.665 ;
     RECT  139.896 132.637 139.914 132.701 ;
     RECT  140.688 132.637 143.097 132.781 ;
     RECT  140.148 132.781 143.097 132.809 ;
     RECT  144.216 132.665 145.602 132.943 ;
     RECT  146.412 132.907 146.43 132.943 ;
     RECT  144.216 132.943 146.43 133.051 ;
     RECT  144.216 133.051 146.97 133.169 ;
     RECT  144.216 133.169 146.43 133.205 ;
     RECT  144.216 133.205 146.25 133.241 ;
     RECT  144.216 133.241 145.71 133.349 ;
     RECT  140.148 132.809 141.174 133.555 ;
     RECT  139.932 133.555 141.174 133.591 ;
     RECT  141.912 132.809 143.097 133.591 ;
     RECT  139.932 133.591 143.097 133.613 ;
     RECT  140.148 133.613 143.097 133.681 ;
     RECT  143.892 133.591 144.198 133.681 ;
     RECT  144.936 133.349 145.71 134.095 ;
     RECT  140.148 133.681 144.198 134.131 ;
     RECT  144.936 134.095 145.926 134.131 ;
     RECT  140.148 134.131 146.358 134.159 ;
     RECT  140.364 134.159 146.358 134.393 ;
     RECT  140.364 134.393 145.71 134.941 ;
     RECT  139.068 135.103 139.086 135.139 ;
     RECT  140.04 134.941 145.71 135.139 ;
     RECT  140.04 135.139 146.646 135.163 ;
     RECT  138.924 135.139 139.086 135.211 ;
     RECT  139.896 135.163 146.646 135.329 ;
     RECT  137.415 2.413 137.697 135.337 ;
     RECT  138.924 135.211 139.122 135.337 ;
     RECT  139.896 135.329 146.538 135.337 ;
     RECT  136.152 135.571 136.17 135.643 ;
     RECT  136.008 135.643 136.17 135.679 ;
     RECT  137.415 135.337 146.538 135.679 ;
     RECT  136.008 135.679 146.538 136.561 ;
     RECT  136.008 136.561 146.574 137.101 ;
     RECT  136.008 137.101 147.186 137.219 ;
     RECT  136.008 137.219 146.754 137.489 ;
     RECT  136.008 137.489 146.07 137.641 ;
     RECT  135.504 137.641 146.07 137.731 ;
     RECT  134.532 137.641 134.55 137.839 ;
     RECT  135.468 137.731 146.07 137.839 ;
     RECT  134.532 137.839 146.07 137.875 ;
     RECT  133.884 137.875 146.07 137.903 ;
     RECT  142.668 137.903 146.07 138.029 ;
     RECT  133.884 137.903 141.93 138.173 ;
     RECT  134.064 138.173 141.93 138.479 ;
     RECT  134.352 138.479 141.93 138.649 ;
     RECT  142.668 138.029 143.946 138.649 ;
     RECT  134.352 138.649 143.946 138.883 ;
     RECT  134.352 138.883 143.982 139.081 ;
     RECT  144.828 138.029 146.07 139.081 ;
     RECT  134.352 139.081 146.07 139.099 ;
     RECT  134.352 139.099 146.142 139.225 ;
     RECT  133.74 139.225 146.142 139.379 ;
     RECT  134.352 139.379 146.142 139.423 ;
     RECT  133.56 139.387 133.578 139.451 ;
     RECT  134.352 139.423 146.862 139.459 ;
     RECT  134.352 139.459 147.33 139.649 ;
     RECT  134.424 139.649 147.33 139.801 ;
     RECT  148.215 2.413 148.497 139.801 ;
     RECT  134.424 139.801 148.497 140.093 ;
     RECT  134.568 140.093 148.497 140.189 ;
     RECT  135.9 140.189 148.497 140.237 ;
     RECT  133.632 140.731 133.65 140.773 ;
     RECT  134.568 140.189 134.91 141.043 ;
     RECT  134.532 141.043 135.09 141.115 ;
     RECT  135.936 140.237 148.497 141.115 ;
     RECT  133.632 140.773 133.794 141.151 ;
     RECT  134.532 141.115 148.497 141.151 ;
     RECT  133.416 141.151 148.497 141.881 ;
     RECT  132.015 2.413 132.297 142.231 ;
     RECT  133.416 141.881 147.402 142.231 ;
     RECT  132.015 142.231 147.402 142.349 ;
     RECT  133.452 142.349 147.402 142.771 ;
     RECT  148.215 141.881 148.497 142.771 ;
     RECT  132.015 142.349 132.714 143.179 ;
     RECT  131.94 143.179 132.714 143.239 ;
     RECT  133.452 142.771 148.497 143.239 ;
     RECT  131.94 143.239 148.497 143.501 ;
     RECT  131.94 143.501 146.862 143.779 ;
     RECT  151.74 143.671 152.154 143.779 ;
     RECT  151.596 143.779 152.154 143.845 ;
     RECT  131.904 143.779 146.862 143.851 ;
     RECT  131.58 143.851 146.862 143.899 ;
     RECT  147.672 143.501 148.497 143.941 ;
     RECT  131.436 143.899 146.862 143.969 ;
     RECT  151.2 143.845 152.154 143.977 ;
     RECT  147.672 143.941 148.842 144.085 ;
     RECT  149.976 144.049 149.994 144.085 ;
     RECT  147.672 144.085 149.994 144.121 ;
     RECT  150.732 143.977 152.154 144.121 ;
     RECT  131.904 143.969 146.862 144.319 ;
     RECT  147.672 144.121 152.154 144.319 ;
     RECT  131.904 144.319 152.154 144.347 ;
     RECT  153.615 2.413 153.897 144.661 ;
     RECT  153.324 144.661 153.897 144.779 ;
     RECT  151.344 144.347 152.154 144.895 ;
     RECT  151.344 144.895 152.838 145.049 ;
     RECT  131.904 144.347 150.606 145.165 ;
     RECT  151.344 145.049 152.118 145.319 ;
     RECT  131.364 145.165 150.606 145.339 ;
     RECT  131.184 145.339 150.606 145.471 ;
     RECT  151.344 145.319 151.938 145.471 ;
     RECT  131.184 145.471 151.938 145.915 ;
     RECT  130.824 145.915 151.938 146.165 ;
     RECT  131.112 146.165 151.938 146.371 ;
     RECT  131.112 146.371 152.154 146.479 ;
     RECT  131.112 146.479 152.55 146.515 ;
     RECT  131.112 146.515 152.802 146.551 ;
     RECT  153.615 144.779 153.897 146.551 ;
     RECT  131.112 146.551 153.897 146.975 ;
     RECT  131.112 146.975 152.154 147.623 ;
     RECT  131.112 147.623 133.974 147.691 ;
     RECT  134.784 147.623 152.154 147.757 ;
     RECT  153.252 146.975 153.897 147.757 ;
     RECT  134.784 147.757 153.897 147.785 ;
     RECT  134.784 147.785 152.838 147.857 ;
     RECT  130.68 147.691 133.974 148.163 ;
     RECT  135.108 147.857 152.838 148.433 ;
     RECT  133.344 148.163 133.974 148.441 ;
     RECT  130.68 148.163 132.606 148.559 ;
     RECT  133.344 148.441 134.082 148.603 ;
     RECT  135.108 148.433 150.03 148.603 ;
     RECT  130.68 148.559 130.698 148.829 ;
     RECT  129.348 148.795 129.366 148.981 ;
     RECT  131.508 148.559 132.606 148.981 ;
     RECT  133.344 148.603 150.03 148.981 ;
     RECT  150.912 148.433 152.838 148.981 ;
     RECT  129.024 148.981 129.366 149.071 ;
     RECT  128.52 149.071 129.366 149.215 ;
     RECT  128.232 149.215 129.366 149.251 ;
     RECT  150.912 148.981 152.874 149.251 ;
     RECT  153.615 147.785 153.897 149.251 ;
     RECT  131.508 148.981 150.03 149.323 ;
     RECT  150.912 149.251 153.897 149.323 ;
     RECT  128.232 149.251 129.474 149.521 ;
     RECT  130.536 149.377 130.554 149.521 ;
     RECT  131.508 149.323 153.897 149.521 ;
     RECT  131.292 149.521 153.99 149.639 ;
     RECT  128.232 149.521 130.554 149.899 ;
     RECT  128.016 149.899 130.554 150.061 ;
     RECT  131.292 149.639 153.897 150.061 ;
     RECT  126.615 2.413 126.897 150.427 ;
     RECT  125.856 150.427 127.098 150.485 ;
     RECT  125.964 150.485 127.098 150.601 ;
     RECT  125.964 150.601 127.206 150.691 ;
     RECT  128.016 150.061 153.897 150.691 ;
     RECT  125.964 150.691 153.897 150.755 ;
     RECT  125.964 150.755 152.838 150.989 ;
     RECT  128.376 150.989 152.838 151.061 ;
     RECT  125.964 150.989 127.422 151.411 ;
     RECT  125.64 151.411 127.422 151.573 ;
     RECT  128.412 151.061 152.838 151.601 ;
     RECT  125.46 151.573 127.422 151.613 ;
     RECT  129.132 151.601 152.838 151.915 ;
     RECT  153.615 150.755 153.897 151.915 ;
     RECT  125.964 151.613 127.422 152.041 ;
     RECT  129.132 151.915 153.897 152.069 ;
     RECT  125.964 152.041 128.25 152.491 ;
     RECT  129.132 152.069 152.874 152.491 ;
     RECT  125.964 152.491 152.874 152.609 ;
     RECT  129.636 152.609 152.874 152.681 ;
     RECT  129.708 152.681 152.874 152.753 ;
     RECT  129.816 152.753 152.874 152.789 ;
     RECT  153.615 152.069 153.897 152.887 ;
     RECT  125.964 152.609 128.826 153.031 ;
     RECT  153.615 152.887 153.954 153.031 ;
     RECT  130.608 152.789 152.874 153.115 ;
     RECT  153.615 153.031 154.422 153.115 ;
     RECT  130.608 153.115 154.422 153.149 ;
     RECT  125.568 153.031 128.826 153.157 ;
     RECT  125.424 153.157 128.826 153.197 ;
     RECT  125.964 153.197 128.826 153.725 ;
     RECT  130.608 153.149 154.098 153.733 ;
     RECT  126.504 153.725 128.826 153.761 ;
     RECT  129.816 152.789 129.834 153.805 ;
     RECT  130.572 153.733 154.098 153.805 ;
     RECT  126.615 153.761 128.826 153.931 ;
     RECT  129.744 153.805 154.098 153.931 ;
     RECT  126.615 153.931 154.098 154.027 ;
     RECT  155.088 153.967 155.106 154.027 ;
     RECT  126.615 154.027 155.106 154.229 ;
     RECT  129.888 154.229 155.106 154.273 ;
     RECT  155.88 154.237 156.006 154.273 ;
     RECT  129.888 154.273 156.006 154.345 ;
     RECT  129.888 154.345 156.114 154.381 ;
     RECT  129.888 154.381 156.186 154.409 ;
     RECT  130.104 154.409 156.186 154.885 ;
     RECT  130.104 154.885 156.726 154.921 ;
     RECT  130.104 154.921 157.266 155.039 ;
     RECT  130.104 155.039 156.726 155.183 ;
     RECT  126.615 154.229 128.934 155.275 ;
     RECT  130.104 155.183 156.294 155.275 ;
     RECT  126.615 155.275 156.294 155.651 ;
     RECT  126.615 155.651 153.897 156.397 ;
     RECT  154.944 155.651 156.294 156.505 ;
     RECT  126.615 156.397 154.17 156.541 ;
     RECT  154.944 156.505 156.726 156.541 ;
     RECT  126.615 156.541 157.23 156.659 ;
     RECT  126.615 156.659 156.726 156.803 ;
     RECT  126.615 156.803 156.618 156.811 ;
     RECT  126.54 156.811 156.618 156.907 ;
     RECT  126.396 156.907 156.618 156.965 ;
     RECT  126.615 156.965 156.618 157.199 ;
     RECT  127.62 157.199 156.618 157.855 ;
     RECT  127.62 157.855 156.834 157.891 ;
     RECT  126.615 157.199 126.897 158.161 ;
     RECT  127.62 157.891 157.266 158.161 ;
     RECT  126.615 158.161 157.266 158.701 ;
     RECT  126.615 158.701 157.338 158.819 ;
     RECT  121.215 2.413 121.497 158.971 ;
     RECT  119.124 158.971 119.718 159.019 ;
     RECT  121.215 158.971 122.13 159.061 ;
     RECT  119.124 159.019 119.79 159.169 ;
     RECT  119.124 159.169 119.862 159.205 ;
     RECT  121.215 159.061 122.814 159.205 ;
     RECT  121.176 159.205 123.39 159.331 ;
     RECT  124.164 159.097 124.182 159.331 ;
     RECT  118.98 159.205 119.862 159.367 ;
     RECT  120.708 159.331 124.182 159.367 ;
     RECT  117.972 159.019 117.99 159.511 ;
     RECT  118.98 159.367 124.182 159.511 ;
     RECT  117.972 159.511 124.254 159.595 ;
     RECT  117.972 159.595 124.542 159.745 ;
     RECT  117.612 159.745 124.542 159.781 ;
     RECT  117.612 159.781 124.686 160.249 ;
     RECT  126.615 158.819 156.942 160.411 ;
     RECT  126.18 160.411 156.942 160.483 ;
     RECT  126.18 160.483 157.23 160.555 ;
     RECT  117.612 160.249 124.758 160.591 ;
     RECT  126.18 160.555 157.41 160.591 ;
     RECT  126.036 160.591 157.41 160.699 ;
     RECT  125.748 160.699 157.41 160.709 ;
     RECT  125.748 160.709 157.338 160.745 ;
     RECT  125.748 160.745 157.158 160.817 ;
     RECT  117.612 160.591 124.83 160.861 ;
     RECT  125.748 160.817 157.05 160.861 ;
     RECT  117.612 160.861 157.05 161.321 ;
     RECT  117.612 161.321 128.538 161.323 ;
     RECT  117.288 161.323 128.538 161.519 ;
     RECT  244.368 161.401 244.386 161.519 ;
     RECT  245.415 2.413 245.697 161.671 ;
     RECT  129.528 161.321 157.05 161.699 ;
     RECT  117.432 161.519 128.538 161.789 ;
     RECT  129.528 161.699 156.942 161.789 ;
     RECT  242.244 161.671 242.262 161.789 ;
     RECT  117.432 161.789 128.43 161.825 ;
     RECT  129.528 161.789 156.15 161.825 ;
     RECT  244.8 161.671 245.697 162.095 ;
     RECT  244.008 161.941 244.026 162.211 ;
     RECT  245.415 162.095 245.697 162.211 ;
     RECT  243.36 162.211 244.026 162.301 ;
     RECT  243.36 162.301 244.638 162.329 ;
     RECT  129.528 161.825 156.042 162.365 ;
     RECT  129.528 162.365 154.998 162.401 ;
     RECT  246.816 162.031 246.834 162.445 ;
     RECT  155.772 162.365 156.042 162.607 ;
     RECT  156.924 161.789 156.942 162.607 ;
     RECT  246.816 162.445 246.906 162.643 ;
     RECT  117.468 161.825 128.43 162.751 ;
     RECT  155.772 162.607 156.942 162.751 ;
     RECT  245.415 162.211 245.79 162.751 ;
     RECT  246.816 162.643 247.41 162.751 ;
     RECT  244.548 162.329 244.638 162.841 ;
     RECT  245.415 162.751 247.41 162.841 ;
     RECT  244.548 162.841 247.41 162.869 ;
     RECT  117.468 162.751 128.538 162.877 ;
     RECT  117.468 162.877 128.61 162.905 ;
     RECT  126.288 162.905 128.61 162.941 ;
     RECT  117.468 162.905 125.514 162.985 ;
     RECT  115.815 2.413 116.097 163.021 ;
     RECT  117.036 162.985 125.514 163.037 ;
     RECT  244.764 162.869 247.41 163.085 ;
     RECT  155.772 162.751 157.518 163.111 ;
     RECT  115.815 163.021 116.226 163.139 ;
     RECT  126.615 162.941 128.61 163.147 ;
     RECT  129.528 162.401 154.962 163.147 ;
     RECT  155.772 163.111 157.986 163.147 ;
     RECT  117.468 163.037 125.514 163.175 ;
     RECT  126.615 163.147 154.962 163.175 ;
     RECT  243.432 162.329 243.45 163.175 ;
     RECT  115.815 163.139 116.154 163.255 ;
     RECT  127.62 163.175 154.962 163.255 ;
     RECT  155.736 163.147 157.986 163.255 ;
     RECT  247.356 163.085 247.41 163.277 ;
     RECT  127.62 163.255 157.986 163.381 ;
     RECT  243.72 163.291 243.738 163.409 ;
     RECT  247.356 163.277 247.374 163.409 ;
     RECT  244.764 163.085 246.258 163.469 ;
     RECT  115.272 163.255 116.154 163.565 ;
     RECT  244.764 163.469 245.697 163.589 ;
     RECT  2.415 2.413 2.697 163.651 ;
     RECT  248.292 163.147 248.31 163.679 ;
     RECT  126.615 163.175 126.897 163.831 ;
     RECT  127.62 163.381 158.13 163.859 ;
     RECT  128.412 163.859 158.13 163.921 ;
     RECT  159.015 2.413 159.297 163.921 ;
     RECT  126.504 163.831 126.897 163.949 ;
     RECT  117.54 163.175 125.514 164.029 ;
     RECT  128.412 163.921 159.297 164.101 ;
     RECT  117.504 164.029 125.514 164.129 ;
     RECT  2.415 163.651 3.33 164.219 ;
     RECT  244.404 163.795 244.422 164.219 ;
     RECT  0.036 163.525 0.054 164.335 ;
     RECT  117.504 164.129 121.554 164.371 ;
     RECT  117.432 164.371 121.554 164.533 ;
     RECT  128.412 164.101 159.462 164.569 ;
     RECT  115.815 163.565 116.154 164.605 ;
     RECT  117.396 164.533 121.554 164.605 ;
     RECT  115.815 164.605 121.554 164.669 ;
     RECT  128.412 164.569 159.498 164.669 ;
     RECT  244.332 164.371 244.35 164.669 ;
     RECT  116.856 164.669 121.554 164.911 ;
     RECT  122.292 164.129 125.514 164.911 ;
     RECT  127.62 163.859 127.638 164.911 ;
     RECT  128.412 164.669 159.462 164.911 ;
     RECT  126.615 163.949 126.897 165.109 ;
     RECT  127.62 164.911 159.462 165.109 ;
     RECT  116.856 164.911 125.514 165.299 ;
     RECT  126.615 165.109 159.462 165.443 ;
     RECT  126.615 165.443 127.89 165.479 ;
     RECT  127.62 165.479 127.89 165.485 ;
     RECT  128.628 165.443 159.462 165.875 ;
     RECT  116.928 165.299 125.514 166.019 ;
     RECT  116.928 166.019 116.946 166.109 ;
     RECT  115.056 165.883 115.074 166.145 ;
     RECT  115.815 164.669 116.097 166.261 ;
     RECT  128.808 165.875 159.462 166.261 ;
     RECT  117.756 166.019 125.514 166.445 ;
     RECT  115.2 166.261 116.097 166.649 ;
     RECT  118.044 166.445 125.514 166.649 ;
     RECT  127.62 165.485 127.638 166.651 ;
     RECT  128.808 166.261 159.606 166.651 ;
     RECT  0.036 164.335 0.126 166.765 ;
     RECT  127.62 166.651 159.606 166.765 ;
     RECT  127.62 166.765 160.29 166.891 ;
     RECT  126.615 165.479 126.897 167.563 ;
     RECT  127.62 166.891 160.578 167.563 ;
     RECT  126.615 167.563 160.578 167.603 ;
     RECT  127.62 167.603 160.578 167.881 ;
     RECT  127.62 167.881 160.614 167.971 ;
     RECT  161.604 167.341 161.622 167.971 ;
     RECT  2.415 164.219 2.697 168.511 ;
     RECT  118.044 166.649 125.442 168.583 ;
     RECT  118.008 168.583 125.442 168.667 ;
     RECT  117.108 168.655 117.126 168.701 ;
     RECT  4.5 164.461 4.518 168.889 ;
     RECT  117.972 168.667 125.442 168.889 ;
     RECT  115.815 166.649 116.097 168.961 ;
     RECT  3.996 168.889 4.518 168.989 ;
     RECT  126.615 167.603 126.897 169.147 ;
     RECT  127.62 167.971 161.622 169.147 ;
     RECT  115.815 168.961 116.334 169.277 ;
     RECT  117.9 168.889 125.442 169.321 ;
     RECT  126.615 169.147 161.622 169.501 ;
     RECT  126.615 169.501 161.838 169.529 ;
     RECT  117.396 169.321 125.442 169.663 ;
     RECT  159.015 169.529 161.838 169.889 ;
     RECT  115.815 169.277 116.097 170.005 ;
     RECT  117.252 169.663 125.442 170.005 ;
     RECT  126.615 169.529 157.302 170.041 ;
     RECT  126.252 170.041 157.302 170.195 ;
     RECT  126.252 170.195 132.462 170.303 ;
     RECT  115.815 170.005 125.442 170.311 ;
     RECT  126.252 170.303 126.897 170.311 ;
     RECT  159.015 169.889 159.714 170.401 ;
     RECT  158.652 170.401 159.714 170.437 ;
     RECT  115.815 170.311 126.897 170.465 ;
     RECT  133.272 170.195 157.302 170.473 ;
     RECT  158.292 170.437 159.714 170.473 ;
     RECT  126.18 170.465 126.897 170.699 ;
     RECT  133.272 170.473 159.714 170.851 ;
     RECT  127.62 170.303 132.462 170.941 ;
     RECT  133.272 170.851 159.75 170.941 ;
     RECT  127.62 170.941 159.75 170.977 ;
     RECT  160.56 169.889 161.838 170.977 ;
     RECT  115.815 170.465 125.442 171.239 ;
     RECT  4.5 168.989 4.518 171.247 ;
     RECT  126.252 170.699 126.897 171.391 ;
     RECT  127.62 170.977 161.838 171.391 ;
     RECT  126.252 171.391 161.838 171.509 ;
     RECT  2.415 168.511 2.862 171.787 ;
     RECT  2.415 171.787 3.006 172.021 ;
     RECT  3.852 171.247 4.518 172.021 ;
     RECT  115.056 171.391 115.074 172.021 ;
     RECT  115.815 171.239 116.097 172.093 ;
     RECT  116.82 171.239 125.442 172.093 ;
     RECT  114.984 172.021 115.074 172.327 ;
     RECT  114.588 172.327 115.074 172.391 ;
     RECT  127.62 171.509 161.838 172.391 ;
     RECT  2.415 172.021 4.518 172.435 ;
     RECT  115.815 172.093 125.442 172.471 ;
     RECT  114.588 172.391 114.75 172.561 ;
     RECT  114.012 172.561 114.75 172.589 ;
     RECT  115.524 172.471 125.514 172.589 ;
     RECT  0.036 166.765 0.198 172.633 ;
     RECT  2.34 172.435 4.518 172.651 ;
     RECT  113.04 172.597 113.058 172.651 ;
     RECT  113.04 172.651 113.166 172.697 ;
     RECT  127.62 172.391 127.962 172.733 ;
     RECT  113.04 172.697 113.058 172.769 ;
     RECT  128.988 172.391 161.838 172.877 ;
     RECT  6.768 172.867 6.786 173.003 ;
     RECT  0.036 172.633 0.558 173.357 ;
     RECT  114.012 172.589 114.606 173.399 ;
     RECT  114.012 173.399 114.03 173.435 ;
     RECT  126.252 171.509 126.897 173.479 ;
     RECT  127.944 172.733 127.962 173.479 ;
     RECT  115.776 172.589 125.514 173.509 ;
     RECT  2.304 172.651 4.518 173.669 ;
     RECT  2.304 173.669 4.302 173.741 ;
     RECT  115.056 173.509 125.514 173.939 ;
     RECT  0.036 173.357 0.27 174.011 ;
     RECT  117.396 173.939 125.514 174.091 ;
     RECT  126.252 173.479 127.962 174.091 ;
     RECT  0.108 174.011 0.27 174.125 ;
     RECT  113.976 174.091 113.994 174.209 ;
     RECT  115.056 173.939 116.514 174.209 ;
     RECT  117.396 174.091 127.962 174.209 ;
     RECT  4.212 173.741 4.302 174.317 ;
     RECT  114.876 174.325 114.894 174.361 ;
     RECT  245.415 163.589 245.697 174.361 ;
     RECT  113.832 174.331 113.85 174.389 ;
     RECT  129.096 172.877 161.838 174.487 ;
     RECT  128.808 174.487 161.838 174.559 ;
     RECT  2.304 173.741 3.366 174.631 ;
     RECT  123.3 174.209 127.962 174.631 ;
     RECT  128.772 174.559 161.838 174.631 ;
     RECT  0.144 174.125 0.27 174.667 ;
     RECT  2.304 174.631 3.69 174.749 ;
     RECT  245.124 174.361 245.697 174.785 ;
     RECT  0.144 174.667 0.342 174.797 ;
     RECT  114.768 174.361 114.894 174.901 ;
     RECT  114.588 174.901 114.894 174.929 ;
     RECT  115.776 174.209 116.514 175.027 ;
     RECT  117.396 174.209 122.562 175.027 ;
     RECT  114.588 174.929 114.822 175.091 ;
     RECT  115.776 175.027 122.562 175.135 ;
     RECT  115.668 175.135 122.562 175.171 ;
     RECT  123.3 174.631 161.838 175.171 ;
     RECT  113.436 175.135 113.454 175.181 ;
     RECT  114.588 175.091 114.786 175.181 ;
     RECT  114.624 175.181 114.786 175.289 ;
     RECT  0.216 174.797 0.342 175.373 ;
     RECT  114.66 175.289 114.786 175.397 ;
     RECT  0.216 175.373 0.234 175.565 ;
     RECT  4.824 174.859 4.842 175.595 ;
     RECT  115.668 175.171 161.838 175.595 ;
     RECT  2.304 174.749 3.51 175.711 ;
     RECT  2.304 175.711 4.05 175.865 ;
     RECT  45.615 2.413 45.897 175.873 ;
     RECT  2.415 175.865 4.05 175.981 ;
     RECT  245.415 174.785 245.697 176.071 ;
     RECT  246.492 174.901 246.51 176.071 ;
     RECT  244.116 175.981 244.134 176.099 ;
     RECT  125.424 175.595 161.838 176.207 ;
     RECT  245.415 176.071 246.51 176.215 ;
     RECT  245.088 176.215 246.51 176.369 ;
     RECT  245.415 176.369 246.51 176.683 ;
     RECT  115.776 175.595 124.65 177.025 ;
     RECT  125.568 176.207 161.838 177.025 ;
     RECT  115.776 177.025 161.838 177.359 ;
     RECT  129.6 177.359 161.838 177.449 ;
     RECT  115.776 177.359 128.826 177.485 ;
     RECT  131.4 177.449 161.838 177.485 ;
     RECT  115.776 177.485 124.614 177.899 ;
     RECT  129.6 177.449 130.446 178.303 ;
     RECT  129.6 178.303 130.698 178.375 ;
     RECT  131.58 177.485 161.838 178.375 ;
     RECT  125.424 177.485 128.826 178.411 ;
     RECT  129.6 178.375 161.838 178.411 ;
     RECT  115.776 177.899 124.434 178.645 ;
     RECT  125.208 178.411 161.838 178.645 ;
     RECT  115.776 178.645 161.838 178.771 ;
     RECT  114.768 175.397 114.786 178.799 ;
     RECT  115.74 178.771 161.838 178.871 ;
     RECT  164.415 2.413 164.697 179.311 ;
     RECT  175.215 2.413 175.497 179.311 ;
     RECT  186.015 2.413 186.297 179.311 ;
     RECT  196.815 2.413 197.097 179.311 ;
     RECT  207.615 2.413 207.897 179.311 ;
     RECT  218.415 2.413 218.697 179.311 ;
     RECT  229.215 2.413 229.497 179.311 ;
     RECT  240.015 2.413 240.297 179.311 ;
     RECT  164.304 179.311 164.697 179.357 ;
     RECT  175.104 179.311 175.497 179.357 ;
     RECT  185.904 179.311 186.297 179.357 ;
     RECT  196.704 179.311 197.097 179.357 ;
     RECT  207.504 179.311 207.897 179.357 ;
     RECT  218.304 179.311 218.697 179.357 ;
     RECT  229.104 179.311 229.497 179.357 ;
     RECT  239.904 179.311 240.297 179.357 ;
     RECT  242.244 179.323 242.262 179.453 ;
     RECT  115.776 178.871 161.838 179.689 ;
     RECT  115.776 179.689 161.982 179.915 ;
     RECT  115.776 179.915 123.642 180.149 ;
     RECT  124.416 179.915 161.982 180.149 ;
     RECT  115.815 180.149 123.642 181.099 ;
     RECT  124.416 180.149 161.946 181.111 ;
     RECT  115.815 181.099 123.678 181.139 ;
     RECT  115.815 181.139 123.606 181.229 ;
     RECT  124.416 181.111 161.982 181.579 ;
     RECT  124.416 181.579 162.27 181.679 ;
     RECT  115.815 181.229 123.462 181.867 ;
     RECT  124.416 181.679 162.126 181.885 ;
     RECT  115.668 181.867 123.462 182.039 ;
     RECT  124.272 181.885 162.126 182.039 ;
     RECT  244.548 181.651 244.566 182.075 ;
     RECT  245.415 176.683 247.086 182.191 ;
     RECT  124.272 182.039 162.09 182.219 ;
     RECT  115.704 182.039 123.462 182.353 ;
     RECT  124.272 182.219 161.982 182.353 ;
     RECT  115.704 182.353 161.982 183.127 ;
     RECT  114.336 183.115 114.354 183.155 ;
     RECT  115.704 183.127 162.054 183.199 ;
     RECT  115.704 183.199 162.126 183.271 ;
     RECT  115.308 183.271 162.306 183.497 ;
     RECT  115.815 183.497 162.306 185.117 ;
     RECT  163.332 185.395 163.35 185.431 ;
     RECT  163.332 185.431 163.494 185.621 ;
     RECT  245.415 182.191 247.158 185.791 ;
     RECT  163.332 185.621 163.35 185.837 ;
     RECT  245.415 185.791 247.41 185.971 ;
     RECT  115.815 185.117 162.234 186.061 ;
     RECT  163.152 185.971 163.17 186.089 ;
     RECT  244.8 185.971 247.41 186.205 ;
     RECT  166.248 186.187 166.266 186.241 ;
     RECT  166.248 186.241 166.95 186.269 ;
     RECT  166.932 186.269 166.95 186.365 ;
     RECT  115.815 186.061 162.378 186.367 ;
     RECT  243.504 186.331 243.522 186.475 ;
     RECT  244.548 186.205 247.41 186.511 ;
     RECT  244.332 186.511 247.41 186.629 ;
     RECT  242.856 186.475 243.522 186.673 ;
     RECT  238.284 186.781 238.302 186.899 ;
     RECT  244.728 186.629 247.41 186.899 ;
     RECT  242.856 186.673 243.918 187.015 ;
     RECT  242.604 187.015 243.918 187.169 ;
     RECT  115.815 186.367 162.738 187.291 ;
     RECT  115.815 187.291 163.35 187.435 ;
     RECT  164.415 179.357 164.697 187.435 ;
     RECT  115.815 187.435 164.697 187.439 ;
     RECT  242.856 187.169 243.918 187.439 ;
     RECT  243.9 187.439 243.918 187.469 ;
     RECT  164.016 187.439 164.697 187.475 ;
     RECT  248.22 187.339 248.238 187.517 ;
     RECT  115.815 187.439 162.522 187.745 ;
     RECT  244.872 186.899 247.41 187.771 ;
     RECT  243.936 187.771 247.41 188.237 ;
     RECT  243.936 188.237 247.374 188.249 ;
     RECT  244.476 188.249 247.374 188.519 ;
     RECT  244.548 188.519 247.374 188.525 ;
     RECT  242.856 187.439 242.874 188.563 ;
     RECT  244.548 188.525 245.79 188.663 ;
     RECT  246.528 188.525 247.374 188.789 ;
     RECT  242.244 188.563 242.874 189.239 ;
     RECT  244.692 188.663 245.79 189.599 ;
     RECT  163.656 189.715 163.674 189.751 ;
     RECT  164.415 187.475 164.697 189.751 ;
     RECT  114.084 189.715 114.102 189.821 ;
     RECT  163.656 189.751 164.697 189.821 ;
     RECT  115.815 187.745 162.198 190.247 ;
     RECT  163.8 189.821 164.697 190.409 ;
     RECT  244.872 189.599 245.79 190.525 ;
     RECT  125.64 190.247 162.198 190.561 ;
     RECT  125.64 190.561 162.594 190.651 ;
     RECT  244.8 190.525 245.79 190.679 ;
     RECT  244.872 190.679 245.79 191.065 ;
     RECT  246.528 188.789 247.122 191.065 ;
     RECT  125.64 190.651 163.314 191.219 ;
     RECT  244.872 191.065 247.122 191.489 ;
     RECT  125.64 191.219 162.774 191.501 ;
     RECT  125.748 191.501 162.774 191.525 ;
     RECT  163.62 191.515 163.638 191.605 ;
     RECT  164.415 190.409 164.697 191.605 ;
     RECT  242.856 189.239 242.874 191.605 ;
     RECT  2.415 175.981 4.086 191.759 ;
     RECT  242.496 191.605 242.874 191.759 ;
     RECT  244.872 191.489 246.546 191.759 ;
     RECT  115.815 190.247 124.722 191.911 ;
     RECT  114.084 191.875 114.102 191.933 ;
     RECT  163.62 191.605 164.697 192.029 ;
     RECT  241.416 191.641 241.434 192.029 ;
     RECT  242.64 191.759 242.658 192.029 ;
     RECT  246.528 191.759 246.546 192.299 ;
     RECT  164.415 192.029 164.697 192.307 ;
     RECT  115.632 191.911 124.722 192.667 ;
     RECT  125.82 191.525 162.774 192.667 ;
     RECT  115.632 192.667 162.774 192.839 ;
     RECT  164.415 192.307 165.294 192.989 ;
     RECT  126.216 192.839 162.774 193.081 ;
     RECT  126.216 193.081 162.846 193.189 ;
     RECT  115.632 192.839 125.442 193.289 ;
     RECT  244.872 191.759 245.697 193.289 ;
     RECT  115.632 193.289 124.722 193.387 ;
     RECT  126.216 193.189 162.882 194.161 ;
     RECT  115.416 193.387 124.722 194.189 ;
     RECT  126.036 194.161 162.882 194.611 ;
     RECT  115.488 194.189 124.722 194.737 ;
     RECT  125.676 194.611 162.882 194.737 ;
     RECT  115.488 194.737 162.882 194.957 ;
     RECT  5.04 175.711 5.058 195.035 ;
     RECT  114.264 194.923 114.282 195.151 ;
     RECT  114.012 195.151 114.282 195.179 ;
     RECT  114.012 195.179 114.03 195.511 ;
     RECT  113.652 195.511 114.03 195.539 ;
     RECT  2.415 191.759 4.05 195.809 ;
     RECT  115.815 194.957 162.882 196.051 ;
     RECT  3.6 195.809 4.05 196.079 ;
     RECT  115.164 196.051 162.882 197.041 ;
     RECT  3.6 196.079 3.618 197.159 ;
     RECT  113.652 195.539 113.67 197.195 ;
     RECT  114.624 197.041 162.882 197.231 ;
     RECT  114.948 197.231 162.882 197.549 ;
     RECT  114.948 197.549 124.83 197.699 ;
     RECT  125.964 197.549 162.882 198.121 ;
     RECT  125.964 198.121 162.954 198.275 ;
     RECT  131.58 198.275 162.954 198.311 ;
     RECT  131.688 198.311 162.954 198.509 ;
     RECT  114.948 197.699 124.722 198.517 ;
     RECT  114.948 198.517 124.974 198.661 ;
     RECT  125.964 198.275 130.518 198.661 ;
     RECT  114.948 198.661 130.518 198.763 ;
     RECT  45.615 175.873 46.458 198.779 ;
     RECT  113.76 198.751 113.85 198.797 ;
     RECT  113.76 198.797 113.778 198.851 ;
     RECT  131.688 198.509 162.774 199.051 ;
     RECT  114.84 198.763 130.518 199.057 ;
     RECT  114.84 199.057 130.698 199.291 ;
     RECT  131.616 199.051 162.774 199.291 ;
     RECT  114.84 199.291 162.774 199.469 ;
     RECT  115.38 199.469 162.774 199.471 ;
     RECT  115.38 199.471 162.846 199.831 ;
     RECT  115.38 199.831 163.026 199.867 ;
     RECT  115.38 199.867 163.098 200.201 ;
     RECT  115.38 200.201 162.99 200.507 ;
     RECT  115.38 200.507 162.846 201.631 ;
     RECT  115.164 201.631 163.062 201.739 ;
     RECT  115.128 201.739 163.062 202.019 ;
     RECT  115.56 202.019 163.062 202.099 ;
     RECT  115.56 202.099 163.098 202.939 ;
     RECT  115.344 202.939 163.098 202.981 ;
     RECT  115.272 202.981 163.098 203.135 ;
     RECT  115.344 203.135 163.098 203.251 ;
     RECT  115.344 203.251 163.602 203.477 ;
     RECT  115.704 203.477 163.602 203.639 ;
     RECT  115.704 203.639 122.166 203.675 ;
     RECT  123.228 203.639 163.602 203.989 ;
     RECT  123.228 203.989 163.638 204.179 ;
     RECT  123.228 204.179 163.602 204.251 ;
     RECT  115.704 203.675 122.058 204.323 ;
     RECT  115.704 204.323 121.95 204.593 ;
     RECT  123.228 204.251 163.422 204.715 ;
     RECT  115.776 204.593 121.95 204.719 ;
     RECT  115.776 204.719 121.914 204.749 ;
     RECT  2.415 195.809 2.697 204.811 ;
     RECT  2.304 204.811 2.697 204.835 ;
     RECT  115.776 204.749 121.806 204.899 ;
     RECT  115.815 204.899 121.806 204.989 ;
     RECT  2.304 204.835 3.258 205.025 ;
     RECT  122.76 204.715 163.422 205.025 ;
     RECT  117.036 204.989 121.806 205.061 ;
     RECT  2.34 205.025 3.258 205.141 ;
     RECT  122.76 205.025 163.386 205.141 ;
     RECT  122.724 205.141 163.386 205.259 ;
     RECT  6.804 205.231 6.822 205.439 ;
     RECT  114.588 205.411 114.606 205.529 ;
     RECT  2.34 205.141 3.33 205.681 ;
     RECT  117.072 205.061 121.806 205.757 ;
     RECT  117.36 205.757 121.806 205.951 ;
     RECT  2.34 205.681 3.69 205.979 ;
     RECT  122.724 205.259 122.886 206.069 ;
     RECT  123.732 205.259 163.386 206.069 ;
     RECT  117.36 205.951 121.95 206.077 ;
     RECT  123.732 206.069 163.314 206.105 ;
     RECT  123.732 206.105 163.242 206.113 ;
     RECT  117.36 206.077 122.418 206.213 ;
     RECT  120.24 206.213 122.418 206.375 ;
     RECT  120.24 206.375 121.95 206.381 ;
     RECT  123.264 206.113 163.242 206.483 ;
     RECT  117.36 206.213 119.322 206.609 ;
     RECT  118.152 206.609 119.322 206.645 ;
     RECT  117.36 206.609 117.378 206.765 ;
     RECT  123.876 206.483 163.242 206.879 ;
     RECT  2.34 205.979 2.697 206.915 ;
     RECT  115.815 204.989 116.097 207.031 ;
     RECT  118.332 206.645 119.322 207.031 ;
     RECT  120.24 206.381 121.914 207.031 ;
     RECT  115.815 207.031 116.37 207.149 ;
     RECT  117.144 207.031 117.162 207.149 ;
     RECT  118.332 207.031 121.914 207.293 ;
     RECT  115.815 207.149 116.226 207.329 ;
     RECT  118.728 207.293 121.914 207.499 ;
     RECT  118.728 207.499 122.49 207.571 ;
     RECT  118.728 207.571 122.562 207.697 ;
     RECT  123.876 206.879 163.206 207.697 ;
     RECT  117.684 208.075 117.702 208.111 ;
     RECT  118.728 207.697 163.206 208.111 ;
     RECT  3.672 205.979 3.69 208.139 ;
     RECT  117.684 208.111 117.882 208.229 ;
     RECT  117.684 208.229 117.702 208.345 ;
     RECT  117.504 208.345 117.702 208.373 ;
     RECT  118.656 208.111 163.206 208.499 ;
     RECT  118.656 208.499 163.17 208.643 ;
     RECT  2.415 206.915 2.697 208.651 ;
     RECT  2.415 208.651 3.33 208.769 ;
     RECT  117.504 208.373 117.666 208.769 ;
     RECT  124.092 208.643 163.17 208.769 ;
     RECT  0.108 205.003 0.126 208.805 ;
     RECT  124.092 208.769 163.062 209.039 ;
     RECT  118.656 208.643 123.318 209.309 ;
     RECT  124.092 209.039 162.954 209.309 ;
     RECT  124.092 209.309 162.45 209.357 ;
     RECT  124.092 209.357 162.378 209.489 ;
     RECT  162.324 209.489 162.378 209.579 ;
     RECT  118.656 209.309 122.814 209.615 ;
     RECT  162.324 209.579 162.342 209.615 ;
     RECT  118.656 209.615 122.562 209.821 ;
     RECT  124.092 209.489 161.226 209.849 ;
     RECT  117.504 208.769 117.522 209.885 ;
     RECT  118.584 209.821 122.562 210.119 ;
     RECT  124.092 209.849 161.154 210.119 ;
     RECT  118.584 210.119 122.238 210.227 ;
     RECT  118.584 210.227 122.13 210.389 ;
     RECT  118.584 210.389 121.497 210.433 ;
     RECT  118.296 210.433 121.497 210.533 ;
     RECT  118.98 210.533 121.497 210.965 ;
     RECT  118.98 210.965 120.33 211.037 ;
     RECT  118.98 211.037 120.114 211.109 ;
     RECT  118.98 211.109 120.006 211.199 ;
     RECT  118.98 211.199 119.178 211.235 ;
     RECT  119.124 211.235 119.178 211.307 ;
     RECT  119.988 211.199 120.006 211.307 ;
     RECT  119.124 211.307 119.142 211.343 ;
     RECT  124.092 210.119 161.118 211.379 ;
     RECT  124.092 211.379 129.402 211.483 ;
     RECT  130.212 211.379 161.118 211.505 ;
     RECT  124.056 211.483 129.402 211.811 ;
     RECT  130.212 211.505 160.938 212.189 ;
     RECT  124.092 211.811 129.402 212.359 ;
     RECT  130.212 212.189 156.834 212.359 ;
     RECT  124.092 212.359 156.834 212.819 ;
     RECT  124.092 212.819 124.182 212.891 ;
     RECT  124.992 212.819 156.834 213.005 ;
     RECT  124.992 213.005 125.118 213.161 ;
     RECT  125.892 213.005 156.834 213.241 ;
     RECT  157.644 212.189 160.938 213.241 ;
     RECT  125.1 213.161 125.118 213.781 ;
     RECT  125.892 213.241 160.938 213.781 ;
     RECT  125.1 213.781 160.938 214.051 ;
     RECT  124.092 212.891 124.11 214.315 ;
     RECT  125.064 214.051 160.938 214.315 ;
     RECT  124.092 214.315 160.938 214.439 ;
     RECT  124.092 214.439 160.398 214.507 ;
     RECT  124.02 214.507 160.398 214.619 ;
     RECT  124.092 214.619 160.398 214.979 ;
     RECT  124.092 214.979 160.29 215.321 ;
     RECT  124.092 215.321 129.294 215.453 ;
     RECT  130.212 215.321 160.29 215.789 ;
     RECT  125.1 215.453 129.294 215.969 ;
     RECT  125.892 215.969 129.294 216.067 ;
     RECT  130.212 215.789 160.074 216.067 ;
     RECT  125.892 216.067 160.074 216.095 ;
     RECT  126.54 216.095 160.074 216.329 ;
     RECT  126.54 216.329 159.786 216.841 ;
     RECT  125.1 215.969 125.118 216.949 ;
     RECT  125.892 216.841 159.786 216.949 ;
     RECT  125.1 216.949 159.786 218.093 ;
     RECT  125.928 218.093 159.786 218.219 ;
     RECT  126.108 218.219 159.786 218.255 ;
     RECT  124.092 215.453 124.11 218.299 ;
     RECT  124.092 218.299 124.182 218.327 ;
     RECT  124.164 218.327 124.182 218.443 ;
     RECT  124.164 218.443 124.218 218.489 ;
     RECT  125.1 218.093 125.118 218.497 ;
     RECT  124.992 218.497 125.118 218.561 ;
     RECT  124.164 218.489 124.182 218.669 ;
     RECT  124.992 218.561 125.01 218.795 ;
     RECT  126.468 218.255 159.786 219.019 ;
     RECT  126.396 219.019 159.786 219.065 ;
     RECT  126.504 219.065 159.786 219.101 ;
     RECT  126.615 219.101 159.786 219.443 ;
     RECT  126.615 219.443 156.726 219.569 ;
     RECT  157.464 219.443 159.786 220.379 ;
     RECT  155.628 219.569 156.726 220.495 ;
     RECT  157.464 220.379 159.354 220.495 ;
     RECT  155.628 220.495 159.354 220.523 ;
     RECT  126.615 219.569 154.89 220.531 ;
     RECT  155.628 220.523 156.222 220.531 ;
     RECT  126.615 220.531 156.222 220.559 ;
     RECT  157.356 220.523 159.354 221.269 ;
     RECT  157.284 221.269 159.354 221.305 ;
     RECT  126.615 220.559 156.186 221.341 ;
     RECT  157.104 221.305 159.354 221.341 ;
     RECT  126.615 221.341 159.354 221.603 ;
     RECT  126.615 221.603 155.214 221.729 ;
     RECT  156.024 221.603 159.354 221.729 ;
     RECT  126.615 221.729 127.17 221.789 ;
     RECT  156.024 221.729 156.222 221.999 ;
     RECT  157.356 221.729 159.354 221.999 ;
     RECT  157.356 221.999 159.297 222.269 ;
     RECT  127.908 221.729 155.214 222.421 ;
     RECT  156.204 221.999 156.222 222.539 ;
     RECT  157.86 222.269 157.878 222.539 ;
     RECT  127.908 222.421 155.394 222.575 ;
     RECT  126.615 221.789 126.897 222.691 ;
     RECT  127.908 222.575 155.322 222.691 ;
     RECT  126.615 222.691 155.322 222.845 ;
     RECT  128.376 222.845 155.322 223.223 ;
     RECT  128.376 223.223 154.854 223.591 ;
     RECT  128.052 223.591 154.854 223.619 ;
     RECT  128.052 223.619 154.818 224.011 ;
     RECT  127.836 224.011 154.818 224.699 ;
     RECT  127.836 224.699 154.746 225.005 ;
     RECT  128.124 225.005 129.438 225.041 ;
     RECT  128.124 225.041 128.142 225.053 ;
     RECT  128.88 225.041 128.898 225.275 ;
     RECT  130.284 225.005 154.746 225.779 ;
     RECT  130.284 225.779 154.53 225.931 ;
     RECT  130.176 225.931 154.53 226.121 ;
     RECT  130.176 226.121 154.494 226.205 ;
     RECT  129.348 226.165 129.366 226.291 ;
     RECT  130.176 226.205 154.422 226.291 ;
     RECT  129.168 226.291 154.422 226.315 ;
     RECT  128.592 226.315 154.422 226.391 ;
     RECT  129.168 226.391 154.422 226.589 ;
     RECT  129.312 226.589 154.422 227.407 ;
     RECT  129.204 227.407 154.422 227.551 ;
     RECT  128.844 227.551 154.422 227.611 ;
     RECT  128.52 227.611 154.422 227.669 ;
     RECT  128.844 227.669 154.422 227.849 ;
     RECT  129.276 227.849 154.422 228.083 ;
     RECT  129.276 228.083 150.138 228.749 ;
     RECT  151.056 228.083 154.422 228.749 ;
     RECT  129.96 228.749 150.138 228.785 ;
     RECT  130.392 228.785 150.138 228.821 ;
     RECT  151.056 228.749 153.897 228.929 ;
     RECT  130.644 228.821 150.138 229.027 ;
     RECT  151.056 228.929 152.838 229.027 ;
     RECT  130.644 229.027 152.838 229.289 ;
     RECT  130.644 229.289 150.462 229.325 ;
     RECT  151.2 229.289 152.478 229.361 ;
     RECT  151.632 229.361 152.154 229.559 ;
     RECT  151.632 229.559 151.65 229.631 ;
     RECT  130.644 229.325 150.21 229.973 ;
     RECT  129.744 229.801 129.762 230.099 ;
     RECT  130.644 229.973 149.922 230.207 ;
     RECT  130.86 230.207 149.922 230.405 ;
     RECT  130.86 230.405 149.85 231.457 ;
     RECT  130.284 231.457 149.85 231.521 ;
     RECT  133.992 231.521 149.85 231.871 ;
     RECT  150.768 231.601 150.786 231.871 ;
     RECT  133.992 231.871 150.786 231.989 ;
     RECT  133.992 231.989 150.318 232.025 ;
     RECT  130.284 231.521 133.218 232.061 ;
     RECT  133.992 232.025 150.066 232.169 ;
     RECT  130.392 232.061 133.218 232.501 ;
     RECT  133.992 232.169 149.346 232.501 ;
     RECT  130.392 232.501 149.346 232.673 ;
     RECT  130.392 232.673 149.202 232.799 ;
     RECT  130.392 232.799 134.838 232.843 ;
     RECT  130.248 232.843 134.838 232.915 ;
     RECT  135.612 232.799 149.202 232.943 ;
     RECT  129.312 232.915 129.33 232.951 ;
     RECT  130.14 232.915 134.838 232.951 ;
     RECT  129.312 232.951 134.838 232.973 ;
     RECT  135.972 232.943 149.202 233.491 ;
     RECT  135.972 233.491 149.382 233.653 ;
     RECT  135.972 233.653 149.886 233.689 ;
     RECT  129.42 232.973 134.73 233.717 ;
     RECT  130.536 233.717 134.73 233.761 ;
     RECT  135.972 233.689 150.354 233.879 ;
     RECT  130.536 233.761 134.802 233.887 ;
     RECT  135.972 233.879 149.886 233.887 ;
     RECT  130.536 233.887 149.886 233.987 ;
     RECT  149.868 233.987 149.886 234.023 ;
     RECT  130.536 233.987 149.094 234.029 ;
     RECT  129.42 233.717 129.798 234.031 ;
     RECT  129.384 234.031 129.798 234.563 ;
     RECT  129.42 234.563 129.798 234.571 ;
     RECT  130.536 234.029 149.058 234.571 ;
     RECT  129.42 234.571 149.058 234.805 ;
     RECT  129.42 234.805 149.13 235.309 ;
     RECT  129.42 235.309 149.418 235.499 ;
     RECT  129.42 235.499 149.31 235.921 ;
     RECT  129.384 235.921 149.31 235.949 ;
     RECT  129.384 235.949 148.842 236.333 ;
     RECT  129.42 236.333 148.842 236.965 ;
     RECT  129.42 236.965 149.202 237.091 ;
     RECT  129.42 237.091 149.31 237.541 ;
     RECT  129.42 237.541 149.382 237.631 ;
     RECT  129.348 237.631 149.382 237.659 ;
     RECT  129.348 237.659 135.054 237.695 ;
     RECT  129.348 237.695 134.658 237.739 ;
     RECT  129.204 237.739 134.658 237.803 ;
     RECT  129.312 237.803 134.658 238.199 ;
     RECT  129.312 238.199 129.366 238.343 ;
     RECT  136.008 237.659 141.894 238.441 ;
     RECT  142.632 237.659 149.346 238.441 ;
     RECT  130.104 238.199 134.658 238.469 ;
     RECT  130.428 238.469 134.658 238.505 ;
     RECT  136.008 238.441 149.346 238.505 ;
     RECT  129.348 238.343 129.366 238.541 ;
     RECT  130.5 238.505 134.658 238.541 ;
     RECT  136.008 238.505 149.31 238.549 ;
     RECT  130.716 238.541 134.658 238.783 ;
     RECT  135.396 238.549 149.31 238.783 ;
     RECT  130.716 238.783 149.31 238.811 ;
     RECT  130.716 238.811 139.158 239.069 ;
     RECT  130.932 239.069 139.158 239.081 ;
     RECT  130.932 239.081 133.578 239.279 ;
     RECT  130.932 239.279 133.002 239.549 ;
     RECT  134.64 239.081 139.158 239.629 ;
     RECT  139.896 238.811 149.31 239.629 ;
     RECT  134.64 239.629 149.31 239.701 ;
     RECT  134.64 239.701 149.706 239.819 ;
     RECT  134.64 239.819 149.274 239.963 ;
     RECT  134.64 239.963 149.238 240.089 ;
     RECT  134.64 240.089 148.662 240.125 ;
     RECT  134.64 240.125 148.497 240.269 ;
     RECT  135.936 240.269 148.497 240.395 ;
     RECT  136.116 240.395 148.497 240.467 ;
     RECT  147.78 240.467 148.497 240.503 ;
     RECT  134.64 240.269 135.198 240.557 ;
     RECT  136.116 240.467 146.97 240.665 ;
     RECT  136.152 240.665 146.97 240.809 ;
     RECT  136.8 240.809 146.97 240.899 ;
     RECT  136.8 240.899 146.538 240.971 ;
     RECT  137.088 240.971 146.538 241.007 ;
     RECT  146.52 241.007 146.538 241.169 ;
     RECT  137.415 241.007 145.17 241.241 ;
     RECT  137.415 241.241 143.097 241.325 ;
     RECT  140.004 241.325 143.097 241.349 ;
     RECT  137.415 241.325 139.014 241.439 ;
     RECT  137.415 241.439 138.546 241.547 ;
     RECT  137.415 241.547 137.754 241.583 ;
     RECT  138.528 241.547 138.546 241.709 ;
     RECT  140.148 241.349 143.097 242.131 ;
     RECT  143.892 241.241 145.17 242.131 ;
     RECT  139.824 242.131 143.097 242.249 ;
     RECT  139.824 242.249 140.49 242.257 ;
     RECT  138.852 242.299 138.87 242.491 ;
     RECT  139.68 242.257 140.49 242.491 ;
     RECT  138.852 242.491 140.49 242.555 ;
     RECT  138.852 242.555 140.31 242.591 ;
     RECT  130.932 239.549 132.297 242.627 ;
     RECT  131.652 242.627 132.297 242.629 ;
     RECT  131.652 242.629 132.39 242.669 ;
     RECT  143.892 242.131 145.278 242.671 ;
     RECT  143.856 242.671 145.278 242.789 ;
     RECT  143.856 242.789 143.874 242.825 ;
     RECT  144.72 242.789 144.918 242.861 ;
     RECT  144.9 242.861 144.918 243.095 ;
     RECT  139.032 242.591 140.31 243.481 ;
     RECT  138.708 243.481 140.598 243.643 ;
     RECT  141.336 242.249 143.097 243.643 ;
     RECT  138.708 243.643 143.097 243.869 ;
     RECT  138.78 243.869 142.038 243.941 ;
     RECT  138.78 243.941 141.642 244.139 ;
     RECT  139.644 244.139 141.498 244.409 ;
     RECT  138.78 244.139 138.798 244.445 ;
     RECT  140.004 244.409 140.958 244.445 ;
     RECT  140.004 244.445 140.022 244.451 ;
     RECT  140.796 244.445 140.958 244.481 ;
     RECT  140.796 244.481 140.814 244.715 ;
     RECT  134.64 240.557 134.658 248.729 ;
     RECT  136.26 275.323 136.278 275.459 ;
     RECT  135.324 275.539 135.342 275.645 ;
     RECT  131.652 242.669 132.297 291.929 ;
     RECT  132.015 291.929 132.297 292.081 ;
     RECT  2.415 208.769 2.697 369.107 ;
     RECT  7.815 2.413 8.097 369.107 ;
     RECT  13.215 2.413 13.497 369.107 ;
     RECT  18.615 2.413 18.897 369.107 ;
     RECT  24.015 2.413 24.297 369.107 ;
     RECT  29.415 2.413 29.697 369.107 ;
     RECT  34.815 2.413 35.097 369.107 ;
     RECT  40.215 2.413 40.497 369.107 ;
     RECT  45.615 198.779 45.897 369.107 ;
     RECT  51.015 2.413 51.297 369.107 ;
     RECT  56.415 2.413 56.697 369.107 ;
     RECT  61.815 2.413 62.097 369.107 ;
     RECT  67.215 2.413 67.497 369.107 ;
     RECT  72.615 2.413 72.897 369.107 ;
     RECT  78.015 2.413 78.297 369.107 ;
     RECT  83.415 2.413 83.697 369.107 ;
     RECT  88.815 2.413 89.097 369.107 ;
     RECT  94.215 2.413 94.497 369.107 ;
     RECT  99.615 2.413 99.897 369.107 ;
     RECT  105.015 2.413 105.297 369.107 ;
     RECT  110.415 2.413 110.697 369.107 ;
     RECT  115.815 207.329 116.097 369.107 ;
     RECT  121.215 210.965 121.497 369.107 ;
     RECT  126.615 222.845 126.897 369.107 ;
     RECT  137.415 241.583 137.697 369.107 ;
     RECT  142.815 243.869 143.097 369.107 ;
     RECT  148.215 240.503 148.497 369.107 ;
     RECT  153.615 228.929 153.897 369.107 ;
     RECT  159.015 222.269 159.297 369.107 ;
     RECT  164.415 192.989 164.697 369.107 ;
     RECT  169.815 2.413 170.097 369.107 ;
     RECT  175.215 179.357 175.497 369.107 ;
     RECT  180.615 2.413 180.897 369.107 ;
     RECT  186.015 179.357 186.297 369.107 ;
     RECT  191.415 2.413 191.697 369.107 ;
     RECT  196.815 179.357 197.097 369.107 ;
     RECT  202.215 2.413 202.497 369.107 ;
     RECT  207.615 179.357 207.897 369.107 ;
     RECT  213.015 2.413 213.297 369.107 ;
     RECT  218.415 179.357 218.697 369.107 ;
     RECT  223.815 2.413 224.097 369.107 ;
     RECT  229.215 179.357 229.497 369.107 ;
     RECT  234.615 2.413 234.897 369.107 ;
     RECT  240.015 179.357 240.297 369.107 ;
     RECT  245.415 193.289 245.697 369.107 ;
     RECT  2.415 369.107 2.505 369.377 ;
     RECT  7.815 369.107 7.905 369.377 ;
     RECT  13.215 369.107 13.305 369.377 ;
     RECT  18.615 369.107 18.705 369.377 ;
     RECT  24.015 369.107 24.105 369.377 ;
     RECT  29.415 369.107 29.505 369.377 ;
     RECT  34.815 369.107 34.905 369.377 ;
     RECT  40.215 369.107 40.305 369.377 ;
     RECT  45.615 369.107 45.705 369.377 ;
     RECT  51.015 369.107 51.105 369.377 ;
     RECT  56.415 369.107 56.505 369.377 ;
     RECT  61.815 369.107 61.905 369.377 ;
     RECT  67.215 369.107 67.305 369.377 ;
     RECT  72.615 369.107 72.705 369.377 ;
     RECT  78.015 369.107 78.105 369.377 ;
     RECT  83.415 369.107 83.505 369.377 ;
     RECT  88.815 369.107 88.905 369.377 ;
     RECT  94.215 369.107 94.305 369.377 ;
     RECT  99.615 369.107 99.705 369.377 ;
     RECT  105.015 369.107 105.105 369.377 ;
     RECT  110.415 369.107 110.505 369.377 ;
     RECT  115.815 369.107 115.905 369.377 ;
     RECT  121.215 369.107 121.305 369.377 ;
     RECT  126.615 369.107 126.705 369.377 ;
     RECT  132.015 292.081 132.39 369.377 ;
     RECT  137.415 369.107 137.505 369.377 ;
     RECT  142.815 369.107 142.905 369.377 ;
     RECT  148.215 369.107 148.305 369.377 ;
     RECT  153.615 369.107 153.705 369.377 ;
     RECT  159.015 369.107 159.105 369.377 ;
     RECT  164.415 369.107 164.505 369.377 ;
     RECT  169.815 369.107 169.905 369.377 ;
     RECT  175.215 369.107 175.305 369.377 ;
     RECT  180.615 369.107 180.705 369.377 ;
     RECT  186.015 369.107 186.105 369.377 ;
     RECT  191.415 369.107 191.505 369.377 ;
     RECT  196.815 369.107 196.905 369.377 ;
     RECT  202.215 369.107 202.305 369.377 ;
     RECT  207.615 369.107 207.705 369.377 ;
     RECT  213.015 369.107 213.105 369.377 ;
     RECT  218.415 369.107 218.505 369.377 ;
     RECT  223.815 369.107 223.905 369.377 ;
     RECT  229.215 369.107 229.305 369.377 ;
     RECT  234.615 369.107 234.705 369.377 ;
     RECT  240.015 369.107 240.105 369.377 ;
     RECT  245.415 369.107 245.505 369.377 ;
     RECT  132.372 369.377 132.39 371.213 ;
     RECT  133.128 248.881 133.146 371.405 ;
    LAYER M4 ;
     RECT  0.06 172.656 2.408 175.656 ;
     RECT  0.06 204.72 2.408 205.128 ;
     RECT  2.408 2.148 2.512 369.372 ;
     RECT  2.512 2.418 2.704 369.102 ;
     RECT  2.704 172.944 2.801 175.416 ;
     RECT  2.801 173.136 2.837 175.416 ;
     RECT  2.837 173.52 2.873 175.416 ;
     RECT  2.873 173.52 2.909 175.368 ;
     RECT  2.909 173.712 3.413 175.368 ;
     RECT  3.413 173.712 4.061 174.888 ;
     RECT  4.061 174.288 4.313 174.888 ;
     RECT  4.313 174.864 4.853 174.888 ;
     RECT  7.808 2.148 7.912 369.372 ;
     RECT  7.912 2.418 8.104 369.102 ;
     RECT  13.208 2.148 13.312 369.372 ;
     RECT  13.312 2.418 13.504 369.102 ;
     RECT  18.608 2.148 18.712 369.372 ;
     RECT  18.712 2.418 18.904 369.102 ;
     RECT  24.008 2.148 24.112 369.372 ;
     RECT  24.112 2.418 24.304 369.102 ;
     RECT  29.408 2.148 29.512 369.372 ;
     RECT  29.512 2.418 29.704 369.102 ;
     RECT  34.808 2.148 34.912 369.372 ;
     RECT  34.912 2.418 35.104 369.102 ;
     RECT  40.208 2.148 40.312 369.372 ;
     RECT  40.312 2.418 40.504 369.102 ;
     RECT  45.608 2.148 45.712 369.372 ;
     RECT  45.712 2.418 45.904 369.102 ;
     RECT  51.008 2.148 51.112 369.372 ;
     RECT  51.112 2.418 51.304 369.102 ;
     RECT  56.408 2.148 56.512 369.372 ;
     RECT  56.512 2.418 56.704 369.102 ;
     RECT  61.808 2.148 61.912 369.372 ;
     RECT  61.912 2.418 62.104 369.102 ;
     RECT  67.208 2.148 67.312 369.372 ;
     RECT  67.312 2.418 67.504 369.102 ;
     RECT  72.608 2.148 72.712 369.372 ;
     RECT  72.712 2.418 72.904 369.102 ;
     RECT  78.008 2.148 78.112 369.372 ;
     RECT  78.112 2.418 78.304 369.102 ;
     RECT  83.408 2.148 83.512 369.372 ;
     RECT  83.512 2.418 83.704 369.102 ;
     RECT  88.808 2.148 88.912 369.372 ;
     RECT  88.912 2.418 89.104 369.102 ;
     RECT  94.208 2.148 94.312 369.372 ;
     RECT  94.312 2.418 94.504 369.102 ;
     RECT  99.608 2.148 99.712 369.372 ;
     RECT  99.712 2.418 99.904 369.102 ;
     RECT  105.008 2.148 105.112 369.372 ;
     RECT  105.112 2.418 105.304 369.102 ;
     RECT  110.408 2.148 110.512 369.372 ;
     RECT  110.512 2.418 110.704 369.102 ;
     RECT  113.425 175.152 113.821 175.176 ;
     RECT  113.137 172.656 114.041 172.68 ;
     RECT  114.044 191.904 114.131 191.928 ;
     RECT  114.073 189.792 114.157 189.816 ;
     RECT  113.641 197.088 114.653 197.112 ;
     RECT  113.821 198.768 114.829 198.792 ;
     RECT  113.821 174.336 115.153 175.176 ;
     RECT  114.829 198.768 115.429 199.464 ;
     RECT  115.429 198.768 115.477 200.328 ;
     RECT  115.477 198.288 115.585 200.328 ;
     RECT  115.657 181.872 115.693 181.896 ;
     RECT  114.325 183.12 115.693 183.144 ;
     RECT  115.261 163.536 115.808 163.56 ;
     RECT  115.045 165.888 115.808 165.912 ;
     RECT  115.045 171.888 115.808 171.912 ;
     RECT  115.153 173.52 115.808 175.176 ;
     RECT  115.693 181.872 115.808 183.144 ;
     RECT  114.085 194.928 115.808 194.952 ;
     RECT  115.189 196.656 115.808 196.68 ;
     RECT  115.585 198.048 115.808 200.328 ;
     RECT  115.117 201.744 115.808 201.768 ;
     RECT  115.333 202.944 115.808 202.968 ;
     RECT  115.808 2.148 115.912 369.372 ;
     RECT  115.912 2.418 116.104 369.102 ;
     RECT  116.104 181.248 116.243 183.528 ;
     RECT  116.104 184.656 116.243 184.68 ;
     RECT  116.104 187.536 116.243 187.56 ;
     RECT  116.243 181.248 116.245 182.04 ;
     RECT  116.104 165.888 116.291 165.912 ;
     RECT  116.104 163.008 116.332 164.664 ;
     RECT  116.104 169.248 116.345 173.592 ;
     RECT  116.104 177.072 116.381 180.168 ;
     RECT  116.381 177.072 116.669 179.592 ;
     RECT  116.245 182.016 116.741 182.04 ;
     RECT  116.104 193.488 116.749 194.424 ;
     RECT  116.345 169.248 116.867 172.584 ;
     RECT  116.749 193.488 116.885 193.608 ;
     RECT  116.867 170.16 116.913 172.584 ;
     RECT  116.104 175.824 116.915 175.992 ;
     RECT  116.669 177.072 116.915 179.304 ;
     RECT  116.913 170.16 116.921 171 ;
     RECT  116.915 177.072 116.957 177.096 ;
     RECT  116.243 183.12 117.029 183.528 ;
     RECT  116.921 170.976 117.065 171 ;
     RECT  116.915 178.368 117.065 178.392 ;
     RECT  116.104 198.912 117.205 199.704 ;
     RECT  116.104 207.264 117.308 207.288 ;
     RECT  116.332 163.008 117.313 163.992 ;
     RECT  117.205 198.912 117.313 200.664 ;
     RECT  116.104 205.728 117.349 205.752 ;
     RECT  117.308 206.736 117.349 207.288 ;
     RECT  116.104 196.656 117.385 196.68 ;
     RECT  116.104 191.184 117.452 191.208 ;
     RECT  116.104 190.032 117.493 190.056 ;
     RECT  117.452 191.184 117.493 191.4 ;
     RECT  117.349 205.728 117.497 207.288 ;
     RECT  117.385 196.656 117.539 196.968 ;
     RECT  117.313 163.008 117.565 164.904 ;
     RECT  116.104 186.336 117.565 186.36 ;
     RECT  117.205 187.44 117.565 187.464 ;
     RECT  117.277 161.328 117.637 161.352 ;
     RECT  117.565 162.768 117.641 164.904 ;
     RECT  117.497 207.264 117.673 207.288 ;
     RECT  117.313 198.912 117.677 200.712 ;
     RECT  117.493 190.032 117.745 191.496 ;
     RECT  117.677 199.68 117.785 200.712 ;
     RECT  117.785 199.68 117.857 200.664 ;
     RECT  117.641 162.768 117.889 163.8 ;
     RECT  117.889 162.48 117.925 163.8 ;
     RECT  116.104 201.792 117.925 202.968 ;
     RECT  117.097 168.672 117.935 168.696 ;
     RECT  117.637 160.704 117.971 161.352 ;
     RECT  117.745 188.64 117.971 191.496 ;
     RECT  117.853 204.624 117.971 204.648 ;
     RECT  117.673 207.264 117.971 208.104 ;
     RECT  117.935 168.672 117.973 169.56 ;
     RECT  116.915 175.824 117.973 175.848 ;
     RECT  117.973 168.672 118.001 170.472 ;
     RECT  117.565 186.336 118.019 187.464 ;
     RECT  117.973 174.96 118.021 175.848 ;
     RECT  117.925 201.792 118.033 203.208 ;
     RECT  118.033 201.792 118.073 203.4 ;
     RECT  118.021 174.96 118.105 176.616 ;
     RECT  118.105 174.816 118.108 176.616 ;
     RECT  117.853 179.568 118.109 179.592 ;
     RECT  117.973 184.656 118.109 184.68 ;
     RECT  117.971 188.64 118.145 189.48 ;
     RECT  117.029 183.12 118.177 183.144 ;
     RECT  117.497 205.728 118.177 205.752 ;
     RECT  118.001 169.536 118.217 170.472 ;
     RECT  118.177 205.2 118.217 205.752 ;
     RECT  117.971 207.264 118.361 207.288 ;
     RECT  118.019 186.912 118.393 187.464 ;
     RECT  117.971 190.752 118.397 191.496 ;
     RECT  118.108 174.816 118.403 175.848 ;
     RECT  117.493 194.736 118.429 194.76 ;
     RECT  118.073 201.792 118.469 202.152 ;
     RECT  117.971 160.704 118.577 160.824 ;
     RECT  116.913 172.464 118.609 172.584 ;
     RECT  118.429 194.736 118.681 195.096 ;
     RECT  117.539 196.944 118.681 196.968 ;
     RECT  117.925 162.336 118.685 163.8 ;
     RECT  118.393 186.912 118.685 188.04 ;
     RECT  118.249 185.04 118.721 185.064 ;
     RECT  118.681 194.736 118.721 196.968 ;
     RECT  118.685 187.44 118.757 188.04 ;
     RECT  118.403 174.816 118.789 175.704 ;
     RECT  116.885 193.584 118.789 193.608 ;
     RECT  118.721 194.736 118.789 195 ;
     RECT  117.781 198.336 118.825 198.36 ;
     RECT  117.857 199.68 118.825 200.616 ;
     RECT  118.397 191.472 118.829 191.496 ;
     RECT  118.789 193.584 118.835 195 ;
     RECT  118.577 160.704 118.865 160.728 ;
     RECT  117.641 164.88 118.865 164.904 ;
     RECT  118.145 189.456 118.865 189.48 ;
     RECT  118.609 167.568 119.005 167.592 ;
     RECT  118.033 181.488 119.041 181.512 ;
     RECT  118.685 163.776 119.077 163.8 ;
     RECT  119.041 180.768 119.125 181.512 ;
     RECT  118.177 182.928 119.125 183.144 ;
     RECT  118.835 194.544 119.153 195 ;
     RECT  118.073 203.184 119.189 203.4 ;
     RECT  118.217 205.2 119.189 205.272 ;
     RECT  116.345 173.568 119.225 173.592 ;
     RECT  118.469 202.128 119.225 202.152 ;
     RECT  118.609 172.032 119.257 172.584 ;
     RECT  118.217 169.536 119.297 170.424 ;
     RECT  118.573 177.168 119.329 177.192 ;
     RECT  117.745 166.416 119.365 166.44 ;
     RECT  119.005 167.568 119.365 168.552 ;
     RECT  118.789 174.576 119.365 175.704 ;
     RECT  119.041 185.28 119.369 185.832 ;
     RECT  119.077 163.776 119.405 164.616 ;
     RECT  118.501 179.328 119.405 179.352 ;
     RECT  119.125 180.432 119.405 183.144 ;
     RECT  118.825 198.336 119.405 200.616 ;
     RECT  118.685 162.336 119.411 162.792 ;
     RECT  119.329 177.168 119.473 177.768 ;
     RECT  118.757 187.728 119.473 188.04 ;
     RECT  119.405 198.336 119.507 199.608 ;
     RECT  119.189 205.2 119.513 205.224 ;
     RECT  119.516 189.792 119.557 189.816 ;
     RECT  119.405 200.592 119.581 200.616 ;
     RECT  119.365 166.416 119.585 168.552 ;
     RECT  119.473 187.728 119.603 188.424 ;
     RECT  119.557 189.792 119.603 190.44 ;
     RECT  119.257 171.6 119.651 172.584 ;
     RECT  119.651 171.6 119.657 172.056 ;
     RECT  119.603 187.728 119.657 187.752 ;
     RECT  119.585 168.24 119.685 168.264 ;
     RECT  119.585 166.416 119.689 166.776 ;
     RECT  119.581 200.592 119.699 200.712 ;
     RECT  119.297 170.4 119.729 170.424 ;
     RECT  119.405 180.576 119.729 183.144 ;
     RECT  119.507 198.48 119.729 199.608 ;
     RECT  119.729 199.104 119.74 199.608 ;
     RECT  117.961 159.024 119.761 159.048 ;
     RECT  119.699 200.688 119.765 200.712 ;
     RECT  119.761 159.024 119.801 159.768 ;
     RECT  119.657 172.032 119.837 172.056 ;
     RECT  118.721 196.032 119.837 196.968 ;
     RECT  119.437 193.152 119.905 193.176 ;
     RECT  119.837 196.944 119.945 196.968 ;
     RECT  119.365 174.576 120.013 176.136 ;
     RECT  119.473 177.168 120.013 177.816 ;
     RECT  119.405 163.92 120.037 164.616 ;
     RECT  119.689 165.888 120.037 166.776 ;
     RECT  119.473 208.08 120.049 208.104 ;
     RECT  119.473 161.856 120.083 161.88 ;
     RECT  120.037 163.92 120.083 166.776 ;
     RECT  119.153 194.736 120.125 195 ;
     RECT  119.473 191.856 120.161 191.88 ;
     RECT  120.013 174.576 120.181 177.816 ;
     RECT  118.897 209.904 120.193 209.928 ;
     RECT  120.083 164.592 120.197 166.776 ;
     RECT  120.181 174.576 120.227 178.584 ;
     RECT  120.197 164.592 120.233 164.616 ;
     RECT  120.193 209.376 120.233 209.928 ;
     RECT  119.905 169.248 120.277 169.272 ;
     RECT  120.049 207.456 120.373 208.104 ;
     RECT  120.233 209.376 120.373 209.88 ;
     RECT  119.905 193.152 120.476 193.368 ;
     RECT  120.125 194.736 120.476 194.856 ;
     RECT  120.476 193.152 120.517 194.856 ;
     RECT  119.369 185.28 120.62 185.304 ;
     RECT  120.62 184.704 120.661 185.304 ;
     RECT  120.049 186.912 120.661 186.936 ;
     RECT  120.227 174.576 120.733 176.136 ;
     RECT  120.227 177.216 120.769 178.584 ;
     RECT  120.764 201.792 120.769 201.816 ;
     RECT  120.197 165.888 120.841 166.776 ;
     RECT  119.801 159.744 121.093 159.768 ;
     RECT  120.769 201.792 121.093 202.008 ;
     RECT  119.189 203.184 121.093 203.208 ;
     RECT  121.093 158.928 121.208 159.768 ;
     RECT  121.021 161.568 121.208 161.592 ;
     RECT  120.985 163.536 121.208 163.56 ;
     RECT  120.841 165.888 121.208 167.592 ;
     RECT  120.277 169.248 121.208 170.328 ;
     RECT  120.733 173.76 121.208 176.136 ;
     RECT  120.769 177.216 121.208 179.208 ;
     RECT  119.729 180.576 121.208 181.272 ;
     RECT  119.729 182.688 121.208 183.144 ;
     RECT  120.661 184.224 121.208 186.936 ;
     RECT  119.603 190.416 121.208 190.44 ;
     RECT  120.476 192 121.208 192.024 ;
     RECT  120.517 193.104 121.208 194.856 ;
     RECT  119.74 199.392 121.208 199.608 ;
     RECT  120.733 200.592 121.208 200.616 ;
     RECT  121.093 201.792 121.208 203.208 ;
     RECT  120.985 204.72 121.208 205.128 ;
     RECT  120.841 206.352 121.208 206.376 ;
     RECT  120.373 207.456 121.208 209.88 ;
     RECT  121.208 2.148 121.312 369.372 ;
     RECT  121.312 2.418 121.504 369.102 ;
     RECT  121.504 194.4 121.601 194.856 ;
     RECT  121.504 190.944 121.619 191.784 ;
     RECT  121.504 204.72 121.637 205.128 ;
     RECT  121.504 180.576 121.745 182.088 ;
     RECT  121.504 173.376 121.781 174.84 ;
     RECT  121.504 184.224 121.925 184.248 ;
     RECT  121.504 206.352 121.961 206.376 ;
     RECT  121.504 193.152 122.033 193.176 ;
     RECT  121.504 208.512 122.051 210.024 ;
     RECT  122.051 208.512 122.213 208.584 ;
     RECT  121.504 169.824 122.243 171.384 ;
     RECT  121.504 166.896 122.357 167.592 ;
     RECT  121.504 160.464 122.429 160.584 ;
     RECT  121.504 163.536 122.497 163.56 ;
     RECT  121.504 168.672 122.497 168.696 ;
     RECT  122.243 169.824 122.531 170.328 ;
     RECT  121.745 180.576 122.533 181.8 ;
     RECT  122.497 168.576 122.537 168.696 ;
     RECT  121.781 173.376 122.537 174.744 ;
     RECT  121.504 185.568 122.537 186.216 ;
     RECT  122.537 174.72 122.545 174.744 ;
     RECT  121.504 207.504 122.545 207.528 ;
     RECT  122.429 160.56 122.569 160.584 ;
     RECT  121.504 187.728 122.569 189.864 ;
     RECT  122.243 171.36 122.573 171.384 ;
     RECT  121.504 196.608 122.573 198.312 ;
     RECT  122.569 160.56 122.579 160.776 ;
     RECT  121.504 161.808 122.609 162.456 ;
     RECT  122.569 187.728 122.609 190.392 ;
     RECT  121.619 191.76 122.609 191.784 ;
     RECT  122.533 159.552 122.645 159.576 ;
     RECT  121.504 176.112 122.677 176.136 ;
     RECT  121.601 194.4 122.677 194.76 ;
     RECT  121.504 177.168 122.681 178.2 ;
     RECT  121.637 204.72 122.749 204.744 ;
     RECT  122.609 187.728 122.753 189 ;
     RECT  121.504 165.312 122.821 165.336 ;
     RECT  122.357 166.896 122.821 166.92 ;
     RECT  122.609 190.368 122.825 190.392 ;
     RECT  122.533 180.192 122.897 181.8 ;
     RECT  122.579 160.752 122.929 160.776 ;
     RECT  122.609 161.808 122.929 162.12 ;
     RECT  122.573 196.608 122.969 197.832 ;
     RECT  122.969 197.712 123.041 197.832 ;
     RECT  122.897 181.104 123.073 181.8 ;
     RECT  122.213 208.56 123.077 208.584 ;
     RECT  121.504 202.848 123.109 203.208 ;
     RECT  122.749 204.72 123.109 205.128 ;
     RECT  123.041 197.712 123.149 197.736 ;
     RECT  122.821 165.312 123.155 166.92 ;
     RECT  123.109 204.576 123.155 205.128 ;
     RECT  122.929 160.752 123.185 162.12 ;
     RECT  123.109 202.848 123.196 203.448 ;
     RECT  122.497 163.536 123.221 164.328 ;
     RECT  122.753 188.784 123.221 189 ;
     RECT  122.677 193.824 123.257 194.76 ;
     RECT  122.531 169.92 123.289 170.328 ;
     RECT  122.485 206.304 123.293 206.328 ;
     RECT  123.196 202.848 123.325 203.208 ;
     RECT  123.155 204.576 123.329 204.84 ;
     RECT  122.969 196.608 123.395 196.632 ;
     RECT  122.681 178.176 123.401 178.2 ;
     RECT  122.677 176.112 123.541 176.184 ;
     RECT  123.221 163.536 123.545 163.752 ;
     RECT  123.349 199.584 123.548 199.608 ;
     RECT  123.185 160.992 123.577 162.12 ;
     RECT  122.537 168.576 123.577 168.6 ;
     RECT  123.289 169.92 123.577 170.52 ;
     RECT  123.325 202.704 123.589 203.208 ;
     RECT  122.681 177.168 123.617 177.192 ;
     RECT  123.548 199.584 123.635 200.52 ;
     RECT  123.257 194.736 123.649 194.76 ;
     RECT  123.155 165.84 123.685 166.92 ;
     RECT  123.577 160.992 123.689 162.456 ;
     RECT  123.637 173.904 123.724 173.928 ;
     RECT  123.635 199.584 123.761 199.608 ;
     RECT  123.685 165.84 123.769 167.544 ;
     RECT  123.577 168.576 123.788 170.52 ;
     RECT  123.769 165.84 123.797 166.92 ;
     RECT  123.74 164.736 123.827 164.76 ;
     RECT  123.788 168.576 123.875 171.24 ;
     RECT  122.537 185.808 123.937 186.216 ;
     RECT  123.001 187.536 123.937 187.56 ;
     RECT  123.689 160.992 123.941 161.832 ;
     RECT  123.875 169.968 123.941 170.52 ;
     RECT  123.541 175.44 123.941 176.184 ;
     RECT  123.941 170.496 123.977 170.52 ;
     RECT  123.937 185.808 123.977 187.56 ;
     RECT  123.875 168.576 124.013 168.6 ;
     RECT  123.977 186.96 124.021 187.56 ;
     RECT  123.797 166.08 124.049 166.92 ;
     RECT  123.977 185.808 124.081 185.832 ;
     RECT  122.677 172.56 124.117 172.584 ;
     RECT  124.081 185.28 124.121 185.832 ;
     RECT  123.577 159.6 124.153 159.624 ;
     RECT  123.361 208.608 124.165 208.632 ;
     RECT  122.051 210 124.165 210.024 ;
     RECT  124.009 214.512 124.165 214.536 ;
     RECT  124.165 208.608 124.211 210.024 ;
     RECT  124.124 212.832 124.211 212.856 ;
     RECT  124.211 208.608 124.261 209.304 ;
     RECT  124.261 207.456 124.265 209.304 ;
     RECT  124.045 211.488 124.337 211.512 ;
     RECT  124.265 207.456 124.345 208.632 ;
     RECT  124.117 172.08 124.369 172.584 ;
     RECT  124.369 172.08 124.373 173.544 ;
     RECT  124.021 187.536 124.409 187.56 ;
     RECT  123.073 181.104 124.477 182.04 ;
     RECT  123.829 179.232 124.508 179.256 ;
     RECT  124.477 180.672 124.508 182.04 ;
     RECT  124.508 179.232 124.549 182.04 ;
     RECT  124.549 178.656 124.585 182.04 ;
     RECT  121.504 183.12 124.585 183.144 ;
     RECT  124.373 172.56 124.589 173.544 ;
     RECT  124.585 178.656 124.595 183.144 ;
     RECT  124.405 193.536 124.613 193.56 ;
     RECT  124.595 180.096 124.625 183.144 ;
     RECT  124.153 159.6 124.661 160.008 ;
     RECT  124.625 180.096 124.669 182.424 ;
     RECT  124.613 193.2 124.697 193.56 ;
     RECT  123.649 194.736 124.729 195.624 ;
     RECT  124.589 173.52 124.733 173.544 ;
     RECT  124.165 214.32 124.801 214.536 ;
     RECT  124.049 166.08 124.805 166.152 ;
     RECT  123.329 204.816 124.805 204.84 ;
     RECT  124.729 194.736 124.835 196.104 ;
     RECT  124.513 197.232 124.837 197.256 ;
     RECT  124.225 198.528 124.837 198.552 ;
     RECT  123.941 175.44 124.877 176.136 ;
     RECT  124.837 197.232 124.883 197.544 ;
     RECT  124.837 198.528 124.883 198.984 ;
     RECT  124.805 166.128 124.949 166.152 ;
     RECT  124.883 198.96 124.949 198.984 ;
     RECT  123.589 202.32 124.949 203.208 ;
     RECT  124.801 164.784 124.985 164.808 ;
     RECT  124.345 208.608 125.021 208.632 ;
     RECT  124.801 214.32 125.053 215.448 ;
     RECT  124.595 178.656 125.123 178.68 ;
     RECT  125.053 214.08 125.125 215.448 ;
     RECT  125.045 177.216 125.129 177.24 ;
     RECT  125.125 214.08 125.165 215.928 ;
     RECT  123.941 161.808 125.233 161.832 ;
     RECT  124.883 197.52 125.273 197.544 ;
     RECT  124.189 218.448 125.324 218.472 ;
     RECT  125.233 161.28 125.341 161.832 ;
     RECT  125.324 218.064 125.341 218.472 ;
     RECT  125.341 217.728 125.365 218.472 ;
     RECT  125.341 161.136 125.377 161.832 ;
     RECT  125.365 217.728 125.411 219.048 ;
     RECT  125.377 212.544 125.413 212.568 ;
     RECT  125.411 217.728 125.413 217.752 ;
     RECT  124.669 180.096 125.453 182.328 ;
     RECT  124.121 185.28 125.453 185.304 ;
     RECT  125.372 153.168 125.459 153.192 ;
     RECT  125.165 214.08 125.459 214.92 ;
     RECT  125.165 215.904 125.459 215.928 ;
     RECT  125.413 151.584 125.5 151.608 ;
     RECT  124.153 201.024 125.525 201.048 ;
     RECT  124.549 210.384 125.557 210.408 ;
     RECT  123.221 188.784 125.561 188.808 ;
     RECT  125.413 217.2 125.597 217.752 ;
     RECT  124.441 189.888 125.605 189.912 ;
     RECT  125.585 190.944 125.629 190.968 ;
     RECT  125.377 161.04 125.708 161.832 ;
     RECT  123.781 163.104 125.749 163.128 ;
     RECT  125.557 210.144 125.773 210.408 ;
     RECT  125.413 212.544 125.881 213 ;
     RECT  125.605 189.744 125.941 189.912 ;
     RECT  125.629 190.944 125.941 191.496 ;
     RECT  125.941 189.744 125.953 191.496 ;
     RECT  125.413 192.672 125.953 192.696 ;
     RECT  125.773 209.76 125.989 210.84 ;
     RECT  124.835 194.736 126.025 195.144 ;
     RECT  125.453 182.304 126.061 182.328 ;
     RECT  126.025 194.208 126.241 195.144 ;
     RECT  124.877 176.112 126.385 176.136 ;
     RECT  125.453 180.096 126.385 180.696 ;
     RECT  125.989 209.76 126.385 210.984 ;
     RECT  126.349 178.272 126.449 178.296 ;
     RECT  126.313 174.96 126.469 174.984 ;
     RECT  126.385 176.112 126.469 176.904 ;
     RECT  126.449 177.984 126.469 178.296 ;
     RECT  126.241 186.96 126.469 186.984 ;
     RECT  125.411 219.024 126.493 219.048 ;
     RECT  125.845 150.432 126.529 150.456 ;
     RECT  126.529 150.432 126.608 150.552 ;
     RECT  125.953 153.552 126.608 153.576 ;
     RECT  125.413 156.912 126.608 156.936 ;
     RECT  124.661 159.6 126.608 159.624 ;
     RECT  125.708 160.704 126.608 161.88 ;
     RECT  125.749 162.864 126.608 163.128 ;
     RECT  126.457 173.424 126.608 173.448 ;
     RECT  126.469 174.96 126.608 178.296 ;
     RECT  126.385 179.664 126.608 180.696 ;
     RECT  126.061 182.304 126.608 182.424 ;
     RECT  125.809 184.8 126.608 184.872 ;
     RECT  126.469 186.192 126.608 186.984 ;
     RECT  126.457 188.352 126.608 188.376 ;
     RECT  125.953 189.744 126.608 192.696 ;
     RECT  126.241 194.208 126.608 195.336 ;
     RECT  124.949 202.608 126.608 203.208 ;
     RECT  126.421 204.816 126.608 204.84 ;
     RECT  124.345 207.456 126.608 207.48 ;
     RECT  126.385 208.8 126.608 210.984 ;
     RECT  125.881 212.016 126.608 213 ;
     RECT  125.459 214.512 126.608 214.92 ;
     RECT  126.493 219.024 126.608 219.096 ;
     RECT  126.608 2.148 126.712 369.372 ;
     RECT  126.712 2.418 126.904 369.102 ;
     RECT  126.904 177.216 126.965 181.272 ;
     RECT  126.904 201.12 127.081 203.208 ;
     RECT  126.904 150.432 127.109 150.552 ;
     RECT  126.904 172.656 127.139 174.216 ;
     RECT  126.904 190.416 127.139 191.784 ;
     RECT  126.904 214.224 127.139 220.152 ;
     RECT  126.904 158.304 127.145 160.2 ;
     RECT  126.904 162.912 127.145 162.936 ;
     RECT  127.139 219.6 127.181 219.624 ;
     RECT  126.904 221.76 127.181 221.784 ;
     RECT  126.904 154.656 127.217 155.64 ;
     RECT  126.904 208.032 127.228 208.824 ;
     RECT  127.217 154.656 127.235 154.68 ;
     RECT  126.904 175.872 127.235 176.136 ;
     RECT  126.965 177.456 127.253 181.272 ;
     RECT  126.904 153.552 127.397 153.576 ;
     RECT  127.139 190.56 127.433 191.784 ;
     RECT  127.145 158.304 127.475 159.048 ;
     RECT  127.139 214.224 127.475 218.328 ;
     RECT  127.145 160.176 127.541 160.2 ;
     RECT  126.904 161.28 127.613 161.832 ;
     RECT  126.904 210.144 127.649 210.168 ;
     RECT  126.904 170.256 127.667 170.28 ;
     RECT  127.139 174.144 127.667 174.216 ;
     RECT  127.253 177.456 127.667 177.768 ;
     RECT  126.904 222.816 127.715 222.84 ;
     RECT  127.253 178.944 127.721 181.272 ;
     RECT  127.433 191.76 127.721 191.784 ;
     RECT  126.904 186.192 127.757 186.216 ;
     RECT  126.904 168.576 127.763 169.176 ;
     RECT  127.228 208.8 127.829 208.824 ;
     RECT  126.904 211.488 127.829 211.752 ;
     RECT  126.904 224.016 127.865 224.04 ;
     RECT  126.904 188.016 127.933 188.616 ;
     RECT  127.667 177.744 127.937 177.768 ;
     RECT  126.904 184.608 127.937 184.872 ;
     RECT  126.904 194.208 128.003 195.624 ;
     RECT  127.109 150.432 128.005 150.456 ;
     RECT  127.829 211.728 128.009 211.752 ;
     RECT  126.904 196.848 128.012 196.968 ;
     RECT  128.005 149.904 128.045 150.456 ;
     RECT  128.012 196.032 128.099 196.968 ;
     RECT  126.904 167.568 128.108 167.592 ;
     RECT  127.937 184.608 128.108 184.728 ;
     RECT  126.904 198.336 128.113 200.04 ;
     RECT  128.003 194.208 128.117 194.952 ;
     RECT  127.081 201.216 128.149 203.208 ;
     RECT  126.904 204.624 128.156 204.648 ;
     RECT  128.005 205.872 128.156 205.896 ;
     RECT  128.099 196.944 128.189 196.968 ;
     RECT  126.904 165.456 128.195 165.48 ;
     RECT  128.108 166.656 128.195 167.592 ;
     RECT  127.721 178.944 128.195 181.176 ;
     RECT  128.108 184.176 128.195 184.728 ;
     RECT  128.045 149.904 128.221 149.928 ;
     RECT  128.113 198.288 128.225 200.04 ;
     RECT  128.156 204.624 128.243 205.896 ;
     RECT  126.904 156.864 128.245 156.888 ;
     RECT  128.149 213.168 128.261 213.192 ;
     RECT  128.245 156.144 128.291 157.464 ;
     RECT  128.225 198.336 128.293 200.04 ;
     RECT  128.149 201.024 128.293 203.208 ;
     RECT  127.475 217.728 128.321 218.328 ;
     RECT  128.195 178.944 128.333 180.984 ;
     RECT  128.291 156.144 128.365 156.168 ;
     RECT  128.257 220.704 128.365 220.728 ;
     RECT  126.904 152.448 128.389 152.472 ;
     RECT  128.321 217.728 128.405 218.424 ;
     RECT  127.475 216.576 128.473 216.6 ;
     RECT  128.389 151.488 128.476 152.472 ;
     RECT  128.365 155.376 128.477 156.168 ;
     RECT  128.243 204.624 128.477 205.416 ;
     RECT  128.365 220.608 128.509 220.728 ;
     RECT  128.221 149.232 128.513 149.928 ;
     RECT  127.763 168.576 128.581 168.648 ;
     RECT  128.509 182.976 128.581 183 ;
     RECT  127.933 187.68 128.581 188.616 ;
     RECT  128.509 227.616 128.581 227.64 ;
     RECT  128.113 225.024 128.627 225.048 ;
     RECT  128.54 226.32 128.627 226.344 ;
     RECT  128.581 227.616 128.627 228.552 ;
     RECT  128.005 210.24 128.653 210.264 ;
     RECT  128.653 206.736 128.689 206.76 ;
     RECT  128.405 217.728 128.693 217.752 ;
     RECT  128.509 220.608 128.725 221.64 ;
     RECT  127.235 175.872 128.761 175.896 ;
     RECT  128.725 220.032 128.821 221.64 ;
     RECT  128.581 187.68 128.833 188.664 ;
     RECT  128.689 189.696 128.833 189.72 ;
     RECT  127.139 172.656 128.869 172.68 ;
     RECT  128.293 198.336 128.869 203.208 ;
     RECT  128.333 179.616 128.873 180.984 ;
     RECT  128.473 216.48 128.873 216.6 ;
     RECT  128.725 223.776 128.905 223.8 ;
     RECT  128.833 187.68 128.909 189.72 ;
     RECT  128.821 220.032 128.909 222.312 ;
     RECT  126.904 171.408 128.915 171.432 ;
     RECT  128.117 194.928 128.915 194.952 ;
     RECT  128.909 220.032 128.915 221.64 ;
     RECT  128.185 154.272 128.941 154.296 ;
     RECT  128.761 175.536 128.945 175.896 ;
     RECT  128.513 149.232 128.972 149.256 ;
     RECT  128.476 152.448 129.013 152.472 ;
     RECT  128.941 154.176 129.013 154.296 ;
     RECT  128.869 172.656 129.017 172.872 ;
     RECT  128.869 198.336 129.049 203.64 ;
     RECT  128.689 206.736 129.085 206.856 ;
     RECT  128.828 160.656 129.107 160.68 ;
     RECT  128.653 210.24 129.157 210.456 ;
     RECT  128.108 212.016 129.157 212.04 ;
     RECT  128.915 221.232 129.161 221.64 ;
     RECT  129.157 210.24 129.244 212.04 ;
     RECT  128.905 223.776 129.265 224.04 ;
     RECT  129.049 198.336 129.269 204.216 ;
     RECT  129.244 210.24 129.277 210.936 ;
     RECT  129.193 237.744 129.301 237.768 ;
     RECT  128.972 148.992 129.337 149.256 ;
     RECT  128.291 157.44 129.337 157.464 ;
     RECT  128.873 216.576 129.341 216.6 ;
     RECT  129.308 176.688 129.349 176.712 ;
     RECT  128.909 187.68 129.373 189.624 ;
     RECT  129.085 206.736 129.373 207.336 ;
     RECT  129.277 210.24 129.373 210.408 ;
     RECT  129.337 148.8 129.377 149.256 ;
     RECT  129.349 176.688 129.395 176.808 ;
     RECT  128.725 177.84 129.395 177.864 ;
     RECT  129.337 157.296 129.397 157.464 ;
     RECT  129.365 158.496 129.397 158.52 ;
     RECT  129.373 234.24 129.397 234.264 ;
     RECT  129.356 236.304 129.407 236.328 ;
     RECT  129.301 237.744 129.407 238.296 ;
     RECT  129.407 236.304 129.443 238.296 ;
     RECT  129.397 234.24 129.445 235.128 ;
     RECT  129.397 157.296 129.449 158.52 ;
     RECT  129.445 234.24 129.485 235.704 ;
     RECT  129.443 237.12 129.491 237.768 ;
     RECT  128.477 155.376 129.548 156.12 ;
     RECT  129.409 192.768 129.553 192.792 ;
     RECT  129.013 152.448 129.589 154.296 ;
     RECT  129.548 155.28 129.589 156.12 ;
     RECT  129.301 232.944 129.589 232.968 ;
     RECT  128.581 182.16 129.593 183 ;
     RECT  129.485 235.104 129.657 235.704 ;
     RECT  129.625 196.992 129.661 197.016 ;
     RECT  129.373 209.424 129.665 210.408 ;
     RECT  129.553 192.672 129.74 192.792 ;
     RECT  129.661 196.656 129.761 197.016 ;
     RECT  128.869 186.384 129.769 186.408 ;
     RECT  129.74 192.624 129.769 192.792 ;
     RECT  128.195 184.704 129.773 184.728 ;
     RECT  129.769 186.336 129.781 186.408 ;
     RECT  129.769 192.624 129.805 192.984 ;
     RECT  129.373 206.736 129.809 207.624 ;
     RECT  129.445 151.2 129.836 151.224 ;
     RECT  129.589 152.448 129.836 156.12 ;
     RECT  129.781 186.336 129.836 186.504 ;
     RECT  129.761 196.656 129.841 197.256 ;
     RECT  129.269 198.336 129.841 199.464 ;
     RECT  129.836 151.2 129.877 156.12 ;
     RECT  129.836 185.952 129.877 186.504 ;
     RECT  129.373 187.488 129.877 189.624 ;
     RECT  128.915 220.032 129.877 220.056 ;
     RECT  128.873 179.664 129.913 180.984 ;
     RECT  129.805 192.336 129.913 192.984 ;
     RECT  129.517 194.064 129.913 194.088 ;
     RECT  129.733 195.552 129.913 195.576 ;
     RECT  129.841 196.656 129.913 199.464 ;
     RECT  129.265 223.776 129.913 224.856 ;
     RECT  129.877 220.032 129.917 220.2 ;
     RECT  129.877 151.008 129.923 156.12 ;
     RECT  129.913 192.336 129.949 194.088 ;
     RECT  129.913 195.552 129.949 199.464 ;
     RECT  129.449 157.296 129.971 158.04 ;
     RECT  127.613 161.808 129.973 161.832 ;
     RECT  129.269 200.64 129.98 204.216 ;
     RECT  129.923 152.64 129.985 156.12 ;
     RECT  129.665 210.384 129.989 210.408 ;
     RECT  129.973 161.76 130.021 161.832 ;
     RECT  128.477 205.392 130.021 205.416 ;
     RECT  129.949 192.336 130.061 199.464 ;
     RECT  129.98 200.64 130.061 204.36 ;
     RECT  130.021 205.392 130.067 205.848 ;
     RECT  129.877 185.952 130.076 189.624 ;
     RECT  130.061 192.336 130.093 194.904 ;
     RECT  129.949 218.832 130.133 219.048 ;
     RECT  129.017 172.848 130.157 172.872 ;
     RECT  127.667 174.192 130.157 174.216 ;
     RECT  130.157 172.848 130.165 174.216 ;
     RECT  127.475 214.224 130.165 215.064 ;
     RECT  129.913 222.816 130.165 224.856 ;
     RECT  130.076 185.952 130.172 189.672 ;
     RECT  129.985 152.64 130.201 156.312 ;
     RECT  129.625 216.672 130.201 217.224 ;
     RECT  128.945 175.536 130.205 175.56 ;
     RECT  130.165 213.648 130.211 215.064 ;
     RECT  130.061 196.08 130.237 199.464 ;
     RECT  130.165 172.848 130.241 174.456 ;
     RECT  129.913 179.664 130.261 181.128 ;
     RECT  130.165 222.288 130.273 224.856 ;
     RECT  130.211 214.896 130.309 215.064 ;
     RECT  130.067 205.776 130.349 205.848 ;
     RECT  130.172 185.856 130.355 189.672 ;
     RECT  129.917 220.128 130.381 220.2 ;
     RECT  129.657 235.248 130.385 235.704 ;
     RECT  129.593 182.976 130.417 183 ;
     RECT  129.923 151.008 130.421 151.032 ;
     RECT  128.831 170.304 130.453 170.328 ;
     RECT  129.157 171.312 130.453 171.336 ;
     RECT  130.309 214.896 130.453 215.496 ;
     RECT  130.201 216.672 130.453 217.752 ;
     RECT  130.453 170.304 130.489 171.336 ;
     RECT  130.241 173.712 130.489 174.456 ;
     RECT  130.093 191.808 130.489 194.904 ;
     RECT  128.627 228.528 130.489 228.552 ;
     RECT  130.381 220.128 130.508 221.16 ;
     RECT  130.355 187.68 130.525 189.672 ;
     RECT  129.589 232.032 130.525 232.968 ;
     RECT  130.201 152.64 130.529 157.032 ;
     RECT  130.489 173.712 130.529 174.84 ;
     RECT  130.273 222.288 130.547 225.336 ;
     RECT  130.061 204.192 130.565 204.36 ;
     RECT  130.453 214.896 130.565 217.752 ;
     RECT  130.508 220.128 130.595 221.304 ;
     RECT  129.445 160.704 130.597 160.728 ;
     RECT  130.021 161.76 130.597 162.504 ;
     RECT  130.525 187.68 130.597 190.008 ;
     RECT  129.395 176.784 130.601 176.808 ;
     RECT  130.565 215.904 130.601 217.752 ;
     RECT  130.547 222.288 130.601 225.144 ;
     RECT  130.595 220.128 130.629 220.2 ;
     RECT  130.529 155.376 130.637 157.032 ;
     RECT  130.489 191.76 130.637 194.904 ;
     RECT  129.809 206.832 130.669 207.624 ;
     RECT  130.489 228 130.673 228.552 ;
     RECT  129.377 148.8 130.709 148.824 ;
     RECT  130.261 178.8 130.745 181.128 ;
     RECT  129.491 237.12 130.745 237.144 ;
     RECT  129.061 164.4 130.777 164.424 ;
     RECT  128.581 168.096 130.777 168.648 ;
     RECT  130.601 216.96 130.796 217.752 ;
     RECT  129.517 166.08 130.813 166.104 ;
     RECT  130.349 205.824 130.813 205.848 ;
     RECT  130.669 206.832 130.813 207.72 ;
     RECT  130.355 185.856 130.837 186.552 ;
     RECT  130.669 147.696 130.883 147.72 ;
     RECT  130.796 216.96 130.883 217.944 ;
     RECT  130.489 170.304 130.885 171.96 ;
     RECT  130.637 191.76 130.885 192.984 ;
     RECT  130.885 170.16 131.029 171.96 ;
     RECT  130.237 196.08 131.029 199.512 ;
     RECT  130.417 182.976 131.125 183.72 ;
     RECT  130.837 184.704 131.125 186.552 ;
     RECT  129.733 229.824 131.125 230.088 ;
     RECT  130.799 145.92 131.132 145.944 ;
     RECT  130.597 160.704 131.137 162.504 ;
     RECT  130.777 164.112 131.137 164.424 ;
     RECT  131.029 196.032 131.137 199.512 ;
     RECT  130.061 200.64 131.137 202.968 ;
     RECT  130.529 174.048 131.281 174.84 ;
     RECT  130.385 235.248 131.317 235.272 ;
     RECT  130.777 167.808 131.353 168.648 ;
     RECT  130.637 194.256 131.353 194.904 ;
     RECT  131.137 196.032 131.353 202.968 ;
     RECT  131.353 167.568 131.389 168.648 ;
     RECT  131.029 169.968 131.389 171.96 ;
     RECT  130.813 237.408 131.425 237.432 ;
     RECT  131.281 174.048 131.461 175.416 ;
     RECT  130.133 219.024 131.461 219.048 ;
     RECT  130.601 222.288 131.533 223.224 ;
     RECT  131.425 237.408 131.569 237.672 ;
     RECT  130.705 239.04 131.569 239.064 ;
     RECT  130.525 232.032 131.605 233.4 ;
     RECT  129.971 158.016 131.641 158.04 ;
     RECT  131.533 221.52 131.641 223.224 ;
     RECT  131.245 227.712 131.641 227.736 ;
     RECT  131.605 231.888 131.653 233.4 ;
     RECT  131.317 234.576 131.653 235.272 ;
     RECT  130.597 187.68 131.677 190.152 ;
     RECT  130.885 191.616 131.677 192.984 ;
     RECT  131.125 182.976 131.701 186.552 ;
     RECT  131.701 182.352 131.708 186.552 ;
     RECT  131.389 167.376 131.749 171.96 ;
     RECT  131.708 182.352 131.785 186.648 ;
     RECT  131.677 187.68 131.785 192.984 ;
     RECT  131.785 182.352 131.797 192.984 ;
     RECT  130.211 213.648 131.797 213.672 ;
     RECT  130.565 214.896 131.797 214.92 ;
     RECT  131.281 151.584 131.845 151.608 ;
     RECT  130.529 152.64 131.845 154.296 ;
     RECT  130.637 155.376 131.845 156.072 ;
     RECT  130.565 204.288 131.845 204.36 ;
     RECT  131.845 150.864 131.857 156.168 ;
     RECT  131.173 143.904 131.893 143.928 ;
     RECT  131.641 157.968 131.893 158.04 ;
     RECT  131.749 167.376 131.893 172.104 ;
     RECT  130.745 180.432 131.893 181.128 ;
     RECT  131.797 182.112 131.893 192.984 ;
     RECT  131.641 221.472 131.893 223.224 ;
     RECT  130.601 224.544 131.893 225.144 ;
     RECT  131.893 180.432 131.929 192.984 ;
     RECT  130.813 205.824 132.001 207.72 ;
     RECT  131.893 142.464 132.008 143.928 ;
     RECT  131.132 145.344 132.008 145.944 ;
     RECT  131.857 150.48 132.008 156.168 ;
     RECT  131.893 157.824 132.008 158.04 ;
     RECT  131.749 159.024 132.008 159.048 ;
     RECT  131.137 160.704 132.008 164.424 ;
     RECT  130.813 165.408 132.008 166.104 ;
     RECT  131.893 167.376 132.008 172.92 ;
     RECT  131.461 174.048 132.008 176.376 ;
     RECT  130.745 178.8 132.008 178.824 ;
     RECT  131.929 180.432 132.008 193.224 ;
     RECT  131.353 194.256 132.008 202.968 ;
     RECT  131.845 204.192 132.008 204.36 ;
     RECT  132.001 205.536 132.008 207.72 ;
     RECT  131.929 209.712 132.008 209.736 ;
     RECT  131.965 210.96 132.008 210.984 ;
     RECT  129.244 212.016 132.008 212.04 ;
     RECT  131.797 213.648 132.008 214.92 ;
     RECT  130.601 215.904 132.008 215.928 ;
     RECT  130.883 216.96 132.008 216.984 ;
     RECT  131.461 218.256 132.008 219.048 ;
     RECT  130.629 220.128 132.008 220.152 ;
     RECT  131.893 221.472 132.008 225.144 ;
     RECT  131.641 227.712 132.008 228.264 ;
     RECT  131.125 229.824 132.008 230.904 ;
     RECT  131.653 231.888 132.008 235.272 ;
     RECT  131.893 236.4 132.008 236.424 ;
     RECT  131.569 237.408 132.008 239.064 ;
     RECT  132.008 2.148 132.112 369.372 ;
     RECT  132.133 371.376 132.229 371.4 ;
     RECT  132.112 2.418 132.304 369.102 ;
     RECT  132.304 158.064 132.365 158.088 ;
     RECT  132.304 227.712 132.401 231.48 ;
     RECT  132.304 236.688 132.419 238.056 ;
     RECT  132.304 168.192 132.445 174.84 ;
     RECT  132.304 195.6 132.465 200.76 ;
     RECT  132.229 371.088 132.467 371.4 ;
     RECT  132.304 148.176 132.509 148.2 ;
     RECT  132.304 234.816 132.509 235.08 ;
     RECT  132.304 164.256 132.515 165.912 ;
     RECT  132.401 227.76 132.515 231.48 ;
     RECT  132.465 195.6 132.545 199.128 ;
     RECT  132.304 242.64 132.563 242.664 ;
     RECT  132.467 371.232 132.563 371.4 ;
     RECT  132.304 149.376 132.581 150.504 ;
     RECT  132.304 232.56 132.617 233.112 ;
     RECT  132.304 185.616 132.653 189.624 ;
     RECT  132.304 221.472 132.689 226.488 ;
     RECT  132.304 219.888 132.707 220.152 ;
     RECT  132.689 223.776 132.707 226.488 ;
     RECT  132.515 228.576 132.707 231.48 ;
     RECT  132.304 142.464 132.725 142.488 ;
     RECT  132.304 176.16 132.725 177.336 ;
     RECT  132.545 195.6 132.725 198.936 ;
     RECT  132.707 228.576 132.725 229.704 ;
     RECT  132.689 221.472 132.748 222.504 ;
     RECT  132.304 209.184 132.769 212.424 ;
     RECT  132.304 204.192 132.797 207.72 ;
     RECT  132.581 149.856 132.833 150.504 ;
     RECT  132.725 197.28 132.864 198.936 ;
     RECT  132.707 223.776 132.892 223.8 ;
     RECT  132.304 216.384 132.947 217.464 ;
     RECT  132.707 219.888 132.947 220.104 ;
     RECT  132.304 159.696 132.977 159.72 ;
     RECT  132.445 171.264 133.049 174.84 ;
     RECT  132.748 221.472 133.049 222.072 ;
     RECT  132.509 234.816 133.049 234.84 ;
     RECT  132.445 168.192 133.121 169.848 ;
     RECT  132.515 164.304 133.139 165.912 ;
     RECT  132.617 233.088 133.157 233.112 ;
     RECT  132.563 371.376 133.157 371.4 ;
     RECT  133.139 165.888 133.18 165.912 ;
     RECT  132.725 195.6 133.265 196.104 ;
     RECT  132.304 201.744 133.297 202.824 ;
     RECT  132.797 204.192 133.297 207.528 ;
     RECT  132.304 167.04 133.333 167.064 ;
     RECT  132.653 185.664 133.333 189.624 ;
     RECT  132.304 190.896 133.333 194.568 ;
     RECT  132.465 200.112 133.333 200.76 ;
     RECT  133.297 201.744 133.333 207.528 ;
     RECT  133.333 200.112 133.337 207.528 ;
     RECT  132.304 213.648 133.381 214.824 ;
     RECT  132.947 216.384 133.381 216.888 ;
     RECT  132.725 176.4 133.388 177.336 ;
     RECT  132.304 178.8 133.388 184.248 ;
     RECT  133.381 213.648 133.409 216.888 ;
     RECT  132.707 230.736 133.409 231.48 ;
     RECT  132.304 152.64 133.441 154.056 ;
     RECT  132.304 155.376 133.441 156.168 ;
     RECT  132.304 146.16 133.445 146.184 ;
     RECT  133.381 158.496 133.468 158.52 ;
     RECT  133.388 176.4 133.475 184.248 ;
     RECT  133.121 169.44 133.477 169.848 ;
     RECT  133.049 171.264 133.477 171.816 ;
     RECT  133.297 235.824 133.477 235.848 ;
     RECT  132.419 236.832 133.477 238.056 ;
     RECT  133.409 213.648 133.481 216.6 ;
     RECT  133.484 147.264 133.525 147.288 ;
     RECT  133.265 195.6 133.549 195.96 ;
     RECT  132.833 149.952 133.553 150.504 ;
     RECT  133.525 147.264 133.571 148.248 ;
     RECT  133.532 139.392 133.573 139.416 ;
     RECT  133.513 141.648 133.573 141.672 ;
     RECT  133.477 169.44 133.589 171.816 ;
     RECT  132.707 224.832 133.589 226.488 ;
     RECT  133.573 139.392 133.619 141.672 ;
     RECT  132.769 209.712 133.621 212.424 ;
     RECT  133.619 140.016 133.661 140.76 ;
     RECT  132.304 161.904 133.715 163.032 ;
     RECT  133.475 176.4 133.729 176.616 ;
     RECT  133.621 209.712 133.769 212.616 ;
     RECT  133.693 143.76 133.805 143.784 ;
     RECT  133.769 212.4 133.805 212.616 ;
     RECT  132.947 219.888 133.805 219.912 ;
     RECT  133.333 167.04 133.813 167.208 ;
     RECT  133.121 168.192 133.813 168.216 ;
     RECT  133.337 200.112 133.813 206.376 ;
     RECT  132.725 229.296 133.813 229.704 ;
     RECT  133.409 230.736 133.813 230.952 ;
     RECT  132.864 197.28 133.837 198.648 ;
     RECT  133.813 199.632 133.837 206.376 ;
     RECT  133.813 166.704 133.859 168.216 ;
     RECT  133.859 166.704 133.9 167.592 ;
     RECT  133.813 229.296 133.9 230.952 ;
     RECT  133.475 178.08 133.909 184.248 ;
     RECT  133.549 218.208 133.909 218.232 ;
     RECT  133.729 223.392 133.909 223.416 ;
     RECT  133.589 226.416 133.909 226.488 ;
     RECT  133.573 138.144 133.913 138.168 ;
     RECT  132.304 160.704 133.945 160.728 ;
     RECT  133.715 161.904 133.945 162.408 ;
     RECT  133.805 212.592 133.949 212.616 ;
     RECT  133.477 235.824 133.955 238.056 ;
     RECT  133.481 216.576 133.957 216.6 ;
     RECT  133.909 223.392 133.985 223.512 ;
     RECT  133.9 230.736 134.003 230.952 ;
     RECT  133.333 185.664 134.017 194.568 ;
     RECT  133.769 209.712 134.017 211.032 ;
     RECT  134.017 185.616 134.021 194.568 ;
     RECT  133.139 164.304 134.053 164.856 ;
     RECT  133.525 145.68 134.125 145.704 ;
     RECT  134.053 163.44 134.125 164.856 ;
     RECT  133.957 231.984 134.161 232.008 ;
     RECT  133.873 234.72 134.161 234.744 ;
     RECT  133.9 167.184 134.201 167.592 ;
     RECT  133.955 235.824 134.201 235.848 ;
     RECT  133.955 236.832 134.201 238.056 ;
     RECT  134.021 194.544 134.233 194.568 ;
     RECT  133.549 195.552 134.233 195.96 ;
     RECT  133.985 223.488 134.237 223.512 ;
     RECT  133.589 224.832 134.237 224.856 ;
     RECT  132.304 239.04 134.237 239.064 ;
     RECT  133.049 172.992 134.269 174.84 ;
     RECT  134.003 230.736 134.273 230.76 ;
     RECT  133.837 197.28 134.305 206.376 ;
     RECT  134.201 236.832 134.309 237.768 ;
     RECT  133.585 159.6 134.377 159.624 ;
     RECT  133.589 171.264 134.377 171.816 ;
     RECT  134.269 172.992 134.377 175.032 ;
     RECT  133.337 207.408 134.377 207.528 ;
     RECT  133.481 213.648 134.377 215.112 ;
     RECT  134.161 234.72 134.377 234.84 ;
     RECT  134.305 196.944 134.389 206.376 ;
     RECT  134.377 207.408 134.389 207.624 ;
     RECT  133.571 148.224 134.413 148.248 ;
     RECT  133.589 169.44 134.437 169.8 ;
     RECT  134.125 145.632 134.449 145.704 ;
     RECT  134.125 163.44 134.449 165.096 ;
     RECT  134.341 166.128 134.449 166.152 ;
     RECT  134.377 212.784 134.449 215.112 ;
     RECT  134.021 185.616 134.485 193.272 ;
     RECT  133.9 229.296 134.485 229.704 ;
     RECT  133.661 140.016 134.486 140.088 ;
     RECT  133.909 217.584 134.521 218.232 ;
     RECT  134.377 234.72 134.531 234.888 ;
     RECT  133.909 226.416 134.557 227.448 ;
     RECT  133.553 149.952 134.561 150.024 ;
     RECT  134.449 163.44 134.561 166.152 ;
     RECT  134.377 159.024 134.579 159.624 ;
     RECT  134.413 148.224 134.581 148.632 ;
     RECT  134.561 149.952 134.581 149.976 ;
     RECT  134.579 159.024 134.593 159.432 ;
     RECT  134.561 163.488 134.597 166.152 ;
     RECT  134.233 194.544 134.629 195.96 ;
     RECT  134.389 196.944 134.629 207.624 ;
     RECT  134.521 217.584 134.665 218.328 ;
     RECT  133.049 221.472 134.665 221.736 ;
     RECT  134.531 234.72 134.665 234.84 ;
     RECT  134.581 148.224 134.668 149.976 ;
     RECT  134.597 163.488 134.669 165.096 ;
     RECT  134.557 226.32 134.675 227.448 ;
     RECT  134.665 220.56 134.701 221.736 ;
     RECT  134.269 219.408 134.705 219.432 ;
     RECT  134.485 229.008 134.705 229.704 ;
     RECT  134.017 208.8 134.737 211.032 ;
     RECT  134.669 163.488 134.741 164.808 ;
     RECT  134.665 217.584 134.749 218.424 ;
     RECT  134.309 236.832 134.777 237.672 ;
     RECT  134.161 231.984 134.78 232.44 ;
     RECT  133.909 178.08 134.809 184.296 ;
     RECT  134.485 185.52 134.809 193.272 ;
     RECT  134.78 231.984 134.821 232.968 ;
     RECT  134.593 158.448 134.845 159.432 ;
     RECT  134.821 231.936 134.867 232.968 ;
     RECT  134.737 208.8 134.917 211.224 ;
     RECT  134.437 168.72 134.945 169.8 ;
     RECT  134.377 171.264 134.945 175.032 ;
     RECT  134.701 220.56 134.953 222.12 ;
     RECT  134.581 151.2 134.957 151.224 ;
     RECT  134.867 231.936 134.957 232.44 ;
     RECT  134.629 194.544 134.989 207.624 ;
     RECT  133.729 176.352 135.02 176.616 ;
     RECT  134.945 168.72 135.025 175.032 ;
     RECT  135.02 176.352 135.025 176.664 ;
     RECT  135.025 168.72 135.029 176.664 ;
     RECT  134.809 178.08 135.029 193.272 ;
     RECT  134.989 194.448 135.097 207.624 ;
     RECT  134.917 208.704 135.097 211.224 ;
     RECT  134.749 217.584 135.097 218.328 ;
     RECT  134.845 157.92 135.101 159.432 ;
     RECT  135.029 171.264 135.133 176.664 ;
     RECT  135.029 178.08 135.133 193.224 ;
     RECT  134.449 145.632 135.169 146.424 ;
     RECT  134.809 239.136 135.169 239.976 ;
     RECT  134.705 229.104 135.173 229.704 ;
     RECT  135.169 145.008 135.209 146.424 ;
     RECT  134.597 166.128 135.277 166.152 ;
     RECT  134.201 167.184 135.277 167.208 ;
     RECT  135.029 168.72 135.277 170.04 ;
     RECT  133.441 152.64 135.281 156.168 ;
     RECT  135.101 157.92 135.281 158.664 ;
     RECT  135.097 194.448 135.313 211.224 ;
     RECT  135.169 239.136 135.349 240.552 ;
     RECT  135.133 171.264 135.353 193.224 ;
     RECT  132.304 275.616 135.353 275.64 ;
     RECT  134.741 163.776 135.395 164.808 ;
     RECT  135.349 237.888 135.395 240.552 ;
     RECT  134.449 212.784 135.421 215.448 ;
     RECT  134.675 226.32 135.497 226.728 ;
     RECT  134.957 231.936 135.529 231.96 ;
     RECT  134.668 149.952 135.565 149.976 ;
     RECT  134.777 236.832 135.565 236.856 ;
     RECT  135.313 194.304 135.637 211.224 ;
     RECT  135.565 236.544 135.637 236.856 ;
     RECT  135.353 177.936 135.677 193.224 ;
     RECT  135.565 149.952 135.685 151.032 ;
     RECT  134.668 148.224 135.709 148.632 ;
     RECT  135.281 152.64 135.713 156.072 ;
     RECT  135.677 177.936 135.713 193.032 ;
     RECT  134.665 234.24 135.733 234.84 ;
     RECT  135.497 226.32 135.745 226.584 ;
     RECT  135.097 217.248 135.785 218.328 ;
     RECT  135.253 224.832 135.857 224.856 ;
     RECT  134.486 140.064 135.889 140.088 ;
     RECT  135.713 177.936 135.893 192.888 ;
     RECT  135.637 236.352 135.893 236.856 ;
     RECT  135.893 177.936 135.916 189.816 ;
     RECT  135.889 140.064 135.929 140.232 ;
     RECT  133.945 160.704 135.929 162.408 ;
     RECT  135.929 161.424 135.961 162.408 ;
     RECT  135.395 163.776 135.961 164.328 ;
     RECT  135.893 190.8 135.965 192.888 ;
     RECT  135.785 217.728 135.965 218.328 ;
     RECT  135.709 147.648 136.001 148.632 ;
     RECT  135.685 149.76 136.001 151.032 ;
     RECT  135.916 178.272 136.001 189.816 ;
     RECT  135.745 226.224 136.037 226.584 ;
     RECT  135.395 237.888 136.037 239.16 ;
     RECT  135.637 194.208 136.069 211.224 ;
     RECT  135.421 212.352 136.069 215.448 ;
     RECT  134.953 220.56 136.069 222.264 ;
     RECT  136.028 223.296 136.069 223.32 ;
     RECT  136.069 220.56 136.115 223.32 ;
     RECT  135.997 224.4 136.115 224.52 ;
     RECT  136.037 237.888 136.115 238.728 ;
     RECT  136.001 147.648 136.165 148.104 ;
     RECT  136.115 220.56 136.165 222.36 ;
     RECT  135.529 231.12 136.181 231.96 ;
     RECT  136.165 146.784 136.211 148.104 ;
     RECT  135.733 234.24 136.217 235.224 ;
     RECT  135.997 137.52 136.22 137.544 ;
     RECT  136.165 220.368 136.249 222.36 ;
     RECT  135.893 236.448 136.253 236.856 ;
     RECT  136.22 137.52 136.307 138.504 ;
     RECT  135.353 171.264 136.307 176.664 ;
     RECT  136.249 275.328 136.333 275.352 ;
     RECT  135.713 154.8 136.429 156.072 ;
     RECT  134.557 142.704 136.501 142.728 ;
     RECT  135.277 166.128 136.501 170.04 ;
     RECT  136.307 171.264 136.501 171.912 ;
     RECT  135.965 217.824 136.537 218.328 ;
     RECT  135.817 228 136.537 228.024 ;
     RECT  135.173 229.104 136.537 229.128 ;
     RECT  136.037 226.464 136.609 226.584 ;
     RECT  135.281 157.92 136.645 157.944 ;
     RECT  136.217 234.24 136.645 234.264 ;
     RECT  136.429 154.8 136.681 156.12 ;
     RECT  135.713 152.64 136.717 153.528 ;
     RECT  136.681 154.8 136.717 156.168 ;
     RECT  135.965 190.896 136.717 192.888 ;
     RECT  136.069 194.208 136.717 215.448 ;
     RECT  136.001 149.76 136.969 150.312 ;
     RECT  136.717 190.896 137.005 215.448 ;
     RECT  136.307 173.136 137.041 176.664 ;
     RECT  135.395 240.528 137.113 240.552 ;
     RECT  136.537 217.824 137.185 218.856 ;
     RECT  135.929 140.208 137.257 140.232 ;
     RECT  135.209 145.008 137.257 145.32 ;
     RECT  136.969 149.76 137.257 150.504 ;
     RECT  135.961 161.424 137.257 164.328 ;
     RECT  136.645 157.92 137.401 158.424 ;
     RECT  136.253 236.544 137.401 236.856 ;
     RECT  136.115 238.704 137.401 238.728 ;
     RECT  135.997 135.648 137.408 135.672 ;
     RECT  136.307 137.52 137.408 137.592 ;
     RECT  137.257 140.208 137.408 140.76 ;
     RECT  136.501 142.704 137.408 143.544 ;
     RECT  137.257 145.008 137.408 145.656 ;
     RECT  136.211 146.784 137.408 147.096 ;
     RECT  136.211 148.08 137.408 148.104 ;
     RECT  137.257 149.76 137.408 150.552 ;
     RECT  136.717 152.64 137.408 156.168 ;
     RECT  137.401 157.296 137.408 158.424 ;
     RECT  137.257 161.088 137.408 164.328 ;
     RECT  136.501 166.128 137.408 171.912 ;
     RECT  137.041 173.136 137.408 177 ;
     RECT  136.001 178.272 137.408 189.72 ;
     RECT  137.005 190.752 137.408 215.448 ;
     RECT  137.185 217.824 137.408 218.904 ;
     RECT  136.249 219.984 137.408 222.36 ;
     RECT  136.115 224.496 137.408 224.52 ;
     RECT  136.609 226.464 137.408 226.68 ;
     RECT  136.537 228 137.408 229.128 ;
     RECT  136.717 230.208 137.408 230.232 ;
     RECT  136.181 231.936 137.408 231.96 ;
     RECT  136.645 233.712 137.408 234.264 ;
     RECT  137.401 236.544 137.408 238.728 ;
     RECT  137.113 240.144 137.408 240.552 ;
     RECT  137.408 2.148 137.512 369.372 ;
     RECT  137.512 2.418 137.704 369.102 ;
     RECT  137.704 224.496 137.843 226.68 ;
     RECT  137.704 235.776 137.843 236.664 ;
     RECT  137.704 237.744 137.843 238.248 ;
     RECT  137.704 239.232 137.843 240.168 ;
     RECT  137.704 241.2 137.843 241.224 ;
     RECT  137.704 157.296 137.909 215.064 ;
     RECT  137.704 229.104 137.909 229.128 ;
     RECT  137.909 164.304 137.945 215.064 ;
     RECT  137.704 137.52 137.981 137.544 ;
     RECT  137.704 140.736 138.017 140.76 ;
     RECT  137.945 190.56 138.053 215.064 ;
     RECT  137.704 135.648 138.089 136.296 ;
     RECT  137.945 164.304 138.161 166.152 ;
     RECT  137.704 152.16 138.269 153.384 ;
     RECT  137.909 157.296 138.269 163.032 ;
     RECT  138.053 204.048 138.269 215.064 ;
     RECT  137.704 138.768 138.275 139.464 ;
     RECT  137.704 217.632 138.341 221.064 ;
     RECT  137.843 224.496 138.413 225.24 ;
     RECT  138.269 157.344 138.419 163.032 ;
     RECT  138.053 190.56 138.449 202.968 ;
     RECT  138.419 160.992 138.521 162.6 ;
     RECT  137.704 149.76 138.665 151.128 ;
     RECT  137.704 223.392 138.665 223.416 ;
     RECT  138.269 212.832 138.697 215.064 ;
     RECT  137.843 226.656 138.697 226.68 ;
     RECT  137.704 227.952 138.697 228.072 ;
     RECT  137.704 233.904 138.697 233.928 ;
     RECT  138.665 150.912 138.701 151.128 ;
     RECT  138.419 157.344 138.701 159.72 ;
     RECT  137.704 141.936 138.757 141.96 ;
     RECT  137.704 145.632 138.773 147.096 ;
     RECT  138.521 160.992 138.773 162.456 ;
     RECT  138.341 219.6 138.773 221.064 ;
     RECT  138.697 226.656 138.805 228.072 ;
     RECT  138.701 159.696 138.809 159.72 ;
     RECT  138.757 141.936 138.844 142.488 ;
     RECT  138.269 152.64 138.845 153.384 ;
     RECT  138.697 233.904 138.877 234.12 ;
     RECT  138.805 226.32 138.881 228.072 ;
     RECT  138.881 226.32 138.889 226.44 ;
     RECT  138.341 217.632 138.913 218.28 ;
     RECT  137.843 239.232 139.025 239.256 ;
     RECT  138.449 198 139.057 202.968 ;
     RECT  137.704 230.496 139.057 230.52 ;
     RECT  137.704 222.048 139.133 222.12 ;
     RECT  137.704 154.464 139.139 156.168 ;
     RECT  138.773 220.464 139.169 221.064 ;
     RECT  139.057 230.496 139.201 231.432 ;
     RECT  138.665 149.76 139.237 149.88 ;
     RECT  138.773 145.632 139.277 146.664 ;
     RECT  139.277 146.4 139.283 146.664 ;
     RECT  137.945 167.184 139.309 189.432 ;
     RECT  138.877 233.904 139.313 234.216 ;
     RECT  138.275 139.44 139.345 139.464 ;
     RECT  138.877 235.248 139.381 235.272 ;
     RECT  139.237 149.184 139.385 149.88 ;
     RECT  139.381 235.248 139.421 235.56 ;
     RECT  139.309 167.04 139.427 189.432 ;
     RECT  139.34 236.64 139.427 236.664 ;
     RECT  139.057 198 139.453 203.064 ;
     RECT  138.269 204.048 139.453 211.32 ;
     RECT  138.881 227.568 139.489 228.072 ;
     RECT  139.385 149.184 139.493 149.208 ;
     RECT  138.449 190.56 139.525 197.016 ;
     RECT  139.453 198 139.525 211.32 ;
     RECT  137.704 144.336 139.561 144.36 ;
     RECT  138.913 217.488 139.561 218.28 ;
     RECT  139.561 144.048 139.597 144.36 ;
     RECT  139.561 217.152 139.621 218.28 ;
     RECT  139.237 224.064 139.621 224.088 ;
     RECT  139.381 241.296 139.628 241.32 ;
     RECT  138.161 164.304 139.637 165.576 ;
     RECT  139.489 227.568 139.637 228.216 ;
     RECT  139.621 217.152 139.645 219.048 ;
     RECT  139.645 217.632 139.667 219.048 ;
     RECT  139.427 167.424 139.669 189.432 ;
     RECT  139.525 190.56 139.669 211.848 ;
     RECT  139.637 228.192 139.676 228.216 ;
     RECT  138.089 136.272 139.705 136.296 ;
     RECT  138.769 244.416 139.705 244.44 ;
     RECT  139.345 139.152 139.709 139.464 ;
     RECT  139.628 240.48 139.715 241.32 ;
     RECT  139.676 228.192 139.763 229.176 ;
     RECT  138.841 242.304 139.773 242.328 ;
     RECT  139.201 230.304 139.777 231.432 ;
     RECT  139.196 148.128 139.813 148.152 ;
     RECT  138.773 161.376 139.813 162.456 ;
     RECT  139.637 164.832 139.813 165.576 ;
     RECT  138.844 141.936 139.861 141.96 ;
     RECT  139.705 137.376 139.868 137.4 ;
     RECT  139.868 137.376 139.885 137.496 ;
     RECT  139.139 154.464 139.885 155.4 ;
     RECT  139.777 230.304 139.889 231.912 ;
     RECT  139.868 132.672 139.909 132.696 ;
     RECT  139.669 167.424 139.921 211.848 ;
     RECT  138.697 212.832 139.921 215.112 ;
     RECT  139.889 230.304 139.921 231.336 ;
     RECT  139.909 132.672 139.955 133.608 ;
     RECT  139.868 135.168 139.955 135.192 ;
     RECT  139.597 144.048 139.957 144.648 ;
     RECT  139.169 220.464 139.957 220.824 ;
     RECT  138.701 150.912 139.961 150.936 ;
     RECT  138.701 157.344 139.993 158.52 ;
     RECT  139.955 133.584 139.996 133.608 ;
     RECT  139.885 163.68 140.003 163.704 ;
     RECT  139.993 157.344 140.029 158.952 ;
     RECT  139.813 148.128 140.065 148.824 ;
     RECT  139.813 164.832 140.069 165.912 ;
     RECT  139.909 216.144 140.101 216.168 ;
     RECT  139.921 230.16 140.101 231.336 ;
     RECT  138.413 225.216 140.173 225.24 ;
     RECT  138.889 226.416 140.173 226.44 ;
     RECT  139.885 154.416 140.197 155.4 ;
     RECT  140.173 225.216 140.213 226.44 ;
     RECT  139.705 136.224 140.249 136.296 ;
     RECT  139.313 234.096 140.249 234.216 ;
     RECT  139.885 137.376 140.285 137.976 ;
     RECT  139.709 139.44 140.285 139.464 ;
     RECT  139.283 146.4 140.425 146.472 ;
     RECT  140.101 229.248 140.429 231.336 ;
     RECT  139.715 240.48 140.461 240.504 ;
     RECT  139.921 167.424 140.465 215.112 ;
     RECT  140.429 229.584 140.465 231.336 ;
     RECT  139.813 161.28 140.492 162.456 ;
     RECT  139.957 220.128 140.497 220.824 ;
     RECT  140.065 147.744 140.501 148.824 ;
     RECT  140.197 154.416 140.533 155.736 ;
     RECT  139.621 224.064 140.569 224.232 ;
     RECT  140.492 161.28 140.573 163.032 ;
     RECT  140.573 161.712 140.579 163.032 ;
     RECT  140.069 165.072 140.641 165.912 ;
     RECT  139.667 217.632 140.641 217.656 ;
     RECT  139.667 219.024 140.641 219.048 ;
     RECT  139.705 244.224 140.677 244.44 ;
     RECT  140.579 161.712 140.681 162.504 ;
     RECT  139.861 141.312 140.713 141.96 ;
     RECT  140.501 148.368 140.717 148.824 ;
     RECT  140.681 161.904 140.717 162.504 ;
     RECT  140.677 243.936 140.717 244.44 ;
     RECT  139.957 144.048 140.725 144.792 ;
     RECT  140.425 146.4 140.725 146.52 ;
     RECT  139.201 222.816 140.749 222.84 ;
     RECT  140.569 224.064 140.749 224.472 ;
     RECT  140.713 141.312 140.773 142.488 ;
     RECT  140.725 144.048 140.773 146.52 ;
     RECT  140.773 141.312 140.785 146.52 ;
     RECT  140.029 157.344 140.789 159.528 ;
     RECT  140.785 140.736 140.812 146.52 ;
     RECT  140.812 140.736 140.819 145.272 ;
     RECT  140.749 237.216 140.821 237.24 ;
     RECT  140.249 234.192 140.825 234.216 ;
     RECT  140.101 216.144 140.857 216.6 ;
     RECT  140.717 148.56 140.861 148.824 ;
     RECT  140.461 239.904 140.861 240.504 ;
     RECT  140.861 239.904 140.869 240.024 ;
     RECT  140.819 143.232 140.897 145.272 ;
     RECT  140.497 220.128 140.897 221.064 ;
     RECT  140.641 165.072 140.933 166.392 ;
     RECT  139.381 238.224 140.933 238.248 ;
     RECT  140.785 134.544 140.969 134.568 ;
     RECT  140.717 243.936 140.969 244.248 ;
     RECT  140.213 225.648 141.001 226.44 ;
     RECT  140.285 137.376 141.005 137.4 ;
     RECT  140.789 158.928 141.005 159.528 ;
     RECT  140.641 217.632 141.037 219.048 ;
     RECT  140.812 146.448 141.068 146.52 ;
     RECT  140.533 150.528 141.073 150.84 ;
     RECT  139.763 228.192 141.073 228.216 ;
     RECT  140.821 236.976 141.073 237.24 ;
     RECT  140.821 241.632 141.145 241.656 ;
     RECT  140.969 243.936 141.145 243.96 ;
     RECT  140.819 140.736 141.149 141.864 ;
     RECT  140.897 144.768 141.149 145.272 ;
     RECT  140.897 143.232 141.155 143.736 ;
     RECT  141.068 146.448 141.155 147.24 ;
     RECT  140.933 165.744 141.185 166.392 ;
     RECT  141.145 243.696 141.185 243.96 ;
     RECT  140.749 132.24 141.205 132.264 ;
     RECT  141.073 233.088 141.212 233.112 ;
     RECT  141.145 241.104 141.229 241.656 ;
     RECT  140.749 222.816 141.253 224.472 ;
     RECT  141.001 225.648 141.253 226.488 ;
     RECT  141.185 166.368 141.257 166.392 ;
     RECT  141.205 132.24 141.285 132.504 ;
     RECT  141.005 159.12 141.289 159.528 ;
     RECT  141.253 222.816 141.289 226.488 ;
     RECT  141.205 133.68 141.293 134.04 ;
     RECT  140.533 154.416 141.325 155.976 ;
     RECT  140.789 157.344 141.325 157.8 ;
     RECT  141.289 222.528 141.325 226.488 ;
     RECT  141.073 228.192 141.347 228.552 ;
     RECT  140.465 229.584 141.347 230.76 ;
     RECT  139.421 235.536 141.349 235.56 ;
     RECT  141.073 236.976 141.349 237.672 ;
     RECT  141.073 150.528 141.361 151.656 ;
     RECT  141.212 233.04 141.469 233.112 ;
     RECT  141.325 154.416 141.473 157.8 ;
     RECT  141.347 228.192 141.473 228.216 ;
     RECT  141.473 154.752 141.545 157.8 ;
     RECT  141.349 235.536 141.545 237.672 ;
     RECT  141.347 229.584 141.581 230.376 ;
     RECT  141.229 241.632 141.596 241.656 ;
     RECT  138.845 152.64 141.613 152.808 ;
     RECT  140.465 167.424 141.613 214.872 ;
     RECT  140.857 215.856 141.613 216.6 ;
     RECT  141.545 235.536 141.617 237 ;
     RECT  141.596 241.632 141.683 242.28 ;
     RECT  141.185 243.696 141.683 243.72 ;
     RECT  141.289 159.12 141.721 159.72 ;
     RECT  140.717 161.904 141.721 162.456 ;
     RECT  141.361 150.48 141.749 151.656 ;
     RECT  141.721 161.904 141.757 163.224 ;
     RECT  141.749 149.856 141.793 151.656 ;
     RECT  141.793 149.76 141.797 151.656 ;
     RECT  141.545 154.752 141.797 156.696 ;
     RECT  141.613 152.64 141.827 153.768 ;
     RECT  141.797 154.752 141.827 154.776 ;
     RECT  141.757 161.904 141.827 164.088 ;
     RECT  141.827 152.64 141.829 153.48 ;
     RECT  141.469 232.512 141.829 233.112 ;
     RECT  141.827 163.68 141.865 164.088 ;
     RECT  140.869 239.904 141.865 239.928 ;
     RECT  141.325 221.712 141.901 226.488 ;
     RECT  141.721 159.12 141.973 160.008 ;
     RECT  140.897 220.128 141.973 220.584 ;
     RECT  141.901 221.712 141.973 226.728 ;
     RECT  141.613 166.656 142.009 216.6 ;
     RECT  141.037 217.632 142.009 219.144 ;
     RECT  141.829 232.272 142.081 233.112 ;
     RECT  141.865 163.68 142.333 164.76 ;
     RECT  142.225 139.104 142.369 139.128 ;
     RECT  142.009 166.656 142.369 219.144 ;
     RECT  141.827 161.904 142.405 162.696 ;
     RECT  142.081 232.032 142.433 233.256 ;
     RECT  142.405 161.712 142.441 162.696 ;
     RECT  141.865 239.904 142.441 240.072 ;
     RECT  141.253 137.904 142.453 137.928 ;
     RECT  141.155 143.232 142.477 143.448 ;
     RECT  141.149 145.248 142.477 145.272 ;
     RECT  142.369 165.84 142.501 219.144 ;
     RECT  141.973 220.128 142.501 226.728 ;
     RECT  140.785 135.984 142.508 136.008 ;
     RECT  141.581 229.68 142.549 230.376 ;
     RECT  142.433 232.032 142.549 233.496 ;
     RECT  142.453 137.52 142.585 137.928 ;
     RECT  141.617 235.728 142.621 235.752 ;
     RECT  141.617 236.976 142.621 237 ;
     RECT  142.501 165.84 142.652 226.728 ;
     RECT  142.549 227.808 142.652 227.832 ;
     RECT  142.585 137.328 142.657 137.928 ;
     RECT  142.369 139.104 142.657 139.656 ;
     RECT  142.508 135.504 142.693 136.008 ;
     RECT  142.657 137.328 142.693 139.656 ;
     RECT  142.477 145.248 142.693 145.368 ;
     RECT  141.793 147.408 142.693 147.432 ;
     RECT  140.861 148.56 142.693 148.584 ;
     RECT  141.797 149.76 142.693 151.416 ;
     RECT  142.652 165.84 142.693 227.832 ;
     RECT  142.693 144.528 142.729 145.368 ;
     RECT  142.621 235.728 142.765 237 ;
     RECT  141.285 132.48 142.808 132.504 ;
     RECT  141.293 133.92 142.808 134.04 ;
     RECT  142.693 135.504 142.808 139.656 ;
     RECT  141.149 140.736 142.808 140.76 ;
     RECT  141.149 141.84 142.808 141.864 ;
     RECT  142.477 143.184 142.808 143.448 ;
     RECT  142.729 144.528 142.808 145.704 ;
     RECT  142.693 147.408 142.808 151.416 ;
     RECT  141.829 152.448 142.808 153.48 ;
     RECT  141.797 155.952 142.808 156.696 ;
     RECT  141.545 157.776 142.808 157.8 ;
     RECT  141.973 159.12 142.808 160.056 ;
     RECT  142.441 161.52 142.808 162.696 ;
     RECT  142.333 163.68 142.808 164.856 ;
     RECT  142.693 165.84 142.808 228.072 ;
     RECT  142.549 229.68 142.808 233.496 ;
     RECT  142.449 234.576 142.808 234.6 ;
     RECT  142.765 235.728 142.808 237.528 ;
     RECT  142.441 238.992 142.808 240.072 ;
     RECT  141.683 241.632 142.808 241.848 ;
     RECT  142.808 2.148 142.912 369.372 ;
     RECT  142.912 2.418 143.104 369.102 ;
     RECT  143.104 144 143.237 146.52 ;
     RECT  143.104 232.368 143.273 233.112 ;
     RECT  143.104 147.552 143.309 159.048 ;
     RECT  143.104 214.224 143.309 216.792 ;
     RECT  143.104 235.2 143.363 238.872 ;
     RECT  143.237 145.104 143.381 146.52 ;
     RECT  143.104 161.52 143.381 165.096 ;
     RECT  143.309 148.56 143.411 159.048 ;
     RECT  143.363 236.496 143.417 238.872 ;
     RECT  143.411 155.952 143.452 159.048 ;
     RECT  143.104 140.448 143.453 140.76 ;
     RECT  143.452 157.008 143.453 159.048 ;
     RECT  143.104 222.336 143.453 226.728 ;
     RECT  143.104 220.704 143.489 220.728 ;
     RECT  143.104 136.08 143.705 137.352 ;
     RECT  143.381 145.104 143.741 145.752 ;
     RECT  143.411 148.56 143.741 154.488 ;
     RECT  143.453 159.024 143.741 159.048 ;
     RECT  143.309 147.552 143.795 147.576 ;
     RECT  143.104 138.576 143.813 138.6 ;
     RECT  143.741 148.56 143.849 154.008 ;
     RECT  143.104 132.192 143.957 132.504 ;
     RECT  143.104 227.952 144.029 229.224 ;
     RECT  143.381 163.776 144.065 165.096 ;
     RECT  143.453 223.92 144.065 226.728 ;
     RECT  143.417 236.496 144.131 238.584 ;
     RECT  143.104 241.104 144.131 241.128 ;
     RECT  143.453 140.688 144.133 140.76 ;
     RECT  143.104 160.032 144.133 160.344 ;
     RECT  144.065 223.92 144.137 224.568 ;
     RECT  143.104 234.192 144.169 234.216 ;
     RECT  144.085 239.568 144.172 239.592 ;
     RECT  143.849 148.56 144.173 153.336 ;
     RECT  144.065 225.888 144.209 226.728 ;
     RECT  144.131 236.496 144.209 237.816 ;
     RECT  144.133 140.688 144.229 141.576 ;
     RECT  143.237 144 144.229 144.12 ;
     RECT  143.104 134.88 144.245 134.904 ;
     RECT  144.065 163.776 144.245 164.568 ;
     RECT  144.173 150.432 144.253 153.336 ;
     RECT  144.229 140.688 144.275 142.776 ;
     RECT  144.229 144 144.275 144.552 ;
     RECT  144.229 139.632 144.277 139.656 ;
     RECT  143.104 219.36 144.277 219.672 ;
     RECT  143.957 132.192 144.281 132.216 ;
     RECT  143.104 166.08 144.281 212.712 ;
     RECT  144.029 227.952 144.281 229.176 ;
     RECT  144.169 234.192 144.281 234.312 ;
     RECT  144.281 166.08 144.313 212.136 ;
     RECT  143.381 161.52 144.389 162.36 ;
     RECT  144.209 236.496 144.421 237.096 ;
     RECT  144.133 159.216 144.457 160.344 ;
     RECT  144.389 161.52 144.457 161.928 ;
     RECT  144.275 141.888 144.461 142.776 ;
     RECT  144.277 137.952 144.467 137.976 ;
     RECT  143.452 155.952 144.493 155.976 ;
     RECT  144.281 227.952 144.517 227.976 ;
     RECT  144.277 139.104 144.533 139.656 ;
     RECT  144.517 227.52 144.563 227.976 ;
     RECT  144.281 229.152 144.563 229.176 ;
     RECT  143.453 222.336 144.601 222.6 ;
     RECT  144.137 223.92 144.601 224.184 ;
     RECT  144.563 227.52 144.604 227.544 ;
     RECT  144.277 219.36 144.611 220.008 ;
     RECT  144.524 230.784 144.611 230.808 ;
     RECT  143.705 136.08 144.661 136.968 ;
     RECT  144.601 163.392 144.673 163.56 ;
     RECT  144.611 219.36 144.677 219.384 ;
     RECT  143.741 145.728 144.709 145.752 ;
     RECT  144.275 144.528 144.745 144.552 ;
     RECT  144.709 145.728 144.745 146.28 ;
     RECT  144.493 155.808 144.745 155.976 ;
     RECT  143.453 157.008 144.745 157.848 ;
     RECT  143.309 214.224 144.745 215.4 ;
     RECT  144.457 159.216 144.749 161.928 ;
     RECT  144.565 231.984 144.749 232.008 ;
     RECT  144.565 221.184 144.781 221.208 ;
     RECT  144.421 235.968 144.821 237.096 ;
     RECT  144.745 155.808 144.857 157.848 ;
     RECT  143.309 216.48 144.908 216.792 ;
     RECT  143.104 218.112 144.908 218.136 ;
     RECT  144.745 144.528 144.925 146.28 ;
     RECT  144.253 150.768 144.925 153.336 ;
     RECT  144.313 165.744 144.929 212.136 ;
     RECT  144.929 165.744 144.947 195.48 ;
     RECT  144.908 216.48 144.949 218.136 ;
     RECT  144.661 135.36 145.001 136.968 ;
     RECT  144.947 167.52 145.037 195.48 ;
     RECT  144.781 220.608 145.037 221.208 ;
     RECT  144.209 225.888 145.037 225.912 ;
     RECT  143.273 233.088 145.037 233.112 ;
     RECT  144.749 159.216 145.069 161.544 ;
     RECT  144.949 216.48 145.073 219 ;
     RECT  145.052 134.064 145.093 134.088 ;
     RECT  145.093 133.344 145.139 134.088 ;
     RECT  144.929 196.656 145.244 212.136 ;
     RECT  144.745 213.36 145.244 215.4 ;
     RECT  145.244 196.656 145.249 215.4 ;
     RECT  145.073 216.48 145.249 217.176 ;
     RECT  145.037 167.52 145.253 169.32 ;
     RECT  145.001 136.464 145.285 136.968 ;
     RECT  145.001 135.36 145.331 135.384 ;
     RECT  145.285 136.464 145.331 137.352 ;
     RECT  145.249 196.656 145.331 217.176 ;
     RECT  144.925 150.768 145.357 153.432 ;
     RECT  144.245 164.544 145.357 164.568 ;
     RECT  145.285 240.624 145.379 240.648 ;
     RECT  144.673 163.296 145.381 163.56 ;
     RECT  145.357 164.544 145.381 165.336 ;
     RECT  144.173 148.56 145.393 148.68 ;
     RECT  144.601 222.336 145.429 224.184 ;
     RECT  145.357 150.768 145.465 153.72 ;
     RECT  145.331 196.656 145.505 212.136 ;
     RECT  145.253 167.52 145.541 169.224 ;
     RECT  144.947 166.416 145.577 166.44 ;
     RECT  145.541 167.52 145.619 169.032 ;
     RECT  145.139 133.344 145.685 133.368 ;
     RECT  145.505 196.8 145.685 212.136 ;
     RECT  145.331 213.456 145.757 217.176 ;
     RECT  144.821 237.072 145.789 237.096 ;
     RECT  145.429 222.336 145.813 225.144 ;
     RECT  145.789 237.024 145.813 237.096 ;
     RECT  145.685 196.8 145.829 210.312 ;
     RECT  144.925 144.528 145.861 146.616 ;
     RECT  145.393 148.128 145.861 148.68 ;
     RECT  145.861 144.528 145.865 148.68 ;
     RECT  145.465 150.48 145.865 153.72 ;
     RECT  145.813 237.024 145.873 237.72 ;
     RECT  145.681 227.04 145.897 227.064 ;
     RECT  144.997 239.328 145.897 239.352 ;
     RECT  145.813 222.288 145.9 225.144 ;
     RECT  145.331 137.328 145.901 137.352 ;
     RECT  144.857 155.808 145.901 157.368 ;
     RECT  144.821 235.968 145.907 235.992 ;
     RECT  145.897 227.04 145.933 227.592 ;
     RECT  145.381 163.296 145.937 165.336 ;
     RECT  145.037 170.304 145.955 195.48 ;
     RECT  144.281 234.192 146.009 234.216 ;
     RECT  145.933 227.04 146.045 228.792 ;
     RECT  145.829 199.632 146.051 210.312 ;
     RECT  144.533 139.104 146.077 139.128 ;
     RECT  145.901 156.336 146.077 157.368 ;
     RECT  145.573 221.28 146.077 221.304 ;
     RECT  145.873 237.072 146.077 237.72 ;
     RECT  145.865 153.264 146.113 153.72 ;
     RECT  145.073 218.304 146.113 219 ;
     RECT  145.865 144.528 146.117 148.584 ;
     RECT  145.955 170.304 146.147 195.336 ;
     RECT  146.077 139.104 146.149 139.752 ;
     RECT  144.275 140.736 146.149 140.76 ;
     RECT  144.461 141.888 146.149 142.2 ;
     RECT  145.789 143.232 146.149 143.256 ;
     RECT  146.045 228.768 146.149 228.792 ;
     RECT  145.033 230.448 146.149 230.568 ;
     RECT  146.149 139.104 146.153 140.76 ;
     RECT  146.147 170.304 146.189 194.232 ;
     RECT  146.149 228.768 146.189 230.568 ;
     RECT  146.153 139.632 146.197 140.76 ;
     RECT  146.113 153.264 146.225 154.488 ;
     RECT  146.051 207.648 146.225 210.312 ;
     RECT  146.189 170.304 146.257 186.792 ;
     RECT  146.147 195.264 146.261 195.336 ;
     RECT  146.189 187.776 146.291 194.232 ;
     RECT  146.189 228.768 146.291 229.704 ;
     RECT  146.077 156.336 146.293 157.944 ;
     RECT  145.069 159.12 146.293 161.544 ;
     RECT  146.077 220.704 146.293 221.304 ;
     RECT  146.291 187.776 146.297 194.088 ;
     RECT  146.261 195.264 146.333 195.288 ;
     RECT  146.117 144.528 146.405 147.096 ;
     RECT  146.257 170.208 146.405 186.792 ;
     RECT  146.405 144.528 146.437 145.944 ;
     RECT  145.865 150.48 146.437 152.184 ;
     RECT  145.685 212.112 146.437 212.136 ;
     RECT  145.757 213.456 146.437 216.504 ;
     RECT  146.437 144.336 146.441 145.944 ;
     RECT  146.293 220.368 146.441 221.304 ;
     RECT  146.197 139.728 146.485 140.76 ;
     RECT  146.149 141.888 146.485 143.256 ;
     RECT  146.225 207.648 146.549 210.12 ;
     RECT  146.437 212.112 146.549 216.504 ;
     RECT  146.113 218.304 146.549 219.192 ;
     RECT  146.405 170.256 146.572 186.792 ;
     RECT  146.485 139.728 146.585 143.256 ;
     RECT  145.937 163.392 146.621 165.336 ;
     RECT  146.045 227.04 146.621 227.592 ;
     RECT  146.621 227.52 146.657 227.592 ;
     RECT  146.051 199.632 146.675 206.472 ;
     RECT  146.437 150.048 146.677 152.184 ;
     RECT  145.9 222.432 146.684 225.144 ;
     RECT  146.549 212.112 146.693 214.968 ;
     RECT  146.585 139.728 146.771 142.536 ;
     RECT  146.684 222.432 146.771 225.528 ;
     RECT  146.693 212.112 146.797 213.192 ;
     RECT  146.117 148.128 146.837 148.584 ;
     RECT  145.897 239.328 146.837 239.88 ;
     RECT  146.293 156.336 146.869 161.544 ;
     RECT  146.771 141.312 146.873 142.536 ;
     RECT  146.572 170.256 146.915 177.48 ;
     RECT  146.869 156.336 146.941 161.592 ;
     RECT  146.941 156.24 146.972 161.592 ;
     RECT  146.329 230.88 146.981 230.904 ;
     RECT  146.972 156.24 147.011 161.784 ;
     RECT  147.011 157.632 147.013 161.784 ;
     RECT  146.621 163.392 147.013 164.664 ;
     RECT  145.619 167.568 147.013 169.032 ;
     RECT  147.013 157.632 147.017 164.664 ;
     RECT  146.873 141.504 147.059 142.536 ;
     RECT  146.677 149.904 147.059 152.184 ;
     RECT  145.829 196.8 147.085 198.552 ;
     RECT  146.771 139.728 147.089 140.136 ;
     RECT  146.441 144.336 147.089 145.848 ;
     RECT  146.675 205.824 147.089 206.472 ;
     RECT  146.291 229.68 147.089 229.704 ;
     RECT  146.837 239.328 147.089 239.352 ;
     RECT  146.941 233.616 147.096 233.64 ;
     RECT  147.096 233.616 147.116 233.688 ;
     RECT  146.077 237.072 147.121 237.864 ;
     RECT  147.059 142.512 147.125 142.536 ;
     RECT  147.121 237.072 147.157 238.248 ;
     RECT  146.771 222.432 147.161 225.144 ;
     RECT  147.157 235.776 147.161 238.248 ;
     RECT  147.116 233.616 147.203 234.456 ;
     RECT  147.089 205.92 147.265 206.472 ;
     RECT  146.549 207.648 147.265 209.928 ;
     RECT  146.549 216.048 147.265 216.504 ;
     RECT  147.085 196.8 147.301 198.648 ;
     RECT  146.675 199.632 147.301 204.744 ;
     RECT  147.013 166.896 147.373 169.032 ;
     RECT  146.915 170.256 147.373 177.24 ;
     RECT  147.059 149.904 147.445 149.976 ;
     RECT  146.297 187.776 147.445 190.392 ;
     RECT  146.297 191.52 147.445 194.088 ;
     RECT  147.301 196.8 147.445 204.744 ;
     RECT  146.549 218.304 147.445 218.712 ;
     RECT  147.011 156.24 147.553 156.36 ;
     RECT  146.572 179.136 147.553 186.792 ;
     RECT  147.445 187.776 147.553 190.44 ;
     RECT  147.445 196.704 147.581 204.744 ;
     RECT  147.265 216.048 147.625 217.176 ;
     RECT  147.445 218.208 147.625 218.712 ;
     RECT  147.625 216.048 147.637 218.712 ;
     RECT  147.017 158.784 147.685 164.664 ;
     RECT  146.693 214.416 147.733 214.968 ;
     RECT  147.161 222.432 147.733 223.032 ;
     RECT  146.441 220.368 147.769 220.68 ;
     RECT  146.225 153.264 147.836 153.912 ;
     RECT  146.405 147.072 147.877 147.096 ;
     RECT  147.373 166.896 147.913 177.24 ;
     RECT  147.913 166.896 147.949 177.816 ;
     RECT  147.581 196.032 147.949 204.744 ;
     RECT  147.553 179.136 148.021 190.44 ;
     RECT  147.445 191.52 148.021 194.76 ;
     RECT  147.265 205.92 148.093 209.928 ;
     RECT  146.797 211.248 148.093 213.192 ;
     RECT  147.161 224.16 148.093 225.144 ;
     RECT  147.553 226.32 148.093 226.344 ;
     RECT  147.089 140.112 148.208 140.136 ;
     RECT  147.059 141.504 148.208 141.528 ;
     RECT  147.089 144.48 148.208 145.848 ;
     RECT  147.877 147.072 148.208 147.624 ;
     RECT  147.445 148.752 148.208 149.976 ;
     RECT  147.059 151.392 148.208 151.944 ;
     RECT  147.836 153.264 148.208 154.68 ;
     RECT  147.553 156.144 148.208 156.36 ;
     RECT  147.017 157.632 148.208 157.656 ;
     RECT  147.685 158.784 148.208 164.76 ;
     RECT  147.949 165.936 148.208 177.816 ;
     RECT  148.021 179.136 148.208 194.76 ;
     RECT  147.949 196.032 148.208 204.84 ;
     RECT  148.093 205.92 148.208 213.192 ;
     RECT  147.733 214.32 148.208 214.968 ;
     RECT  147.637 216.048 148.208 218.856 ;
     RECT  147.769 219.984 148.208 220.68 ;
     RECT  147.733 222.288 148.208 223.032 ;
     RECT  148.093 224.16 148.208 226.344 ;
     RECT  146.657 227.52 148.208 227.544 ;
     RECT  147.985 229.056 148.208 229.08 ;
     RECT  147.661 231.312 148.208 231.336 ;
     RECT  147.337 232.56 148.208 232.584 ;
     RECT  147.203 233.616 148.208 234.024 ;
     RECT  147.161 235.776 148.208 237.24 ;
     RECT  147.161 238.224 148.208 238.248 ;
     RECT  148.208 2.148 148.312 369.372 ;
     RECT  148.312 2.418 148.504 369.102 ;
     RECT  148.504 144.24 148.565 144.552 ;
     RECT  148.504 158.496 148.565 158.568 ;
     RECT  148.504 200.592 148.637 208.536 ;
     RECT  148.504 151.008 148.643 151.944 ;
     RECT  148.504 162.336 148.643 190.92 ;
     RECT  148.504 217.68 148.643 218.856 ;
     RECT  148.504 223.296 148.643 227.496 ;
     RECT  148.637 200.592 148.645 204.264 ;
     RECT  148.637 205.536 148.673 208.536 ;
     RECT  148.504 210.912 148.709 211.32 ;
     RECT  148.643 217.728 148.709 218.856 ;
     RECT  148.504 155.76 148.781 156.264 ;
     RECT  148.504 192.528 148.781 196.056 ;
     RECT  148.709 210.912 148.781 211.224 ;
     RECT  148.504 212.304 148.781 216.072 ;
     RECT  148.504 147.6 148.853 147.624 ;
     RECT  148.673 207.792 148.889 208.536 ;
     RECT  148.781 214.512 148.889 216.072 ;
     RECT  148.643 223.296 148.889 225.96 ;
     RECT  148.504 159.744 148.961 161.304 ;
     RECT  148.889 223.296 148.997 224.808 ;
     RECT  148.709 218.256 149.069 218.856 ;
     RECT  148.781 156.24 149.105 156.264 ;
     RECT  148.504 234 149.105 234.024 ;
     RECT  148.504 219.984 149.123 220.008 ;
     RECT  148.504 149.136 149.141 149.976 ;
     RECT  148.643 162.336 149.141 172.632 ;
     RECT  148.504 221.184 149.164 221.832 ;
     RECT  149.141 149.328 149.213 149.976 ;
     RECT  149.141 167.184 149.219 172.632 ;
     RECT  148.504 153.552 149.249 154.584 ;
     RECT  149.141 162.336 149.249 165.96 ;
     RECT  148.781 212.304 149.249 212.808 ;
     RECT  149.249 212.304 149.267 212.616 ;
     RECT  148.643 173.952 149.285 190.92 ;
     RECT  148.781 195.264 149.315 196.056 ;
     RECT  149.249 162.336 149.321 165.624 ;
     RECT  148.504 235.92 149.321 235.944 ;
     RECT  149.069 218.784 149.357 218.856 ;
     RECT  149.249 153.792 149.363 154.584 ;
     RECT  148.673 205.536 149.363 206.472 ;
     RECT  149.363 205.536 149.393 206.184 ;
     RECT  149.321 164.496 149.465 165.624 ;
     RECT  148.781 192.528 149.465 193.752 ;
     RECT  149.393 206.16 149.465 206.184 ;
     RECT  149.465 192.528 149.497 193.512 ;
     RECT  149.285 177.696 149.533 190.92 ;
     RECT  149.497 192 149.533 193.512 ;
     RECT  148.504 231.984 149.537 232.008 ;
     RECT  148.504 198.336 149.569 199.608 ;
     RECT  149.357 218.832 149.569 218.856 ;
     RECT  148.645 200.784 149.605 204.264 ;
     RECT  149.497 230.304 149.609 230.328 ;
     RECT  149.219 167.28 149.645 172.632 ;
     RECT  149.569 218.832 149.645 219.576 ;
     RECT  149.569 198.144 149.677 199.608 ;
     RECT  149.605 200.784 149.677 204.744 ;
     RECT  148.504 209.616 149.699 209.784 ;
     RECT  149.533 177.696 149.753 193.512 ;
     RECT  149.677 198.144 149.753 204.744 ;
     RECT  148.889 215.28 149.753 216.072 ;
     RECT  148.889 225.888 149.753 225.96 ;
     RECT  148.643 227.472 149.753 227.496 ;
     RECT  148.997 223.392 149.795 224.808 ;
     RECT  149.315 195.264 149.825 196.008 ;
     RECT  148.781 210.912 149.857 210.936 ;
     RECT  149.267 212.304 149.857 212.568 ;
     RECT  149.795 223.392 149.861 223.416 ;
     RECT  148.961 159.936 149.891 161.304 ;
     RECT  149.825 195.264 149.893 195.768 ;
     RECT  149.285 173.952 149.897 176.664 ;
     RECT  149.753 177.696 149.897 184.104 ;
     RECT  149.891 159.936 149.929 160.152 ;
     RECT  149.897 177.696 149.933 183.912 ;
     RECT  149.753 225.936 149.933 225.96 ;
     RECT  149.753 185.28 149.969 193.512 ;
     RECT  149.893 194.784 149.976 195.768 ;
     RECT  148.504 146.448 149.989 146.472 ;
     RECT  149.645 167.568 150.001 172.632 ;
     RECT  149.933 177.696 150.005 183.192 ;
     RECT  149.929 159.504 150.041 160.152 ;
     RECT  148.565 144.24 150.069 144.264 ;
     RECT  149.989 145.536 150.076 146.472 ;
     RECT  150.005 177.696 150.077 181.464 ;
     RECT  149.976 194.736 150.109 195.768 ;
     RECT  150.076 146.448 150.113 146.472 ;
     RECT  150.005 183.12 150.149 183.192 ;
     RECT  149.363 154.512 150.181 154.584 ;
     RECT  150.001 197.04 150.181 197.064 ;
     RECT  149.753 198.144 150.185 204.312 ;
     RECT  149.699 209.712 150.185 209.784 ;
     RECT  148.889 208.224 150.217 208.536 ;
     RECT  149.897 173.952 150.221 175.176 ;
     RECT  149.465 165.6 150.289 165.624 ;
     RECT  149.897 176.16 150.325 176.664 ;
     RECT  150.077 177.696 150.325 178.44 ;
     RECT  149.753 215.28 150.325 215.448 ;
     RECT  150.181 154.512 150.361 154.824 ;
     RECT  150.185 202.848 150.401 204.312 ;
     RECT  150.185 209.712 150.401 209.736 ;
     RECT  150.073 148.176 150.433 148.2 ;
     RECT  149.213 149.328 150.433 149.352 ;
     RECT  149.891 161.28 150.433 161.304 ;
     RECT  149.321 162.336 150.433 163.464 ;
     RECT  150.217 207.984 150.437 208.536 ;
     RECT  149.465 164.496 150.467 164.52 ;
     RECT  150.325 176.16 150.467 178.44 ;
     RECT  150.467 176.4 150.473 178.44 ;
     RECT  149.857 210.912 150.497 212.568 ;
     RECT  150.289 165.6 150.505 165.96 ;
     RECT  150.041 159.6 150.509 160.152 ;
     RECT  150.185 198.144 150.509 201.864 ;
     RECT  150.497 210.912 150.509 213.192 ;
     RECT  150.505 157.296 150.517 157.32 ;
     RECT  148.565 158.496 150.517 158.52 ;
     RECT  150.181 197.04 150.572 197.16 ;
     RECT  150.509 198.144 150.572 200.136 ;
     RECT  150.517 157.296 150.581 158.52 ;
     RECT  150.509 159.6 150.581 160.104 ;
     RECT  150.001 167.568 150.581 172.728 ;
     RECT  150.509 211.056 150.581 213.192 ;
     RECT  150.433 149.328 150.613 149.88 ;
     RECT  150.572 197.04 150.659 200.136 ;
     RECT  150.509 201.504 150.689 201.864 ;
     RECT  150.109 194.688 150.725 195.768 ;
     RECT  149.645 219.024 150.761 219.576 ;
     RECT  150.361 154.512 150.797 154.968 ;
     RECT  150.433 147.744 150.86 148.2 ;
     RECT  150.613 149.328 150.86 150.312 ;
     RECT  150.725 194.688 150.869 195.672 ;
     RECT  150.659 198.528 150.869 200.136 ;
     RECT  150.86 147.744 150.901 150.312 ;
     RECT  148.643 151.344 150.901 151.944 ;
     RECT  150.433 153.504 150.908 153.528 ;
     RECT  150.581 167.568 150.941 171.48 ;
     RECT  150.401 204.048 150.941 204.312 ;
     RECT  150.901 147.6 150.947 151.944 ;
     RECT  150.908 153.072 150.949 153.528 ;
     RECT  150.797 154.512 150.949 154.68 ;
     RECT  149.969 185.28 150.977 193.272 ;
     RECT  150.325 214.704 150.977 215.448 ;
     RECT  150.947 150.432 150.995 151.944 ;
     RECT  150.949 153.072 150.995 154.68 ;
     RECT  150.505 164.736 151.013 165.96 ;
     RECT  150.995 150.432 151.043 151.416 ;
     RECT  150.977 185.28 151.049 193.176 ;
     RECT  150.869 198.72 151.049 200.136 ;
     RECT  150.437 208.224 151.049 208.536 ;
     RECT  150.947 149.328 151.085 149.352 ;
     RECT  150.941 168.24 151.085 171.48 ;
     RECT  150.581 211.056 151.085 212.328 ;
     RECT  151.085 170.304 151.091 171.48 ;
     RECT  150.517 156.144 151.141 156.168 ;
     RECT  151.049 185.28 151.148 189.96 ;
     RECT  151.049 198.72 151.157 199.56 ;
     RECT  151.091 170.4 151.187 171.48 ;
     RECT  150.505 217.728 151.196 217.752 ;
     RECT  150.433 161.28 151.225 163.464 ;
     RECT  150.149 183.168 151.229 183.192 ;
     RECT  151.148 184.32 151.235 189.96 ;
     RECT  150.761 219.552 151.237 219.576 ;
     RECT  150.689 201.552 151.261 201.864 ;
     RECT  150.401 202.848 151.261 202.872 ;
     RECT  150.947 147.6 151.265 147.624 ;
     RECT  151.085 168.672 151.265 168.936 ;
     RECT  151.196 217.728 151.265 217.848 ;
     RECT  151.265 217.824 151.283 217.848 ;
     RECT  151.237 219.552 151.283 219.72 ;
     RECT  151.009 196.8 151.301 196.824 ;
     RECT  151.013 165.6 151.337 165.96 ;
     RECT  151.141 155.664 151.369 156.168 ;
     RECT  150.581 157.296 151.369 157.848 ;
     RECT  151.043 150.432 151.373 150.888 ;
     RECT  150.581 159.6 151.373 159.816 ;
     RECT  151.235 184.656 151.373 189.96 ;
     RECT  150.869 194.688 151.405 194.76 ;
     RECT  151.405 194.496 151.409 194.76 ;
     RECT  151.085 211.056 151.409 211.752 ;
     RECT  150.077 179.424 151.441 181.464 ;
     RECT  150.221 174.048 151.477 175.176 ;
     RECT  150.473 176.4 151.477 177.72 ;
     RECT  151.373 184.656 151.481 188.376 ;
     RECT  151.441 179.424 151.513 181.704 ;
     RECT  150.941 204.096 151.517 204.312 ;
     RECT  151.409 194.496 151.549 194.712 ;
     RECT  151.373 159.6 151.553 159.672 ;
     RECT  149.164 221.184 151.621 221.208 ;
     RECT  151.477 174.048 151.657 177.72 ;
     RECT  150.977 215.424 151.661 215.448 ;
     RECT  151.297 225.792 151.661 225.816 ;
     RECT  150.581 172.704 151.733 172.728 ;
     RECT  151.517 204.096 151.733 204.12 ;
     RECT  151.369 155.664 151.769 157.848 ;
     RECT  151.337 165.936 151.801 165.96 ;
     RECT  151.657 173.904 151.805 177.72 ;
     RECT  151.621 221.184 151.805 222.12 ;
     RECT  151.157 198.72 151.837 199.512 ;
     RECT  151.769 157.296 151.841 157.848 ;
     RECT  151.801 165.936 151.841 166.44 ;
     RECT  151.765 213.456 151.873 213.48 ;
     RECT  151.805 173.904 151.877 174.6 ;
     RECT  151.409 211.056 151.877 211.56 ;
     RECT  151.877 173.904 151.907 173.928 ;
     RECT  151.837 198.24 151.949 199.512 ;
     RECT  151.841 166.416 151.964 166.44 ;
     RECT  151.964 166.416 151.981 166.872 ;
     RECT  151.805 175.824 151.985 177.72 ;
     RECT  151.373 150.432 152.005 150.456 ;
     RECT  151.225 161.28 152.005 163.752 ;
     RECT  151.861 172.608 152.017 172.632 ;
     RECT  151.189 143.856 152.051 143.88 ;
     RECT  151.964 146.544 152.051 146.568 ;
     RECT  151.187 170.4 152.051 171.336 ;
     RECT  151.985 176.928 152.089 177.72 ;
     RECT  151.261 201.552 152.089 202.872 ;
     RECT  152.005 144.96 152.093 144.984 ;
     RECT  151.549 194.4 152.093 194.712 ;
     RECT  150.995 154.032 152.125 154.68 ;
     RECT  151.769 155.664 152.125 155.688 ;
     RECT  152.005 161.088 152.125 163.752 ;
     RECT  152.053 164.736 152.125 164.76 ;
     RECT  151.981 166.416 152.125 167.544 ;
     RECT  151.265 168.672 152.125 168.696 ;
     RECT  151.049 191.616 152.125 193.176 ;
     RECT  151.373 189.6 152.156 189.96 ;
     RECT  152.125 190.944 152.156 193.176 ;
     RECT  152.093 194.4 152.156 194.424 ;
     RECT  152.089 200.64 152.161 202.872 ;
     RECT  152.156 189.6 152.237 194.424 ;
     RECT  152.237 189.6 152.243 190.44 ;
     RECT  152.237 191.616 152.243 194.424 ;
     RECT  152.125 161.088 152.245 164.76 ;
     RECT  152.005 149.472 152.273 150.456 ;
     RECT  151.873 213.12 152.309 213.48 ;
     RECT  151.553 159.648 152.337 159.672 ;
     RECT  151.949 198.336 152.341 199.512 ;
     RECT  152.161 200.64 152.341 203.688 ;
     RECT  152.245 158.4 152.381 158.424 ;
     RECT  152.341 198.336 152.381 203.688 ;
     RECT  152.243 194.4 152.417 194.424 ;
     RECT  151.765 196.608 152.444 196.632 ;
     RECT  151.985 175.824 152.445 175.848 ;
     RECT  152.089 176.928 152.453 178.44 ;
     RECT  152.381 198.336 152.453 201.816 ;
     RECT  151.513 179.424 152.457 181.848 ;
     RECT  152.444 183.12 152.457 183.144 ;
     RECT  152.453 177.456 152.489 178.44 ;
     RECT  151.283 219.696 152.521 219.72 ;
     RECT  152.457 179.424 152.531 183.144 ;
     RECT  152.444 196.608 152.531 197.208 ;
     RECT  152.245 161.04 152.561 164.76 ;
     RECT  152.531 196.608 152.561 196.632 ;
     RECT  152.531 179.424 152.588 182.424 ;
     RECT  152.561 161.088 152.597 164.76 ;
     RECT  152.453 198.336 152.605 200.424 ;
     RECT  152.161 216 152.633 216.024 ;
     RECT  152.125 154.032 152.725 155.688 ;
     RECT  152.243 189.6 152.953 190.344 ;
     RECT  152.051 170.544 153.061 171.336 ;
     RECT  152.629 224.736 153.097 224.76 ;
     RECT  151.481 184.704 153.169 188.376 ;
     RECT  152.953 189.408 153.169 190.344 ;
     RECT  152.521 219.456 153.205 219.72 ;
     RECT  152.597 164.544 153.26 164.76 ;
     RECT  153.169 184.704 153.277 190.344 ;
     RECT  153.241 222.864 153.277 223.128 ;
     RECT  152.161 226.368 153.277 226.392 ;
     RECT  152.125 166.416 153.385 168.696 ;
     RECT  153.26 164.544 153.421 165.096 ;
     RECT  153.385 166.368 153.421 168.696 ;
     RECT  152.953 159.12 153.457 159.144 ;
     RECT  153.277 222.864 153.457 223.416 ;
     RECT  151.049 208.512 153.493 208.536 ;
     RECT  152.273 149.472 153.608 149.496 ;
     RECT  152.521 151.872 153.608 151.896 ;
     RECT  152.725 153.12 153.608 155.688 ;
     RECT  151.841 157.296 153.608 157.32 ;
     RECT  153.457 159.12 153.608 159.432 ;
     RECT  152.597 161.088 153.608 163.464 ;
     RECT  153.421 164.544 153.608 168.696 ;
     RECT  153.061 170.448 153.608 171.336 ;
     RECT  152.017 172.56 153.608 172.632 ;
     RECT  152.489 177.456 153.608 178.296 ;
     RECT  152.588 179.328 153.608 182.424 ;
     RECT  153.277 183.744 153.608 190.344 ;
     RECT  152.243 191.616 153.608 193.176 ;
     RECT  152.605 199.056 153.608 200.424 ;
     RECT  152.453 201.552 153.608 201.816 ;
     RECT  152.381 202.848 153.608 203.688 ;
     RECT  153.421 206.4 153.608 206.424 ;
     RECT  153.493 208.512 153.608 208.632 ;
     RECT  153.421 210.24 153.608 210.264 ;
     RECT  151.877 211.344 153.608 211.56 ;
     RECT  153.097 212.64 153.608 212.664 ;
     RECT  152.629 213.744 153.608 213.816 ;
     RECT  153.241 217.824 153.608 217.848 ;
     RECT  153.205 219.456 153.608 220.2 ;
     RECT  151.805 221.184 153.608 221.208 ;
     RECT  153.457 222.624 153.608 223.416 ;
     RECT  153.097 224.736 153.608 225.048 ;
     RECT  153.277 226.32 153.608 226.392 ;
     RECT  152.701 227.376 153.608 227.4 ;
     RECT  152.593 228.72 153.608 228.744 ;
     RECT  153.608 2.148 153.712 369.372 ;
     RECT  153.712 2.418 153.904 369.102 ;
     RECT  153.904 159.12 153.929 159.672 ;
     RECT  153.904 177.456 153.965 177.72 ;
     RECT  153.904 183.744 153.965 183.768 ;
     RECT  153.904 200.976 153.965 204.6 ;
     RECT  153.904 221.184 153.965 221.208 ;
     RECT  153.904 178.944 154.019 182.616 ;
     RECT  153.904 205.968 154.045 206.664 ;
     RECT  153.904 199.056 154.109 199.848 ;
     RECT  153.904 217.152 154.109 219.72 ;
     RECT  153.904 157.296 154.181 157.32 ;
     RECT  153.965 204.384 154.181 204.6 ;
     RECT  154.045 206.064 154.253 206.664 ;
     RECT  154.109 199.824 154.259 199.848 ;
     RECT  153.904 172.416 154.289 172.728 ;
     RECT  153.904 191.616 154.289 193.992 ;
     RECT  153.904 209.904 154.289 210.552 ;
     RECT  153.904 222.48 154.325 223.032 ;
     RECT  153.904 224.256 154.361 225.144 ;
     RECT  153.904 226.176 154.361 226.296 ;
     RECT  153.965 200.976 154.433 202.92 ;
     RECT  154.289 210.24 154.433 210.552 ;
     RECT  154.325 222.672 154.469 223.032 ;
     RECT  154.361 224.256 154.469 224.52 ;
     RECT  153.904 160.704 154.505 162.744 ;
     RECT  153.904 173.856 154.505 173.88 ;
     RECT  154.361 226.176 154.505 226.2 ;
     RECT  153.904 212.64 154.537 213.624 ;
     RECT  154.537 213.6 154.54 213.624 ;
     RECT  154.505 160.704 154.541 162.168 ;
     RECT  154.541 160.704 154.577 160.728 ;
     RECT  154.433 210.336 154.577 210.552 ;
     RECT  154.577 210.336 154.613 210.36 ;
     RECT  154.109 217.152 154.613 218.856 ;
     RECT  154.469 223.008 154.613 223.032 ;
     RECT  154.469 224.496 154.613 224.52 ;
     RECT  154.289 172.416 154.649 172.632 ;
     RECT  153.904 169.92 154.685 171.336 ;
     RECT  154.019 178.944 154.685 182.424 ;
     RECT  153.904 185.952 154.685 189.624 ;
     RECT  153.904 154.032 154.721 155.64 ;
     RECT  154.721 154.224 154.739 155.64 ;
     RECT  153.904 197.184 154.757 197.208 ;
     RECT  153.904 184.896 154.892 184.92 ;
     RECT  154.892 184.752 154.925 184.92 ;
     RECT  154.433 201.552 154.937 202.92 ;
     RECT  154.685 169.92 155.009 169.944 ;
     RECT  154.925 184.752 155.009 185.016 ;
     RECT  154.937 202.848 155.027 202.92 ;
     RECT  154.541 161.856 155.081 162.168 ;
     RECT  153.904 168.288 155.081 168.312 ;
     RECT  154.613 217.152 155.081 218.04 ;
     RECT  154.685 186.144 155.153 189.624 ;
     RECT  153.904 195.504 155.221 195.576 ;
     RECT  154.933 165.552 155.261 165.576 ;
     RECT  154.289 192.432 155.261 193.992 ;
     RECT  155.221 195.264 155.261 195.576 ;
     RECT  154.937 201.552 155.261 201.576 ;
     RECT  155.257 174.96 155.317 174.984 ;
     RECT  155.009 184.752 155.333 184.92 ;
     RECT  154.685 171.312 155.365 171.336 ;
     RECT  154.649 172.416 155.365 172.44 ;
     RECT  155.027 202.896 155.369 202.92 ;
     RECT  155.317 174.432 155.404 174.984 ;
     RECT  155.293 167.376 155.437 167.4 ;
     RECT  154.253 206.16 155.545 206.664 ;
     RECT  155.261 192.432 155.555 193.944 ;
     RECT  155.261 195.264 155.555 195.528 ;
     RECT  155.555 192.432 155.585 193.752 ;
     RECT  155.437 166.416 155.621 167.4 ;
     RECT  155.365 171.312 155.621 172.44 ;
     RECT  153.904 215.904 155.621 215.928 ;
     RECT  155.621 171.504 155.693 172.44 ;
     RECT  155.404 174.96 155.729 174.984 ;
     RECT  154.685 178.944 155.765 182.184 ;
     RECT  155.765 178.944 155.801 181.272 ;
     RECT  155.329 157.344 155.845 157.368 ;
     RECT  155.845 156.672 155.932 157.368 ;
     RECT  155.401 211.872 155.941 211.896 ;
     RECT  155.932 157.344 155.977 157.368 ;
     RECT  155.833 199.584 155.981 199.608 ;
     RECT  153.929 159.648 155.989 159.672 ;
     RECT  154.739 155.136 156.017 155.16 ;
     RECT  155.977 157.344 156.017 157.896 ;
     RECT  155.989 158.976 156.035 159.672 ;
     RECT  155.081 161.952 156.053 162.168 ;
     RECT  156.017 157.872 156.061 157.896 ;
     RECT  156.035 158.976 156.076 159 ;
     RECT  156.193 218.928 156.229 218.952 ;
     RECT  155.081 217.152 156.265 217.176 ;
     RECT  156.229 218.832 156.265 218.952 ;
     RECT  155.545 163.536 156.373 163.56 ;
     RECT  156.265 217.152 156.377 218.952 ;
     RECT  155.621 166.704 156.445 167.4 ;
     RECT  156.121 197.328 156.445 197.352 ;
     RECT  156.193 199.824 156.517 199.992 ;
     RECT  156.013 182.592 156.521 182.616 ;
     RECT  156.445 166.704 156.553 167.496 ;
     RECT  155.585 192.864 156.553 193.752 ;
     RECT  156.517 199.824 156.553 200.04 ;
     RECT  155.693 171.504 156.557 171.528 ;
     RECT  156.445 197.184 156.589 197.352 ;
     RECT  156.373 163.248 156.593 163.56 ;
     RECT  156.553 166.704 156.593 168.12 ;
     RECT  155.797 169.68 156.593 169.704 ;
     RECT  156.377 218.016 156.625 218.952 ;
     RECT  156.553 160.464 156.661 160.536 ;
     RECT  156.373 175.968 156.661 175.992 ;
     RECT  156.589 197.136 156.661 197.352 ;
     RECT  156.661 197.136 156.697 198.312 ;
     RECT  156.697 197.04 156.773 198.312 ;
     RECT  155.545 206.16 156.773 206.904 ;
     RECT  156.625 218.016 156.773 219.096 ;
     RECT  156.121 191.808 156.805 191.832 ;
     RECT  156.553 192.864 156.809 194.424 ;
     RECT  156.773 197.04 156.877 197.352 ;
     RECT  156.593 163.248 156.881 163.272 ;
     RECT  156.593 167.472 156.881 168.12 ;
     RECT  156.773 206.16 156.881 206.616 ;
     RECT  153.904 208.512 156.901 208.536 ;
     RECT  156.661 160.464 156.917 160.584 ;
     RECT  156.661 175.968 156.917 176.712 ;
     RECT  155.581 184.464 156.917 184.488 ;
     RECT  156.877 196.944 156.917 197.352 ;
     RECT  156.773 219.072 156.949 219.096 ;
     RECT  156.661 220.128 156.949 220.152 ;
     RECT  156.805 191.328 156.953 191.832 ;
     RECT  156.553 199.824 156.985 200.808 ;
     RECT  156.86 210.144 157.008 210.168 ;
     RECT  156.917 196.944 157.061 197.208 ;
     RECT  156.193 204.864 157.093 204.888 ;
     RECT  156.809 192.864 157.169 194.28 ;
     RECT  157.061 197.04 157.205 197.208 ;
     RECT  156.985 199.248 157.205 200.808 ;
     RECT  156.901 208.512 157.205 209.16 ;
     RECT  157.205 208.608 157.241 209.16 ;
     RECT  157.129 216.336 157.345 216.36 ;
     RECT  156.917 160.56 157.421 160.584 ;
     RECT  153.965 177.696 157.429 177.72 ;
     RECT  157.205 200.784 157.457 200.808 ;
     RECT  157.429 177.696 157.475 178.296 ;
     RECT  157.169 192.864 157.561 193.752 ;
     RECT  155.801 179.328 157.601 181.272 ;
     RECT  157.201 182.352 157.601 182.472 ;
     RECT  157.345 216.336 157.633 216.456 ;
     RECT  155.941 211.824 157.669 211.896 ;
     RECT  157.601 179.328 157.709 180.024 ;
     RECT  157.633 216.336 157.709 216.6 ;
     RECT  156.949 219.072 157.765 220.152 ;
     RECT  157.129 221.664 157.765 221.688 ;
     RECT  157.765 218.88 157.811 220.488 ;
     RECT  157.765 221.664 157.811 222.12 ;
     RECT  156.157 164.64 157.849 164.664 ;
     RECT  157.597 201.072 157.849 201.096 ;
     RECT  157.811 222.096 157.853 222.12 ;
     RECT  155.555 195.504 157.861 195.528 ;
     RECT  157.453 202.848 157.885 202.872 ;
     RECT  157.093 204.048 157.885 204.888 ;
     RECT  156.917 175.968 157.889 175.992 ;
     RECT  157.861 195.504 157.907 195.624 ;
     RECT  155.153 186.144 157.921 188.616 ;
     RECT  155.153 189.6 157.921 189.624 ;
     RECT  156.881 168 157.925 168.12 ;
     RECT  157.885 202.848 157.925 204.888 ;
     RECT  157.669 211.296 157.925 211.896 ;
     RECT  157.925 211.872 157.955 211.896 ;
     RECT  157.601 182.352 157.961 182.376 ;
     RECT  157.925 202.848 157.961 203.208 ;
     RECT  156.953 191.328 157.964 191.352 ;
     RECT  157.964 190.896 158.005 191.352 ;
     RECT  157.561 192.672 158.005 193.752 ;
     RECT  157.921 186.144 158.173 189.624 ;
     RECT  157.909 214.656 158.209 214.68 ;
     RECT  158.029 184.704 158.317 184.728 ;
     RECT  158.173 185.808 158.317 189.624 ;
     RECT  158.245 173.424 158.389 173.448 ;
     RECT  158.101 170.976 158.425 171 ;
     RECT  158.317 172.32 158.425 172.344 ;
     RECT  157.709 216.432 158.629 216.6 ;
     RECT  158.389 173.424 158.713 173.544 ;
     RECT  157.205 199.248 158.785 199.272 ;
     RECT  158.005 190.896 158.821 193.752 ;
     RECT  158.425 170.976 158.857 172.344 ;
     RECT  158.785 199.248 158.857 199.416 ;
     RECT  158.209 214.656 158.869 214.92 ;
     RECT  156.881 206.16 158.893 206.184 ;
     RECT  158.425 207.552 158.893 207.576 ;
     RECT  157.849 164.352 159.008 164.664 ;
     RECT  157.957 167.712 159.008 167.736 ;
     RECT  158.857 170.736 159.008 172.344 ;
     RECT  158.713 173.424 159.008 173.784 ;
     RECT  157.993 174.768 159.008 174.792 ;
     RECT  158.425 176.256 159.008 176.28 ;
     RECT  157.475 178.272 159.008 178.296 ;
     RECT  157.709 179.328 159.008 179.352 ;
     RECT  157.601 181.248 159.008 181.272 ;
     RECT  158.317 184.704 159.008 189.624 ;
     RECT  158.821 190.896 159.008 194.328 ;
     RECT  157.907 195.6 159.008 195.624 ;
     RECT  158.857 198.048 159.008 199.416 ;
     RECT  157.849 201.072 159.008 201.816 ;
     RECT  157.961 203.184 159.008 203.208 ;
     RECT  157.925 204.864 159.008 204.888 ;
     RECT  158.893 206.16 159.008 207.576 ;
     RECT  157.241 208.608 159.008 208.632 ;
     RECT  158.869 214.464 159.008 215.256 ;
     RECT  158.629 216.432 159.008 217.416 ;
     RECT  157.811 218.88 159.008 218.904 ;
     RECT  157.811 220.464 159.008 220.488 ;
     RECT  159.008 2.148 159.112 369.372 ;
     RECT  159.112 2.418 159.304 369.102 ;
     RECT  159.304 169.344 159.329 170.568 ;
     RECT  159.304 173.184 159.443 173.832 ;
     RECT  159.304 182.352 159.443 182.904 ;
     RECT  159.304 192.624 159.443 193.224 ;
     RECT  159.304 198.144 159.473 201.192 ;
     RECT  159.304 205.2 159.491 207.528 ;
     RECT  159.473 198.144 159.509 198.168 ;
     RECT  159.304 177.216 159.539 178.296 ;
     RECT  159.491 205.2 159.545 207.336 ;
     RECT  159.443 173.184 159.581 173.208 ;
     RECT  159.473 199.152 159.587 201.192 ;
     RECT  159.539 177.36 159.617 178.296 ;
     RECT  159.304 185.328 159.683 190.92 ;
     RECT  159.683 185.328 159.761 189.624 ;
     RECT  159.587 199.152 159.779 200.76 ;
     RECT  159.304 202.224 159.869 202.488 ;
     RECT  159.304 218.304 159.875 218.328 ;
     RECT  159.869 202.224 159.977 202.392 ;
     RECT  159.443 182.352 160.157 182.376 ;
     RECT  159.545 206.16 160.163 207.144 ;
     RECT  159.304 168.096 160.193 168.12 ;
     RECT  159.779 200.016 160.193 200.76 ;
     RECT  159.304 209.52 160.229 210.456 ;
     RECT  160.229 209.52 160.265 210.36 ;
     RECT  159.329 169.344 160.307 169.8 ;
     RECT  159.617 177.408 160.307 178.296 ;
     RECT  159.304 195.552 160.316 195.624 ;
     RECT  160.307 178.272 160.373 178.296 ;
     RECT  160.265 209.52 160.373 209.544 ;
     RECT  159.304 215.472 160.403 215.496 ;
     RECT  160.307 169.344 160.409 169.368 ;
     RECT  160.163 206.16 160.585 206.28 ;
     RECT  160.193 200.016 160.589 200.664 ;
     RECT  160.316 194.928 160.621 195.624 ;
     RECT  159.304 179.328 160.652 179.352 ;
     RECT  160.652 178.848 160.739 179.352 ;
     RECT  160.477 198.672 160.805 198.696 ;
     RECT  160.621 194.544 160.841 195.624 ;
     RECT  160.441 181.056 160.844 181.08 ;
     RECT  159.977 202.368 160.877 202.392 ;
     RECT  160.585 206.064 160.877 206.28 ;
     RECT  160.844 180.576 160.931 181.08 ;
     RECT  159.683 190.896 160.945 190.92 ;
     RECT  159.304 203.616 160.985 203.64 ;
     RECT  160.877 206.256 161.021 206.28 ;
     RECT  161.017 182.4 161.084 182.424 ;
     RECT  160.931 181.056 161.093 181.08 ;
     RECT  159.761 185.904 161.117 189.624 ;
     RECT  161.084 182.4 161.129 182.76 ;
     RECT  160.945 190.896 161.161 191.016 ;
     RECT  160.739 179.328 161.18 179.352 ;
     RECT  161.161 190.896 161.197 191.544 ;
     RECT  159.443 192.624 161.197 192.984 ;
     RECT  161.117 185.808 161.201 189.624 ;
     RECT  161.18 179.328 161.267 179.832 ;
     RECT  161.197 190.896 161.317 192.984 ;
     RECT  161.129 182.736 161.381 182.76 ;
     RECT  160.589 200.64 161.381 200.664 ;
     RECT  160.885 197.664 161.489 197.688 ;
     RECT  161.317 190.8 161.525 192.984 ;
     RECT  160.841 195.024 161.557 195.624 ;
     RECT  161.525 191.232 161.603 192.984 ;
     RECT  161.201 185.808 161.629 188.376 ;
     RECT  161.557 195.024 161.644 195.72 ;
     RECT  161.557 198.48 161.705 198.504 ;
     RECT  159.304 214.464 161.747 214.488 ;
     RECT  161.629 185.328 162.029 188.376 ;
     RECT  161.593 204.624 162.173 204.648 ;
     RECT  161.644 195.024 162.209 195.048 ;
     RECT  161.603 191.232 162.281 191.688 ;
     RECT  162.313 194.4 162.461 194.424 ;
     RECT  161.66 209.328 162.461 209.352 ;
     RECT  162.421 207.168 162.605 207.192 ;
     RECT  162.029 185.808 163.361 188.376 ;
     RECT  161.201 189.6 163.601 189.624 ;
     RECT  162.281 191.232 163.609 191.256 ;
     RECT  161.267 179.328 164.408 179.352 ;
     RECT  163.361 186.192 164.408 186.36 ;
     RECT  163.361 187.44 164.408 188.376 ;
     RECT  163.601 189.6 164.408 189.816 ;
     RECT  163.609 191.232 164.408 191.544 ;
     RECT  161.603 192.96 164.408 192.984 ;
     RECT  164.408 2.148 164.512 369.372 ;
     RECT  164.512 2.418 164.704 369.102 ;
     RECT  164.704 192.96 165.305 192.984 ;
     RECT  164.704 186.192 166.277 186.216 ;
     RECT  166.921 186.336 166.981 186.36 ;
     RECT  164.704 187.44 166.981 188.376 ;
     RECT  166.981 186.336 167.027 188.376 ;
     RECT  164.704 179.328 169.808 179.352 ;
     RECT  167.027 186.912 169.808 188.376 ;
     RECT  164.704 189.6 169.808 189.624 ;
     RECT  169.808 2.148 169.912 369.372 ;
     RECT  169.912 2.418 170.104 369.102 ;
     RECT  170.104 179.328 175.208 179.352 ;
     RECT  170.104 186.912 175.208 188.376 ;
     RECT  170.104 189.6 175.208 189.624 ;
     RECT  175.208 2.148 175.312 369.372 ;
     RECT  175.312 2.418 175.504 369.102 ;
     RECT  175.504 179.328 180.608 179.352 ;
     RECT  175.504 186.912 180.608 188.376 ;
     RECT  175.504 189.6 180.608 189.624 ;
     RECT  180.608 2.148 180.712 369.372 ;
     RECT  180.712 2.418 180.904 369.102 ;
     RECT  180.904 179.328 186.008 179.352 ;
     RECT  180.904 186.912 186.008 188.376 ;
     RECT  180.904 189.6 186.008 189.624 ;
     RECT  186.008 2.148 186.112 369.372 ;
     RECT  186.112 2.418 186.304 369.102 ;
     RECT  186.304 179.328 191.408 179.352 ;
     RECT  186.304 186.912 191.408 188.376 ;
     RECT  186.304 189.6 191.408 189.624 ;
     RECT  191.408 2.148 191.512 369.372 ;
     RECT  191.512 2.418 191.704 369.102 ;
     RECT  191.704 179.328 196.808 179.352 ;
     RECT  191.704 186.912 196.808 188.376 ;
     RECT  191.704 189.6 196.808 189.624 ;
     RECT  196.808 2.148 196.912 369.372 ;
     RECT  196.912 2.418 197.104 369.102 ;
     RECT  197.104 179.328 202.208 179.352 ;
     RECT  197.104 186.912 202.208 188.376 ;
     RECT  197.104 189.6 202.208 189.624 ;
     RECT  202.208 2.148 202.312 369.372 ;
     RECT  202.312 2.418 202.504 369.102 ;
     RECT  202.504 179.328 207.608 179.352 ;
     RECT  202.504 186.912 207.608 188.376 ;
     RECT  202.504 189.6 207.608 189.624 ;
     RECT  207.608 2.148 207.712 369.372 ;
     RECT  207.712 2.418 207.904 369.102 ;
     RECT  207.904 179.328 213.008 179.352 ;
     RECT  207.904 186.912 213.008 188.376 ;
     RECT  207.904 189.6 213.008 189.624 ;
     RECT  213.008 2.148 213.112 369.372 ;
     RECT  213.112 2.418 213.304 369.102 ;
     RECT  213.304 179.328 218.408 179.352 ;
     RECT  213.304 186.912 218.408 188.376 ;
     RECT  213.304 189.6 218.408 189.624 ;
     RECT  218.408 2.148 218.512 369.372 ;
     RECT  218.512 2.418 218.704 369.102 ;
     RECT  218.704 179.328 223.808 179.352 ;
     RECT  218.704 186.912 223.808 188.376 ;
     RECT  218.704 189.6 223.808 189.624 ;
     RECT  223.808 2.148 223.912 369.372 ;
     RECT  223.912 2.418 224.104 369.102 ;
     RECT  224.104 179.328 229.208 179.352 ;
     RECT  224.104 186.912 229.208 188.376 ;
     RECT  224.104 189.6 229.208 189.624 ;
     RECT  229.208 2.148 229.312 369.372 ;
     RECT  229.312 2.418 229.504 369.102 ;
     RECT  229.504 179.328 234.608 179.352 ;
     RECT  229.504 186.912 234.608 188.376 ;
     RECT  229.504 189.6 234.608 189.624 ;
     RECT  234.608 2.148 234.712 369.372 ;
     RECT  234.712 2.418 234.904 369.102 ;
     RECT  234.904 179.328 240.008 179.352 ;
     RECT  234.904 186.912 240.008 188.376 ;
     RECT  234.904 189.6 240.008 189.624 ;
     RECT  240.008 2.148 240.112 369.372 ;
     RECT  240.112 2.418 240.304 369.102 ;
     RECT  240.304 179.328 242.233 179.352 ;
     RECT  242.233 179.328 242.273 179.448 ;
     RECT  240.304 186.912 242.845 188.376 ;
     RECT  242.845 186.48 244.397 188.376 ;
     RECT  244.397 186.48 245.365 186.936 ;
     RECT  244.397 188.352 245.365 188.376 ;
     RECT  242.273 179.424 245.408 179.448 ;
     RECT  245.365 186.48 245.408 188.376 ;
     RECT  240.304 189.6 245.408 189.624 ;
     RECT  245.408 2.148 245.512 369.372 ;
     RECT  245.512 2.418 245.704 369.102 ;
     RECT  245.704 179.424 245.837 179.448 ;
     RECT  245.704 185.808 246.805 188.52 ;
     RECT  246.805 185.808 246.841 188.712 ;
     RECT  245.704 162.768 248.364 163.464 ;
     RECT  246.841 185.808 248.364 188.808 ;
    LAYER M5 ;
     RECT  2.4 2.137 2.52 2.151 ;
     RECT  7.8 2.137 7.92 2.151 ;
     RECT  13.2 2.137 13.32 2.151 ;
     RECT  18.6 2.137 18.72 2.151 ;
     RECT  24 2.137 24.12 2.151 ;
     RECT  29.4 2.137 29.52 2.151 ;
     RECT  34.8 2.137 34.92 2.151 ;
     RECT  40.2 2.137 40.32 2.151 ;
     RECT  45.6 2.137 45.72 2.151 ;
     RECT  51 2.137 51.12 2.151 ;
     RECT  56.4 2.137 56.52 2.151 ;
     RECT  61.8 2.137 61.92 2.151 ;
     RECT  67.2 2.137 67.32 2.151 ;
     RECT  72.6 2.137 72.72 2.151 ;
     RECT  78 2.137 78.12 2.151 ;
     RECT  83.4 2.137 83.52 2.151 ;
     RECT  88.8 2.137 88.92 2.151 ;
     RECT  94.2 2.137 94.32 2.151 ;
     RECT  99.6 2.137 99.72 2.151 ;
     RECT  105 2.137 105.12 2.151 ;
     RECT  110.4 2.137 110.52 2.151 ;
     RECT  115.8 2.137 115.92 2.151 ;
     RECT  121.2 2.137 121.32 2.151 ;
     RECT  126.6 2.137 126.72 2.151 ;
     RECT  132 2.137 132.12 2.151 ;
     RECT  137.4 2.137 137.52 2.151 ;
     RECT  142.8 2.137 142.92 2.151 ;
     RECT  148.2 2.137 148.32 2.151 ;
     RECT  153.6 2.137 153.72 2.151 ;
     RECT  159 2.137 159.12 2.151 ;
     RECT  164.4 2.137 164.52 2.151 ;
     RECT  169.8 2.137 169.92 2.151 ;
     RECT  175.2 2.137 175.32 2.151 ;
     RECT  180.6 2.137 180.72 2.151 ;
     RECT  186 2.137 186.12 2.151 ;
     RECT  191.4 2.137 191.52 2.151 ;
     RECT  196.8 2.137 196.92 2.151 ;
     RECT  202.2 2.137 202.32 2.151 ;
     RECT  207.6 2.137 207.72 2.151 ;
     RECT  213 2.137 213.12 2.151 ;
     RECT  218.4 2.137 218.52 2.151 ;
     RECT  223.8 2.137 223.92 2.151 ;
     RECT  229.2 2.137 229.32 2.151 ;
     RECT  234.6 2.137 234.72 2.151 ;
     RECT  240 2.137 240.12 2.151 ;
     RECT  245.4 2.137 245.52 2.151 ;
     RECT  141.216 132.229 141.24 134.051 ;
     RECT  145.104 133.333 145.128 135.349 ;
     RECT  142.8 2.151 143.112 135.493 ;
     RECT  145.104 135.349 145.32 135.637 ;
     RECT  142.56 135.493 143.112 135.973 ;
     RECT  144.672 135.637 145.32 136.741 ;
     RECT  139.92 132.661 139.944 137.507 ;
     RECT  144.432 136.741 145.32 137.987 ;
     RECT  137.4 2.151 137.712 138.757 ;
     RECT  144.672 137.987 145.32 139.139 ;
     RECT  144.672 139.139 144.696 139.621 ;
     RECT  142.464 135.973 143.112 139.667 ;
     RECT  146.16 139.621 146.184 140.101 ;
     RECT  146.16 140.101 147.048 140.243 ;
     RECT  146.736 140.243 147.048 141.301 ;
     RECT  133.584 138.133 133.608 141.683 ;
     RECT  144.24 139.621 144.696 141.877 ;
     RECT  146.496 141.301 147.048 141.923 ;
     RECT  139.872 141.301 139.896 141.971 ;
     RECT  132 2.151 132.312 142.453 ;
     RECT  137.4 138.757 138.264 142.453 ;
     RECT  140.784 142.453 140.808 143.221 ;
     RECT  146.496 141.923 146.76 143.221 ;
     RECT  140.784 143.221 141.144 143.267 ;
     RECT  141.12 143.267 141.144 143.747 ;
     RECT  131.904 142.453 132.312 143.893 ;
     RECT  144.24 141.877 144.888 144.563 ;
     RECT  136.272 138.469 136.296 144.997 ;
     RECT  137.4 142.453 138.792 144.997 ;
     RECT  136.272 144.997 138.792 145.043 ;
     RECT  140.736 144.757 140.76 145.237 ;
     RECT  131.184 143.893 132.312 145.379 ;
     RECT  146.448 143.221 146.76 145.381 ;
     RECT  150 144.229 150.024 145.571 ;
     RECT  140.736 145.237 141.144 145.619 ;
     RECT  136.608 145.043 138.792 146.437 ;
     RECT  136.608 146.437 139.272 146.773 ;
     RECT  141.12 145.619 141.144 147.251 ;
     RECT  142.56 139.667 143.112 147.541 ;
     RECT  144.672 144.563 144.888 147.541 ;
     RECT  136.176 146.773 139.272 147.683 ;
     RECT  130.848 145.909 130.872 147.731 ;
     RECT  146.064 145.381 146.76 148.163 ;
     RECT  132 145.379 132.312 148.165 ;
     RECT  133.536 145.669 133.56 148.259 ;
     RECT  150.912 147.589 150.936 148.691 ;
     RECT  146.688 148.163 146.76 148.741 ;
     RECT  148.2 2.151 148.512 148.741 ;
     RECT  136.608 147.683 139.272 149.219 ;
     RECT  132 148.165 132.408 149.411 ;
     RECT  152.016 143.845 152.04 149.461 ;
     RECT  153.6 2.151 153.912 149.461 ;
     RECT  152.016 149.461 153.912 149.507 ;
     RECT  136.608 149.219 139.224 149.749 ;
     RECT  142.56 147.541 144.888 149.845 ;
     RECT  129.024 148.981 129.048 149.893 ;
     RECT  146.688 148.741 148.512 149.939 ;
     RECT  146.736 149.939 148.512 149.941 ;
     RECT  146.736 149.941 148.632 149.987 ;
     RECT  135.696 149.749 139.224 150.515 ;
     RECT  132 149.411 132.312 150.853 ;
     RECT  150.912 150.277 150.936 150.853 ;
     RECT  150.912 150.853 151.032 150.899 ;
     RECT  146.736 149.987 147.048 150.901 ;
     RECT  136.608 150.515 139.224 150.947 ;
     RECT  128.4 149.893 129.048 150.997 ;
     RECT  148.2 149.987 148.632 151.043 ;
     RECT  141.792 149.845 144.888 151.091 ;
     RECT  134.592 148.213 134.616 151.235 ;
     RECT  151.008 150.899 151.032 151.427 ;
     RECT  146.304 150.901 147.048 152.195 ;
     RECT  128.4 150.997 129.912 152.483 ;
     RECT  142.56 151.091 144.888 152.629 ;
     RECT  136.608 150.947 138.792 152.867 ;
     RECT  131.856 150.853 132.312 153.013 ;
     RECT  152.736 149.507 153.912 153.155 ;
     RECT  148.2 151.043 148.512 153.253 ;
     RECT  129.024 152.483 129.912 153.443 ;
     RECT  134.496 153.301 134.52 153.493 ;
     RECT  126.6 2.151 126.912 153.541 ;
     RECT  141.936 152.629 144.888 153.733 ;
     RECT  147.408 153.253 148.512 153.781 ;
     RECT  150.96 151.909 150.984 154.067 ;
     RECT  129.36 153.443 129.912 154.211 ;
     RECT  153.6 153.155 153.912 154.213 ;
     RECT  131.808 153.013 132.312 154.307 ;
     RECT  134.352 153.493 134.52 154.307 ;
     RECT  134.448 154.307 134.52 154.403 ;
     RECT  137.184 152.867 138.792 154.453 ;
     RECT  134.448 154.403 134.472 154.499 ;
     RECT  147.408 153.781 149.352 154.595 ;
     RECT  141.792 153.733 144.888 154.645 ;
     RECT  126.6 153.541 127.224 154.691 ;
     RECT  137.184 154.453 139.752 154.835 ;
     RECT  137.4 154.835 139.752 155.269 ;
     RECT  140.88 154.645 144.888 155.269 ;
     RECT  129.36 154.211 129.624 155.315 ;
     RECT  137.4 155.269 144.888 155.315 ;
     RECT  131.856 154.307 132.312 155.557 ;
     RECT  126.6 154.691 127.128 155.651 ;
     RECT  153.6 154.213 154.728 155.651 ;
     RECT  140.208 155.315 144.888 155.747 ;
     RECT  129.36 155.315 129.384 156.085 ;
     RECT  128.88 156.085 129.384 156.131 ;
     RECT  128.88 156.131 128.904 156.133 ;
     RECT  131.856 155.557 132.936 156.133 ;
     RECT  151.152 154.501 151.176 156.133 ;
     RECT  131.856 156.133 133.416 156.179 ;
     RECT  150.528 156.133 151.176 156.179 ;
     RECT  146.304 152.195 146.328 156.709 ;
     RECT  147.408 154.595 148.512 156.709 ;
     RECT  126.6 155.651 126.912 156.853 ;
     RECT  128.256 156.133 128.904 156.853 ;
     RECT  125.424 151.573 125.448 156.901 ;
     RECT  126.6 156.853 128.904 156.901 ;
     RECT  125.424 156.901 128.904 156.947 ;
     RECT  155.856 155.125 155.88 157.379 ;
     RECT  125.664 156.947 128.904 157.475 ;
     RECT  146.304 156.709 148.512 157.667 ;
     RECT  128.88 157.475 128.904 158.005 ;
     RECT  129.936 157.285 129.96 158.005 ;
     RECT  128.88 158.005 129.96 158.051 ;
     RECT  140.88 155.747 144.888 158.053 ;
     RECT  128.88 158.051 129.432 158.531 ;
     RECT  131.904 156.179 133.416 158.531 ;
     RECT  150.528 156.179 150.552 158.531 ;
     RECT  121.2 2.151 121.512 158.917 ;
     RECT  125.664 157.475 127.464 159.059 ;
     RECT  131.904 158.531 132.936 159.059 ;
     RECT  140.64 158.053 144.888 159.491 ;
     RECT  125.664 159.059 126.912 159.635 ;
     RECT  134.544 159.013 134.568 159.635 ;
     RECT  156 157.861 156.024 159.683 ;
     RECT  121.104 158.917 121.512 159.779 ;
     RECT  146.304 157.667 146.328 160.549 ;
     RECT  147.408 157.667 148.512 160.549 ;
     RECT  122.544 159.541 122.568 160.595 ;
     RECT  128.88 158.531 128.904 160.645 ;
     RECT  128.88 160.645 129.096 160.691 ;
     RECT  149.856 160.069 149.88 160.691 ;
     RECT  126.6 159.635 126.912 160.693 ;
     RECT  129.072 160.691 129.096 160.693 ;
     RECT  152.256 157.285 152.28 161.075 ;
     RECT  146.304 160.549 148.512 161.317 ;
     RECT  129.072 160.693 130.008 161.795 ;
     RECT  132 159.059 132.936 161.845 ;
     RECT  137.4 155.315 139.128 161.845 ;
     RECT  131.328 161.845 132.936 161.893 ;
     RECT  137.4 161.845 139.752 162.421 ;
     RECT  140.88 159.491 144.888 162.421 ;
     RECT  146.208 161.317 148.512 162.421 ;
     RECT  117.936 161.317 117.96 162.515 ;
     RECT  146.208 162.421 149.208 162.515 ;
     RECT  120.048 161.845 120.072 162.757 ;
     RECT  115.8 2.151 116.112 162.997 ;
     RECT  131.328 161.893 133.224 162.997 ;
     RECT  125.76 160.693 126.912 163.139 ;
     RECT  123.792 163.093 123.816 163.525 ;
     RECT  137.4 162.421 144.888 163.525 ;
     RECT  146.208 162.515 146.424 163.525 ;
     RECT  137.4 163.525 146.424 163.715 ;
     RECT  135.984 156.037 136.008 163.765 ;
     RECT  129.072 161.795 129.096 164.435 ;
     RECT  147.408 162.515 149.208 164.531 ;
     RECT  123.12 163.525 123.816 164.771 ;
     RECT  135.36 163.765 136.008 164.819 ;
     RECT  140.88 163.715 146.424 164.819 ;
     RECT  153.6 155.651 153.912 165.061 ;
     RECT  123.12 164.771 123.144 165.347 ;
     RECT  115.8 162.997 116.28 165.923 ;
     RECT  119.376 162.757 120.072 165.923 ;
     RECT  150.432 164.485 150.456 165.971 ;
     RECT  140.88 164.819 144.888 166.069 ;
     RECT  131.328 162.997 133.704 166.115 ;
     RECT  140.88 166.069 144.936 166.115 ;
     RECT  131.568 166.115 133.704 166.117 ;
     RECT  121.2 159.779 121.512 166.405 ;
     RECT  152.016 161.077 152.04 166.981 ;
     RECT  153.312 165.061 153.912 166.981 ;
     RECT  147.408 164.531 148.968 167.173 ;
     RECT  144.192 166.115 144.936 167.509 ;
     RECT  146.208 164.819 146.424 167.509 ;
     RECT  123.696 165.829 123.72 167.555 ;
     RECT  126.6 163.139 126.912 167.557 ;
     RECT  128.16 165.445 128.184 167.557 ;
     RECT  144.192 167.509 146.424 167.557 ;
     RECT  147.408 167.173 149.208 167.557 ;
     RECT  121.104 166.405 121.512 167.603 ;
     RECT  126.6 167.557 128.184 167.603 ;
     RECT  131.568 166.117 134.376 167.603 ;
     RECT  152.016 166.981 153.912 167.603 ;
     RECT  137.4 163.715 139.752 167.989 ;
     RECT  140.88 166.115 143.112 167.989 ;
     RECT  119.376 165.923 119.4 168.229 ;
     RECT  119.376 168.229 119.64 168.275 ;
     RECT  150.48 167.557 150.504 168.275 ;
     RECT  137.4 167.989 143.112 168.277 ;
     RECT  153.312 167.603 153.912 168.323 ;
     RECT  152.016 167.603 152.04 168.661 ;
     RECT  131.616 167.603 134.376 168.803 ;
     RECT  132 168.803 134.376 168.805 ;
     RECT  126.6 167.603 127.752 169.187 ;
     RECT  115.8 165.923 116.112 169.237 ;
     RECT  119.616 168.275 119.64 169.237 ;
     RECT  121.2 167.603 121.512 169.237 ;
     RECT  132 168.805 134.472 169.669 ;
     RECT  159 2.151 159.312 169.765 ;
     RECT  132 169.669 135 170.005 ;
     RECT  135.984 164.819 136.008 170.005 ;
     RECT  119.616 169.237 121.512 170.147 ;
     RECT  137.4 168.277 143.208 170.149 ;
     RECT  144.192 167.557 149.208 170.149 ;
     RECT  121.2 170.147 121.512 170.293 ;
     RECT  122.496 169.813 122.52 170.293 ;
     RECT  121.2 170.293 122.52 170.339 ;
     RECT  151.056 168.661 152.04 170.435 ;
     RECT  117.984 169.525 118.008 170.483 ;
     RECT  137.4 170.149 149.208 170.579 ;
     RECT  126.6 169.187 127.656 171.443 ;
     RECT  132 170.005 136.008 171.541 ;
     RECT  132 171.541 136.296 171.589 ;
     RECT  151.056 170.435 151.896 171.781 ;
     RECT  115.8 169.237 116.856 171.923 ;
     RECT  119.616 170.147 119.64 172.549 ;
     RECT  123.84 169.285 123.864 172.549 ;
     RECT  119.376 172.549 119.64 172.595 ;
     RECT  123.648 172.549 123.864 172.595 ;
     RECT  126.6 171.443 127.128 172.645 ;
     RECT  150.528 171.781 151.896 172.739 ;
     RECT  128.88 170.293 128.904 172.883 ;
     RECT  131.904 171.589 136.296 172.931 ;
     RECT  137.4 170.579 148.968 173.173 ;
     RECT  121.2 170.339 122.232 173.411 ;
     RECT  132 172.931 136.296 173.701 ;
     RECT  137.28 173.173 148.968 173.701 ;
     RECT  123.648 172.595 123.672 173.939 ;
     RECT  151.872 172.739 151.896 173.939 ;
     RECT  126.6 172.645 127.656 174.179 ;
     RECT  132 173.701 148.968 174.229 ;
     RECT  132 174.229 149.352 174.325 ;
     RECT  130.176 173.701 130.2 174.467 ;
     RECT  122.496 174.421 122.52 174.755 ;
     RECT  126.6 174.179 127.224 174.949 ;
     RECT  117.984 173.557 118.008 174.995 ;
     RECT  155.328 174.421 155.352 174.995 ;
     RECT  132 174.325 149.4 175.187 ;
     RECT  0.144 175.093 0.168 175.379 ;
     RECT  137.28 175.187 149.4 175.571 ;
     RECT  118.032 175.429 118.392 175.859 ;
     RECT  115.8 171.923 116.112 175.957 ;
     RECT  119.376 172.595 119.4 176.053 ;
     RECT  152.352 175.813 152.376 176.101 ;
     RECT  119.376 176.053 119.688 176.147 ;
     RECT  126.48 174.949 127.224 176.147 ;
     RECT  150.528 172.739 150.552 176.149 ;
     RECT  132 175.187 136.104 176.485 ;
     RECT  137.28 175.571 149.352 176.485 ;
     RECT  118.032 175.859 118.056 176.627 ;
     RECT  119.664 176.147 119.688 176.629 ;
     RECT  119.664 176.629 120.216 177.203 ;
     RECT  124.608 176.101 124.632 177.205 ;
     RECT  159 169.765 160.296 177.443 ;
     RECT  126.48 176.147 126.912 177.445 ;
     RECT  129.36 176.677 129.384 177.875 ;
     RECT  126.48 177.445 127.656 178.019 ;
     RECT  151.584 176.101 152.376 178.019 ;
     RECT  153.6 168.323 153.912 178.261 ;
     RECT  120.192 177.203 120.216 178.549 ;
     RECT  121.2 173.411 121.512 178.549 ;
     RECT  120.192 178.549 121.512 178.595 ;
     RECT  124.608 177.205 125.112 178.645 ;
     RECT  124.56 178.645 125.112 178.691 ;
     RECT  115.8 175.957 116.904 179.315 ;
     RECT  126.6 178.019 127.656 179.411 ;
     RECT  160.704 178.837 160.728 179.797 ;
     RECT  126.6 179.411 127.608 180.179 ;
     RECT  152.64 178.261 153.912 180.563 ;
     RECT  121.104 178.595 121.512 180.565 ;
     RECT  121.104 180.565 122.28 180.947 ;
     RECT  124.56 178.691 124.632 181.093 ;
     RECT  121.2 180.947 122.28 181.283 ;
     RECT  152.736 180.563 153.912 181.283 ;
     RECT  157.44 177.685 157.464 181.283 ;
     RECT  153.6 181.283 153.912 181.765 ;
     RECT  124.464 181.093 124.632 182.051 ;
     RECT  132 176.485 149.352 182.101 ;
     RECT  131.808 182.101 149.352 182.341 ;
     RECT  151.584 178.019 151.608 182.389 ;
     RECT  124.608 182.051 124.632 182.435 ;
     RECT  159 177.443 159.312 182.581 ;
     RECT  153.6 181.765 154.008 182.627 ;
     RECT  119.136 180.421 119.16 182.963 ;
     RECT  130.272 178.789 130.296 183.109 ;
     RECT  131.712 182.341 149.352 183.109 ;
     RECT  115.8 179.315 116.28 183.155 ;
     RECT  151.584 182.389 152.52 183.155 ;
     RECT  128.16 181.141 128.184 184.211 ;
     RECT  121.2 181.283 121.512 184.213 ;
     RECT  150.432 176.149 150.552 184.309 ;
     RECT  151.584 183.155 151.608 184.309 ;
     RECT  115.8 183.155 116.112 184.645 ;
     RECT  130.272 183.109 149.352 184.645 ;
     RECT  153.6 182.627 153.912 184.693 ;
     RECT  120.672 184.213 121.512 184.739 ;
     RECT  154.944 184.741 154.968 185.027 ;
     RECT  150.432 184.309 151.608 185.411 ;
     RECT  152.784 184.693 153.912 185.555 ;
     RECT  151.584 185.411 151.608 185.797 ;
     RECT  130.272 184.645 149.4 185.845 ;
     RECT  130.224 185.845 149.4 185.941 ;
     RECT  126.6 180.179 126.912 186.181 ;
     RECT  164.4 2.151 164.712 186.181 ;
     RECT  160.704 179.797 161.256 186.277 ;
     RECT  117.984 184.645 118.008 186.371 ;
     RECT  164.304 186.181 164.712 186.371 ;
     RECT  159 182.581 159.432 186.419 ;
     RECT  128.88 186.373 128.904 186.469 ;
     RECT  129.888 185.941 149.4 186.469 ;
     RECT  160.704 186.277 162.168 186.611 ;
     RECT  166.992 186.325 167.016 186.947 ;
     RECT  123.984 185.797 124.008 186.995 ;
     RECT  126.48 186.181 126.912 186.995 ;
     RECT  151.584 185.797 152.088 187.331 ;
     RECT  159 186.419 159.312 187.477 ;
     RECT  115.8 184.645 116.232 187.571 ;
     RECT  160.896 186.611 162.168 187.619 ;
     RECT  153.6 185.555 153.912 187.621 ;
     RECT  152.784 187.621 153.912 187.859 ;
     RECT  159 187.477 159.624 188.629 ;
     RECT  121.2 184.739 121.512 188.965 ;
     RECT  159 188.629 159.672 188.965 ;
     RECT  160.896 187.619 161.256 188.965 ;
     RECT  128.88 186.469 149.4 189.349 ;
     RECT  150.432 185.411 150.552 189.349 ;
     RECT  126.6 186.995 126.912 189.733 ;
     RECT  151.584 187.331 151.608 189.781 ;
     RECT  164.4 186.371 164.712 189.781 ;
     RECT  128.88 189.349 150.552 189.875 ;
     RECT  119.568 188.389 119.592 190.405 ;
     RECT  121.2 188.965 121.608 190.405 ;
     RECT  125.616 189.733 126.912 190.405 ;
     RECT  117.936 189.205 117.96 190.451 ;
     RECT  119.568 190.405 121.608 190.451 ;
     RECT  151.584 189.781 152.232 190.451 ;
     RECT  159 188.965 161.256 190.789 ;
     RECT  128.88 189.875 150.456 190.885 ;
     RECT  151.584 190.451 151.608 190.885 ;
     RECT  159 190.789 161.352 190.885 ;
     RECT  120.528 190.451 121.608 190.979 ;
     RECT  125.616 190.405 127.128 190.979 ;
     RECT  128.88 190.885 151.608 191.507 ;
     RECT  163.632 189.781 164.712 191.555 ;
     RECT  125.712 190.979 127.128 191.795 ;
     RECT  158.016 190.885 161.352 191.939 ;
     RECT  153.6 187.859 153.912 192.613 ;
     RECT  158.88 191.939 161.352 192.613 ;
     RECT  125.712 191.795 126.912 192.707 ;
     RECT  158.88 192.613 161.592 193.235 ;
     RECT  128.88 191.507 149.4 193.477 ;
     RECT  150.432 191.507 151.608 193.477 ;
     RECT  124.656 193.189 124.68 193.525 ;
     RECT  128.88 193.477 151.608 193.525 ;
     RECT  115.8 187.571 116.112 193.621 ;
     RECT  117.504 191.365 117.528 193.621 ;
     RECT  120.528 190.979 121.512 193.907 ;
     RECT  128.88 193.525 152.232 194.197 ;
     RECT  115.8 193.621 117.528 194.435 ;
     RECT  127.968 194.197 152.232 194.435 ;
     RECT  118.8 193.573 118.824 194.579 ;
     RECT  127.968 194.435 150.648 194.723 ;
     RECT  124.416 193.525 124.68 194.821 ;
     RECT  124.416 194.821 124.824 194.867 ;
     RECT  114.096 189.781 114.12 194.963 ;
     RECT  127.968 194.723 130.344 194.963 ;
     RECT  155.52 192.613 155.544 195.299 ;
     RECT  153.6 192.613 154.152 195.493 ;
     RECT  157.584 193.525 157.608 195.493 ;
     RECT  157.584 195.493 157.896 195.539 ;
     RECT  127.968 194.963 128.088 195.635 ;
     RECT  157.872 195.539 157.896 195.635 ;
     RECT  124.8 194.867 124.824 196.115 ;
     RECT  129.792 194.963 130.344 196.115 ;
     RECT  117.504 194.435 117.528 196.691 ;
     RECT  129.792 196.115 130.296 197.267 ;
     RECT  130.224 197.267 130.296 197.699 ;
     RECT  159 193.235 161.592 197.699 ;
     RECT  115.8 194.435 116.112 198.277 ;
     RECT  126.6 192.707 126.912 198.325 ;
     RECT  128.064 195.635 128.088 198.325 ;
     RECT  152.496 197.173 152.52 198.325 ;
     RECT  119.472 198.325 119.496 198.515 ;
     RECT  161.568 197.699 161.592 198.515 ;
     RECT  131.856 194.723 150.648 198.659 ;
     RECT  115.488 198.277 116.112 198.901 ;
     RECT  124.848 197.221 124.872 198.995 ;
     RECT  130.272 197.699 130.296 199.429 ;
     RECT  130.272 199.429 130.536 199.523 ;
     RECT  152.496 198.325 152.568 199.523 ;
     RECT  123.36 196.597 123.384 199.573 ;
     RECT  115.44 198.901 117 199.619 ;
     RECT  123.36 199.573 123.624 199.619 ;
     RECT  152.544 199.523 152.568 200.003 ;
     RECT  131.856 198.659 150.552 200.099 ;
     RECT  121.2 193.907 121.512 200.581 ;
     RECT  119.664 199.093 119.688 200.627 ;
     RECT  131.856 200.099 150.456 200.675 ;
     RECT  130.512 199.523 130.536 200.773 ;
     RECT  130.272 200.773 130.536 200.819 ;
     RECT  126.6 198.325 128.088 201.251 ;
     RECT  126.6 201.251 127.032 201.347 ;
     RECT  130.272 200.819 130.296 201.587 ;
     RECT  115.44 199.619 116.112 201.779 ;
     RECT  115.8 201.779 116.112 201.781 ;
     RECT  120.816 200.581 121.512 201.827 ;
     RECT  152.16 201.157 152.184 202.307 ;
     RECT  128.064 201.251 128.088 202.309 ;
     RECT  128.016 202.309 128.088 202.357 ;
     RECT  126.6 201.347 126.912 202.597 ;
     RECT  128.016 202.357 128.232 202.643 ;
     RECT  123.6 199.619 123.624 202.739 ;
     RECT  121.2 201.827 121.512 202.837 ;
     RECT  153.6 195.493 154.248 202.837 ;
     RECT  153.6 202.837 155.016 202.883 ;
     RECT  115.8 201.781 117 202.979 ;
     RECT  128.016 202.643 128.04 203.219 ;
     RECT  131.856 200.675 149.88 204.227 ;
     RECT  117.936 203.173 117.96 204.659 ;
     RECT  121.104 202.837 121.512 204.755 ;
     RECT  131.904 204.227 149.88 205.283 ;
     RECT  130.032 204.325 130.056 205.811 ;
     RECT  131.904 205.283 141.192 205.859 ;
     RECT  142.224 205.283 149.88 205.859 ;
     RECT  128.208 204.901 128.232 205.907 ;
     RECT  153.6 202.883 153.912 205.957 ;
     RECT  153.6 205.957 154.008 206.147 ;
     RECT  123.12 203.413 123.144 206.293 ;
     RECT  122.496 206.293 123.144 206.339 ;
     RECT  136.128 205.859 141.192 207.107 ;
     RECT  117.36 206.725 117.384 207.253 ;
     RECT  117.36 207.253 117.96 207.299 ;
     RECT  121.2 204.755 121.512 207.445 ;
     RECT  122.496 206.339 122.52 207.539 ;
     RECT  125.808 202.597 126.912 208.021 ;
     RECT  131.904 205.859 135.144 208.021 ;
     RECT  136.128 207.107 137.712 208.021 ;
     RECT  117.936 207.299 117.96 208.115 ;
     RECT  138.864 207.107 141.192 208.115 ;
     RECT  153.6 206.147 153.912 208.501 ;
     RECT  154.992 202.883 155.016 208.547 ;
     RECT  124.272 208.021 124.296 208.597 ;
     RECT  144.288 205.859 149.88 208.597 ;
     RECT  124.176 208.597 124.296 208.643 ;
     RECT  125.808 208.021 127.176 208.835 ;
     RECT  144.24 208.597 149.88 208.883 ;
     RECT  144.24 208.883 146.184 208.931 ;
     RECT  120.576 207.445 121.512 209.219 ;
     RECT  131.904 208.021 137.712 209.219 ;
     RECT  142.224 205.859 143.112 209.219 ;
     RECT  145.44 208.931 146.184 209.219 ;
     RECT  147.552 208.883 149.88 209.267 ;
     RECT  138.912 208.115 141.192 209.363 ;
     RECT  121.2 209.219 121.512 209.413 ;
     RECT  125.808 208.835 126.912 209.795 ;
     RECT  121.2 209.413 122.04 210.035 ;
     RECT  156.912 209.125 156.936 210.179 ;
     RECT  131.904 209.219 132.312 210.277 ;
     RECT  144.24 208.931 144.408 210.277 ;
     RECT  145.488 209.219 146.184 210.277 ;
     RECT  133.68 209.219 137.712 210.371 ;
     RECT  133.68 210.371 134.904 210.563 ;
     RECT  139.056 209.363 141.192 210.611 ;
     RECT  142.464 209.219 143.112 210.661 ;
     RECT  144.24 210.277 146.184 210.661 ;
     RECT  126.6 209.795 126.912 210.805 ;
     RECT  135.888 210.371 137.712 210.899 ;
     RECT  142.464 210.661 146.184 210.899 ;
     RECT  129.216 210.229 129.24 210.947 ;
     RECT  133.68 210.563 133.8 210.947 ;
     RECT  139.632 210.611 141.192 210.947 ;
     RECT  133.776 210.947 133.8 210.995 ;
     RECT  142.464 210.899 144.264 211.043 ;
     RECT  136.272 210.899 137.712 211.189 ;
     RECT  134.88 210.563 134.904 211.235 ;
     RECT  136.272 211.189 138.6 211.331 ;
     RECT  131.904 210.277 132.696 211.379 ;
     RECT  148.2 209.267 149.88 211.429 ;
     RECT  142.464 211.043 143.592 212.003 ;
     RECT  136.272 211.331 137.712 212.005 ;
     RECT  129.168 211.333 129.192 212.051 ;
     RECT  139.728 210.947 141.192 212.099 ;
     RECT  148.2 211.429 150.552 212.245 ;
     RECT  142.8 212.003 143.592 212.387 ;
     RECT  147.456 212.245 150.552 212.531 ;
     RECT  148.2 212.531 149.256 212.627 ;
     RECT  153.216 208.501 153.912 212.629 ;
     RECT  136.08 212.005 137.712 212.675 ;
     RECT  136.08 212.675 136.296 212.819 ;
     RECT  126 210.805 126.912 212.965 ;
     RECT  125.424 212.965 126.912 213.011 ;
     RECT  145.296 210.899 146.184 213.061 ;
     RECT  128.16 212.005 128.184 213.203 ;
     RECT  150.528 212.531 150.552 213.203 ;
     RECT  139.728 212.099 139.752 213.541 ;
     RECT  153.216 212.629 154.488 213.635 ;
     RECT  142.8 212.387 143.112 213.685 ;
     RECT  131.904 211.379 132.408 213.779 ;
     RECT  148.2 212.627 148.632 213.779 ;
     RECT  153.216 213.635 153.912 213.779 ;
     RECT  141.168 212.099 141.192 213.973 ;
     RECT  145.296 213.061 146.472 214.019 ;
     RECT  142.608 213.685 143.112 214.021 ;
     RECT  140.784 213.973 141.192 214.115 ;
     RECT  140.88 214.115 141.192 214.211 ;
     RECT  126.6 213.011 126.912 214.213 ;
     RECT  131.904 213.779 132.312 214.213 ;
     RECT  124.176 208.643 124.2 214.355 ;
     RECT  131.808 214.213 132.312 214.355 ;
     RECT  157.92 211.861 157.944 214.453 ;
     RECT  159 197.699 160.392 214.453 ;
     RECT  138.816 213.541 139.752 214.499 ;
     RECT  161.712 209.317 161.736 214.499 ;
     RECT  126.6 214.213 127.656 214.643 ;
     RECT  145.968 214.019 146.472 214.691 ;
     RECT  157.92 214.453 160.392 214.691 ;
     RECT  125.424 213.011 125.448 214.931 ;
     RECT  158.88 214.691 160.392 215.267 ;
     RECT  148.2 213.779 148.512 215.269 ;
     RECT  159 215.267 160.392 215.507 ;
     RECT  133.392 214.789 133.416 216.083 ;
     RECT  145.968 214.691 146.424 216.083 ;
     RECT  148.2 215.269 149.4 216.083 ;
     RECT  139.92 215.077 139.944 216.179 ;
     RECT  131.904 214.355 132.312 216.373 ;
     RECT  159 215.507 159.864 216.421 ;
     RECT  130.176 213.637 130.2 216.949 ;
     RECT  138.816 214.499 138.84 217.141 ;
     RECT  125.424 215.893 125.448 217.235 ;
     RECT  133.92 216.565 133.944 217.669 ;
     RECT  148.2 216.083 148.512 217.669 ;
     RECT  133.92 217.669 134.712 217.715 ;
     RECT  126.6 214.643 127.464 217.717 ;
     RECT  148.2 217.669 148.632 217.717 ;
     RECT  142.512 214.021 143.112 217.811 ;
     RECT  130.176 216.949 130.872 217.955 ;
     RECT  138.816 217.141 139.608 218.245 ;
     RECT  145.968 216.083 145.992 218.293 ;
     RECT  126.6 217.717 128.376 218.339 ;
     RECT  158.64 216.421 159.864 218.339 ;
     RECT  128.352 218.339 128.376 218.435 ;
     RECT  134.688 217.715 134.712 218.435 ;
     RECT  145.968 218.293 146.52 218.723 ;
     RECT  158.64 218.339 159.312 218.869 ;
     RECT  157.776 218.869 159.312 218.915 ;
     RECT  144.96 217.285 144.984 219.011 ;
     RECT  125.376 218.053 125.4 219.059 ;
     RECT  130.176 217.955 130.584 219.059 ;
     RECT  138.816 218.245 139.656 219.059 ;
     RECT  142.56 217.811 143.112 219.061 ;
     RECT  151.248 217.813 151.272 219.731 ;
     RECT  137.4 212.675 137.712 219.973 ;
     RECT  147.648 217.717 148.632 219.973 ;
     RECT  131.904 216.373 132.936 220.115 ;
     RECT  130.176 219.059 130.2 220.163 ;
     RECT  136.272 212.819 136.296 220.357 ;
     RECT  138.816 219.059 139.608 220.499 ;
     RECT  147.648 219.973 149.112 220.547 ;
     RECT  141.168 214.211 141.192 220.549 ;
     RECT  142.512 219.061 143.112 220.549 ;
     RECT  137.28 219.973 137.712 221.027 ;
     RECT  128.88 220.549 128.904 221.267 ;
     RECT  136.176 220.357 136.296 221.701 ;
     RECT  126.6 218.339 127.128 221.795 ;
     RECT  147.744 220.547 149.112 221.843 ;
     RECT  157.776 218.915 157.8 222.131 ;
     RECT  145.968 218.723 145.992 222.277 ;
     RECT  128.832 221.605 128.856 222.323 ;
     RECT  130.56 220.165 130.584 222.323 ;
     RECT  147.744 221.843 148.632 222.323 ;
     RECT  144.576 219.973 144.6 222.611 ;
     RECT  126.6 221.795 126.912 222.805 ;
     RECT  138.816 220.499 138.84 222.805 ;
     RECT  153.6 213.779 153.912 222.805 ;
     RECT  141.168 220.549 143.112 223.283 ;
     RECT  145.824 222.277 145.992 223.427 ;
     RECT  131.904 220.115 132.696 223.765 ;
     RECT  145.968 223.427 145.992 223.861 ;
     RECT  126.6 222.805 127.704 224.051 ;
     RECT  131.904 223.765 132.84 224.051 ;
     RECT  145.968 223.861 146.76 224.051 ;
     RECT  138.816 222.805 139.656 224.243 ;
     RECT  137.4 221.027 137.712 224.485 ;
     RECT  136.08 221.701 136.296 224.531 ;
     RECT  149.76 223.381 149.784 224.819 ;
     RECT  132 224.051 132.84 224.821 ;
     RECT  153.6 222.805 154.344 225.155 ;
     RECT  130.512 223.957 130.536 225.347 ;
     RECT  141.168 223.283 141.192 225.397 ;
     RECT  142.608 223.283 143.112 225.443 ;
     RECT  146.736 224.051 146.76 225.539 ;
     RECT  132 224.821 133.368 225.827 ;
     RECT  137.4 224.485 137.832 225.827 ;
     RECT  148.2 222.323 148.632 225.877 ;
     RECT  138.816 224.243 138.84 226.355 ;
     RECT  135.264 224.821 135.288 226.405 ;
     RECT  134.544 226.405 135.288 226.499 ;
     RECT  142.8 225.443 143.112 226.597 ;
     RECT  134.544 226.499 134.664 226.643 ;
     RECT  142.8 226.597 144.024 227.413 ;
     RECT  134.64 226.643 134.664 227.459 ;
     RECT  148.2 225.877 148.824 227.507 ;
     RECT  142.704 227.413 144.024 227.509 ;
     RECT  142.704 227.509 144.552 227.987 ;
     RECT  142.704 227.987 143.112 228.083 ;
     RECT  141.168 225.397 141.288 228.517 ;
     RECT  128.592 225.013 128.616 228.563 ;
     RECT  136.272 224.531 136.296 228.565 ;
     RECT  137.4 225.827 137.712 228.565 ;
     RECT  146.256 227.509 146.28 228.803 ;
     RECT  136.272 228.565 137.712 229.139 ;
     RECT  139.728 228.181 139.752 229.187 ;
     RECT  144.528 227.987 144.552 229.187 ;
     RECT  142.8 228.083 143.112 229.669 ;
     RECT  132 225.827 132.696 230.053 ;
     RECT  131.136 230.053 132.696 230.291 ;
     RECT  142.656 229.669 143.112 230.339 ;
     RECT  141.168 228.517 141.336 230.771 ;
     RECT  133.824 229.285 133.848 230.917 ;
     RECT  133.824 230.917 133.992 230.963 ;
     RECT  142.8 230.339 143.112 231.493 ;
     RECT  133.968 230.963 133.992 231.925 ;
     RECT  133.968 231.925 134.856 232.019 ;
     RECT  144.576 230.773 144.6 232.019 ;
     RECT  131.136 230.291 132.408 232.499 ;
     RECT  142.704 231.493 143.112 233.077 ;
     RECT  131.904 232.499 132.408 233.653 ;
     RECT  142.464 233.077 143.112 234.181 ;
     RECT  134.496 232.019 134.856 234.229 ;
     RECT  136.272 229.139 136.296 234.229 ;
     RECT  134.496 234.229 136.296 234.275 ;
     RECT  131.664 233.653 132.408 234.851 ;
     RECT  134.496 234.275 134.52 234.899 ;
     RECT  129.6 232.021 129.624 235.093 ;
     RECT  129.408 235.093 129.624 235.139 ;
     RECT  135.744 234.275 136.296 235.235 ;
     RECT  142.464 234.181 143.352 235.763 ;
     RECT  137.4 229.139 137.712 235.765 ;
     RECT  147.168 233.653 147.192 236.293 ;
     RECT  148.2 227.507 148.512 236.293 ;
     RECT  147.168 236.293 148.512 236.339 ;
     RECT  141.168 230.771 141.288 236.485 ;
     RECT  142.8 235.763 143.352 236.531 ;
     RECT  136.272 235.235 136.296 236.533 ;
     RECT  133.92 235.813 133.944 236.579 ;
     RECT  139.392 235.525 139.416 236.675 ;
     RECT  131.904 234.851 132.408 236.867 ;
     RECT  141.168 236.485 141.384 236.965 ;
     RECT  145.872 235.957 145.896 237.013 ;
     RECT  129.408 235.139 129.432 237.109 ;
     RECT  140.832 236.965 141.384 237.155 ;
     RECT  145.824 237.013 145.896 237.155 ;
     RECT  147.6 236.339 148.512 237.251 ;
     RECT  131.904 236.867 132.312 237.443 ;
     RECT  145.824 237.155 145.848 237.731 ;
     RECT  129.408 237.109 129.48 237.779 ;
     RECT  136.08 236.533 136.296 237.877 ;
     RECT  137.4 235.765 137.832 238.259 ;
     RECT  129.408 237.779 129.432 238.307 ;
     RECT  135.456 237.877 136.296 238.549 ;
     RECT  135.36 238.549 136.296 239.987 ;
     RECT  140.832 237.155 141.192 240.035 ;
     RECT  137.4 238.259 137.712 240.133 ;
     RECT  145.344 239.317 145.368 240.659 ;
     RECT  141.168 240.035 141.192 241.139 ;
     RECT  144.096 238.549 144.12 241.139 ;
     RECT  137.4 240.133 137.832 241.235 ;
     RECT  139.68 240.469 139.704 242.339 ;
     RECT  132 237.443 132.312 242.629 ;
     RECT  141.648 241.621 141.672 243.731 ;
     RECT  136.272 239.987 136.296 275.363 ;
     RECT  2.4 2.151 2.712 369.369 ;
     RECT  7.8 2.151 8.112 369.369 ;
     RECT  13.2 2.151 13.512 369.369 ;
     RECT  18.6 2.151 18.912 369.369 ;
     RECT  24 2.151 24.312 369.369 ;
     RECT  29.4 2.151 29.712 369.369 ;
     RECT  34.8 2.151 35.112 369.369 ;
     RECT  40.2 2.151 40.512 369.369 ;
     RECT  45.6 2.151 45.912 369.369 ;
     RECT  51 2.151 51.312 369.369 ;
     RECT  56.4 2.151 56.712 369.369 ;
     RECT  61.8 2.151 62.112 369.369 ;
     RECT  67.2 2.151 67.512 369.369 ;
     RECT  72.6 2.151 72.912 369.369 ;
     RECT  78 2.151 78.312 369.369 ;
     RECT  83.4 2.151 83.712 369.369 ;
     RECT  88.8 2.151 89.112 369.369 ;
     RECT  94.2 2.151 94.512 369.369 ;
     RECT  99.6 2.151 99.912 369.369 ;
     RECT  105 2.151 105.312 369.369 ;
     RECT  110.4 2.151 110.712 369.369 ;
     RECT  115.8 202.979 116.112 369.369 ;
     RECT  121.2 210.035 121.512 369.369 ;
     RECT  126.6 224.051 126.912 369.369 ;
     RECT  137.4 241.235 137.712 369.369 ;
     RECT  142.8 236.531 143.112 369.369 ;
     RECT  148.2 237.251 148.512 369.369 ;
     RECT  153.6 225.155 153.912 369.369 ;
     RECT  159 218.915 159.312 369.369 ;
     RECT  164.4 191.555 164.712 369.369 ;
     RECT  169.8 2.151 170.112 369.369 ;
     RECT  175.2 2.151 175.512 369.369 ;
     RECT  180.6 2.151 180.912 369.369 ;
     RECT  186 2.151 186.312 369.369 ;
     RECT  191.4 2.151 191.712 369.369 ;
     RECT  196.8 2.151 197.112 369.369 ;
     RECT  202.2 2.151 202.512 369.369 ;
     RECT  207.6 2.151 207.912 369.369 ;
     RECT  213 2.151 213.312 369.369 ;
     RECT  218.4 2.151 218.712 369.369 ;
     RECT  223.8 2.151 224.112 369.369 ;
     RECT  229.2 2.151 229.512 369.369 ;
     RECT  234.6 2.151 234.912 369.369 ;
     RECT  240 2.151 240.312 369.369 ;
     RECT  245.4 2.151 245.712 369.369 ;
     RECT  2.4 369.369 2.52 369.383 ;
     RECT  7.8 369.369 7.92 369.383 ;
     RECT  13.2 369.369 13.32 369.383 ;
     RECT  18.6 369.369 18.72 369.383 ;
     RECT  24 369.369 24.12 369.383 ;
     RECT  29.4 369.369 29.52 369.383 ;
     RECT  34.8 369.369 34.92 369.383 ;
     RECT  40.2 369.369 40.32 369.383 ;
     RECT  45.6 369.369 45.72 369.383 ;
     RECT  51 369.369 51.12 369.383 ;
     RECT  56.4 369.369 56.52 369.383 ;
     RECT  61.8 369.369 61.92 369.383 ;
     RECT  67.2 369.369 67.32 369.383 ;
     RECT  72.6 369.369 72.72 369.383 ;
     RECT  78 369.369 78.12 369.383 ;
     RECT  83.4 369.369 83.52 369.383 ;
     RECT  88.8 369.369 88.92 369.383 ;
     RECT  94.2 369.369 94.32 369.383 ;
     RECT  99.6 369.369 99.72 369.383 ;
     RECT  105 369.369 105.12 369.383 ;
     RECT  110.4 369.369 110.52 369.383 ;
     RECT  115.8 369.369 115.92 369.383 ;
     RECT  121.2 369.369 121.32 369.383 ;
     RECT  126.6 369.369 126.72 369.383 ;
     RECT  132 242.629 132.552 369.383 ;
     RECT  137.4 369.369 137.52 369.383 ;
     RECT  142.8 369.369 142.92 369.383 ;
     RECT  148.2 369.369 148.32 369.383 ;
     RECT  153.6 369.369 153.72 369.383 ;
     RECT  159 369.369 159.12 369.383 ;
     RECT  164.4 369.369 164.52 369.383 ;
     RECT  169.8 369.369 169.92 369.383 ;
     RECT  175.2 369.369 175.32 369.383 ;
     RECT  180.6 369.369 180.72 369.383 ;
     RECT  186 369.369 186.12 369.383 ;
     RECT  191.4 369.369 191.52 369.383 ;
     RECT  196.8 369.369 196.92 369.383 ;
     RECT  202.2 369.369 202.32 369.383 ;
     RECT  207.6 369.369 207.72 369.383 ;
     RECT  213 369.369 213.12 369.383 ;
     RECT  218.4 369.369 218.52 369.383 ;
     RECT  223.8 369.369 223.92 369.383 ;
     RECT  229.2 369.369 229.32 369.383 ;
     RECT  234.6 369.369 234.72 369.383 ;
     RECT  240 369.369 240.12 369.383 ;
     RECT  245.4 369.369 245.52 369.383 ;
     RECT  132.432 369.383 132.552 371.077 ;
     RECT  132.24 371.077 132.552 371.267 ;
     RECT  132.24 371.267 132.456 371.365 ;
     RECT  132.144 371.365 132.456 371.472 ;
  END
END ot_qwen_ctrl_pc
END LIBRARY
